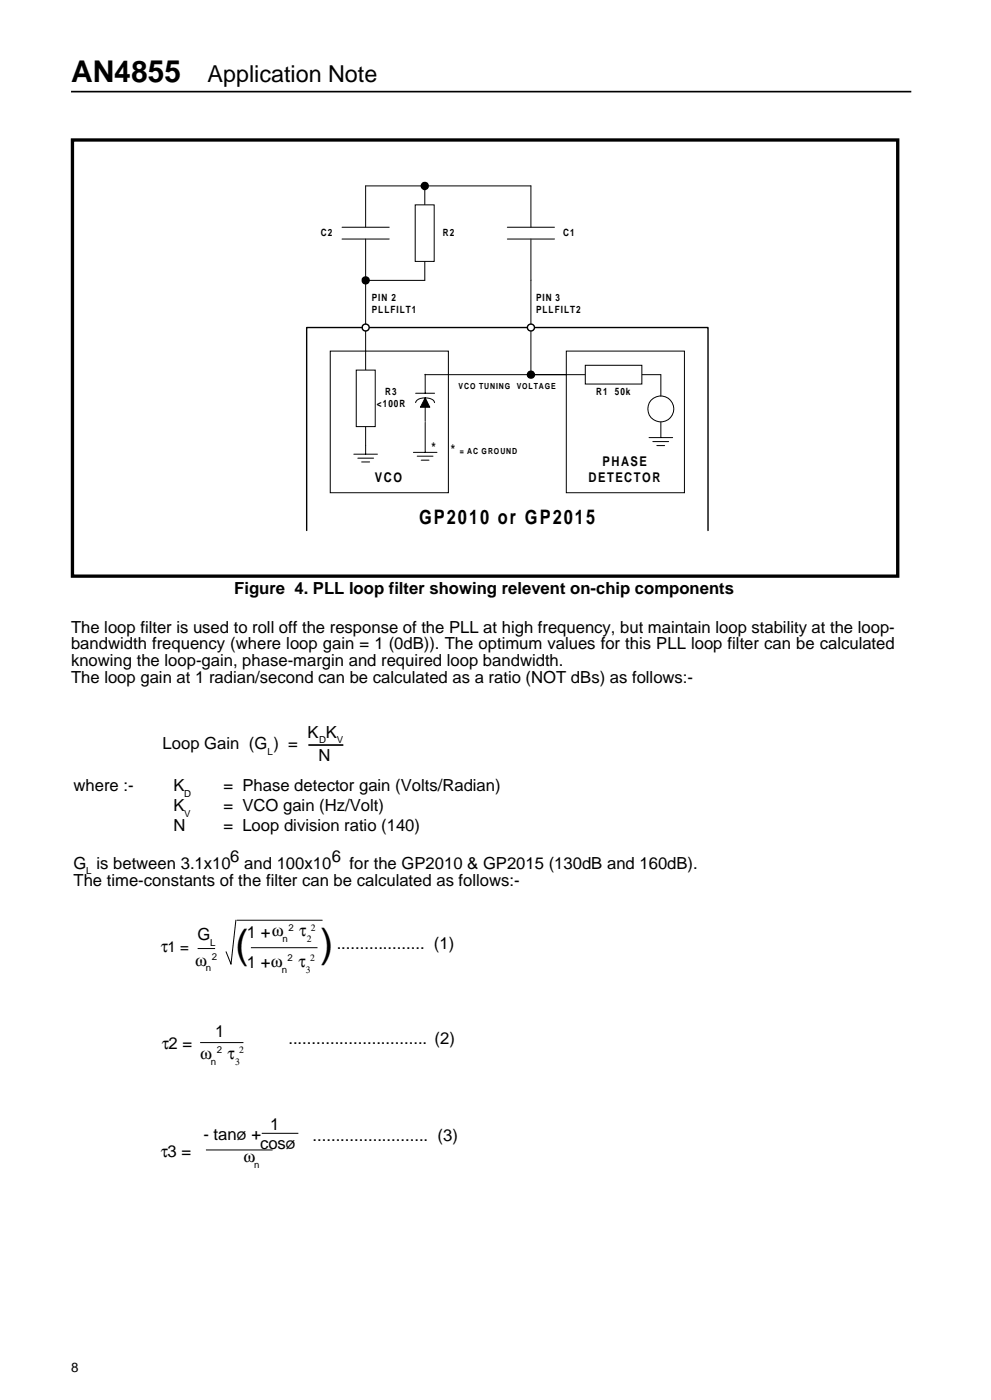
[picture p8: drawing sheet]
<svg xmlns="http://www.w3.org/2000/svg" width="210mm" height="297mm" viewBox="0 0 210 297" stroke-linecap="round" stroke-linejoin="round" font-family="sans-serif">
<defs><g id="words">
<g font-size="8.5">
<text x="49.8" y="203">(</text>
<text x="67.8" y="202.9">)</text>
</g>
<text font-size="6.3" x="15" y="17.3">AN4855</text>
<text font-size="4.9" x="44" y="17.3">Application Note</text>
<text font-size="4.2" x="88.7" y="111.1">GP2010 or GP2015</text>
<g font-size="3.5">
<text x="49.6" y="126">Figure 4. PLL loop filter showing relevent on-chip components</text>
<text x="15" y="134.1">The loop filter is used to roll off the response of the PLL at high frequency, but maintain loop stability at the loop-</text>
<text x="15" y="137.6">bandwidth frequency (where loop gain = 1 (0dB)). The optimum values for this PLL loop filter can be calculated</text>
<text x="15" y="141.1">knowing the loop-gain, phase-margin and required loop bandwidth.</text>
<text x="15" y="144.7">The loop gain at 1 radian/second can be calculated as a ratio (NOT dBs) as follows:-</text>
<text x="34.4" y="158.8">Loop Gain (G ) =</text>
<text x="65.1" y="156.3">K K</text>
<text x="67.4" y="161.2">N</text>
<text x="15.6" y="167.6">where :-</text>
<text x="36.7" y="167.6">K</text>
<text x="47.3" y="167.6">= Phase detector gain (Volts/Radian)</text>
<text x="36.7" y="171.8">K</text>
<text x="47.3" y="171.8">= VCO gain (Hz/Volt)</text>
<text x="36.7" y="176.1">N</text>
<text x="47.3" y="176.1">= Loop division ratio (140)</text>
<text x="15.6" y="184.2">G is between 3.1x10</text>
<text x="48.7" y="182.8">6</text>
<text x="51.7" y="184.2">and 100x10</text>
<text x="70.3" y="182.8">6</text>
<text x="74.1" y="184.2">for the GP2010 &amp; GP2015 (130dB and 160dB).</text>
<text x="15.6" y="187.7">The time-constants of the filter can be calculated as follows:-</text>
<text x="34.1" y="201.8">τ1 =</text>
<text x="41.9" y="199.2">G</text>
<text x="52.3" y="198.8">1 +ω</text>
<text x="63.4" y="198.5">τ</text>
<text x="71.3" y="201.1">................... (1)</text>
<text x="41.3" y="204.6">ω</text>
<text x="52.3" y="205.2">1 +ω</text>
<text x="63.2" y="205">τ</text>
<text x="45.6" y="219.8">1</text>
<text x="61.1" y="221.2">.............................. (2)</text>
<text x="34.3" y="222.3">τ2 =</text>
<text x="42.4" y="224.4">ω</text>
<text x="48.2" y="224.4">τ</text>
<text x="57.2" y="239.4">1</text>
<text x="34.1" y="245.2">τ3 =</text>
<text x="43.1" y="241.5">- tanø +</text>
<text x="55.1" y="243.4">cosø</text>
<text x="66.2" y="241.8">......................... (3)</text>
<text x="51.6" y="246.3">ω</text>
</g>
<g font-size="2.8">
<text x="91.4" y="95.8">*</text>
<text x="95.5" y="96.2">*</text>
<text x="127.6" y="98.8">PHASE</text>
<text x="79.4" y="102.1">VCO</text>
<text x="124.6" y="102.1">DETECTOR</text>
<text x="15" y="290.7">8</text>
</g>
<g font-size="2.1">
<text x="67.9" y="50">C2</text>
<text x="93.8" y="50">R2</text>
<text x="119.3" y="50">C1</text>
<text x="78.8" y="63.7">PIN 2</text>
<text x="113.6" y="63.7">PIN 3</text>
<text x="78.8" y="66.3">PLLFILT1</text>
<text x="113.6" y="66.3">PLLFILT2</text>
<text x="81.6" y="83.7">R3</text>
<text x="126.3" y="83.6">R1</text>
<text x="130.3" y="83.6">50k</text>
<text x="79.8" y="86.3">&lt;100R</text>
</g>
<g font-size="2">
<text x="56.7" y="160">L</text>
<text x="67.6" y="157.5">D</text>
<text x="71.3" y="157.5">V</text>
<text x="39" y="168.8">D</text>
<text x="39" y="173.1">V</text>
<text x="18.2" y="185.2">L</text>
<text x="61.1" y="197.2">2</text>
<text x="65.8" y="197.2">2</text>
<text x="44.5" y="200.4">L</text>
<text x="44.9" y="203.4">2</text>
<text x="59.8" y="199.7">n</text>
<text x="60.9" y="203.7">2</text>
<text x="65" y="199.7">2</text>
<text x="65.7" y="203.7">2</text>
<text x="43.6" y="205.9">n</text>
<text x="59.7" y="206.2">n</text>
<text x="64.8" y="206.2">3</text>
<text x="44.7" y="225.6">n</text>
<text x="45.9" y="223.1">2</text>
<text x="49.8" y="225.6">3</text>
<text x="50.7" y="223.1">2</text>
<text x="53.9" y="247.5">n</text>
</g>
<g font-size="1.8">
<text x="97.1" y="82.5">VCO TUNING</text>
<text x="109.4" y="82.5">VOLTAGE</text>
<text x="97.4" y="96.2">= AC GROUND</text>
</g>
</g></defs>
<path d="M15 19.4h178" fill="none" stroke="#000" stroke-width=".35"/>
<path d="M65 112.4v-43h85v43" fill="none" stroke="#000" stroke-width=".3"/>
<g fill="#fff" stroke="#000" stroke-width=".21">
<path d="M119.9 74.4h25.1v30h-25.1z" fill-rule="evenodd"/>
<path d="M70 74.4h25v30h-25z" fill-rule="evenodd"/>
</g>
<path d="M137.5 92.7h5M138.3 93.6h3.3M139.1 94.4h1.7M140 89.4v3.3" fill="none" stroke="#000" stroke-width=".21"/>
<circle cx="140" cy="86.7" r="2.75" fill="#fff" stroke="#000" stroke-width=".21"/>
<path d="M119.9 79.4h4.1M135.9 79.4h4.1" fill="none" stroke="#000" stroke-width=".21"/>
<path d="M124 77.4h11.9v4h-11.9z" fill-rule="evenodd" fill="#fff" stroke="#000" stroke-width=".21"/>
<path d="M112.5 59.4v20h7.4M90.1 79.3v4M140 79.4v4.5M87.6 95.9h5M88 85.3a2.38 2.38 0 0 1 3-.9 1.13 1.13 0 0 1 1.1 .9M88 83.3h4.1M88.4 96.7h3.3M89.2 97.5h1.7M90.1 84.3v5M90.1 89.5v6.4" fill="none" stroke="#000" stroke-width=".21"/>
<path d="M90.1 84.3l.9 2h-2z" fill-rule="evenodd" fill="#000" stroke="#000" stroke-width=".21"/>
<circle cx="112.4" cy="69.4" r=".75" fill="#fff" stroke="#000" stroke-width=".3"/>
<path d="M77.4 74.4v4M90 79.4h29.9M77.4 90.4v4" fill="none" stroke="#000" stroke-width=".21"/>
<circle cx="112.4" cy="79.4" r=".75" fill="#000" stroke="#000" stroke-width=".3"/>
<path d="M75.5 78.4h4v12h-4z" fill-rule="evenodd" fill="#fff" stroke="#000" stroke-width=".21"/>
<path d="M112.5 39.4v8.8M112.5 50.7v8.7" fill="none" stroke="#000" stroke-width=".21"/>
<path d="M107.5 50.7h10z" fill="#fff"/>
<path d="M77.4 39.4v8.8M77.4 50.7v8.7M107.5 50.7h10M107.5 48.2h10" fill="none" stroke="#000" stroke-width=".21"/>
<path d="M72.4 48.2h10z" fill="#fff"/>
<path d="M90 39.4v4M72.4 48.2h10M72.4 50.7h10M90 55.4v4" fill="none" stroke="#000" stroke-width=".21"/>
<path d="M87.9 43.4h4.1v12h-4.1z" fill-rule="evenodd" fill="#fff" stroke="#000" stroke-width=".21"/>
<path d="M77.4 39.4h35.1M90 59.4h-12.6v15" fill="none" stroke="#000" stroke-width=".21"/>
<circle cx="77.5" cy="69.4" r=".74" fill="#fff" stroke="#000" stroke-width=".3"/>
<g fill="#000" stroke="#000" stroke-width=".3">
<circle cx="90" cy="39.4" r=".75"/>
<circle cx="77.5" cy="59.4" r=".74"/>
</g>
<path d="M74.9 96.2h5M75.8 97.1h3.3M76.6 97.9h1.7M77.4 94.4v1.8M50 194.9l-1.1 9.6M50.1 195h18.2M41.9 201h3.7M47.9 201.6l1 2.7M53.1 200.8h14.2M42.4 220.9h9.2M43.6 243.7h14.1M55.4 240.2h7.8" fill="none" stroke="#000" stroke-width=".21"/>
<path d="M15.3 29.7h174.8v92.4h-174.8z" fill="none" stroke="#000" stroke-width=".71" stroke-linecap="butt"/>
<path d="M65.3 157.9h7.4" fill="none" stroke="#000" stroke-width=".35"/>
<use href="#words"/>
</svg>
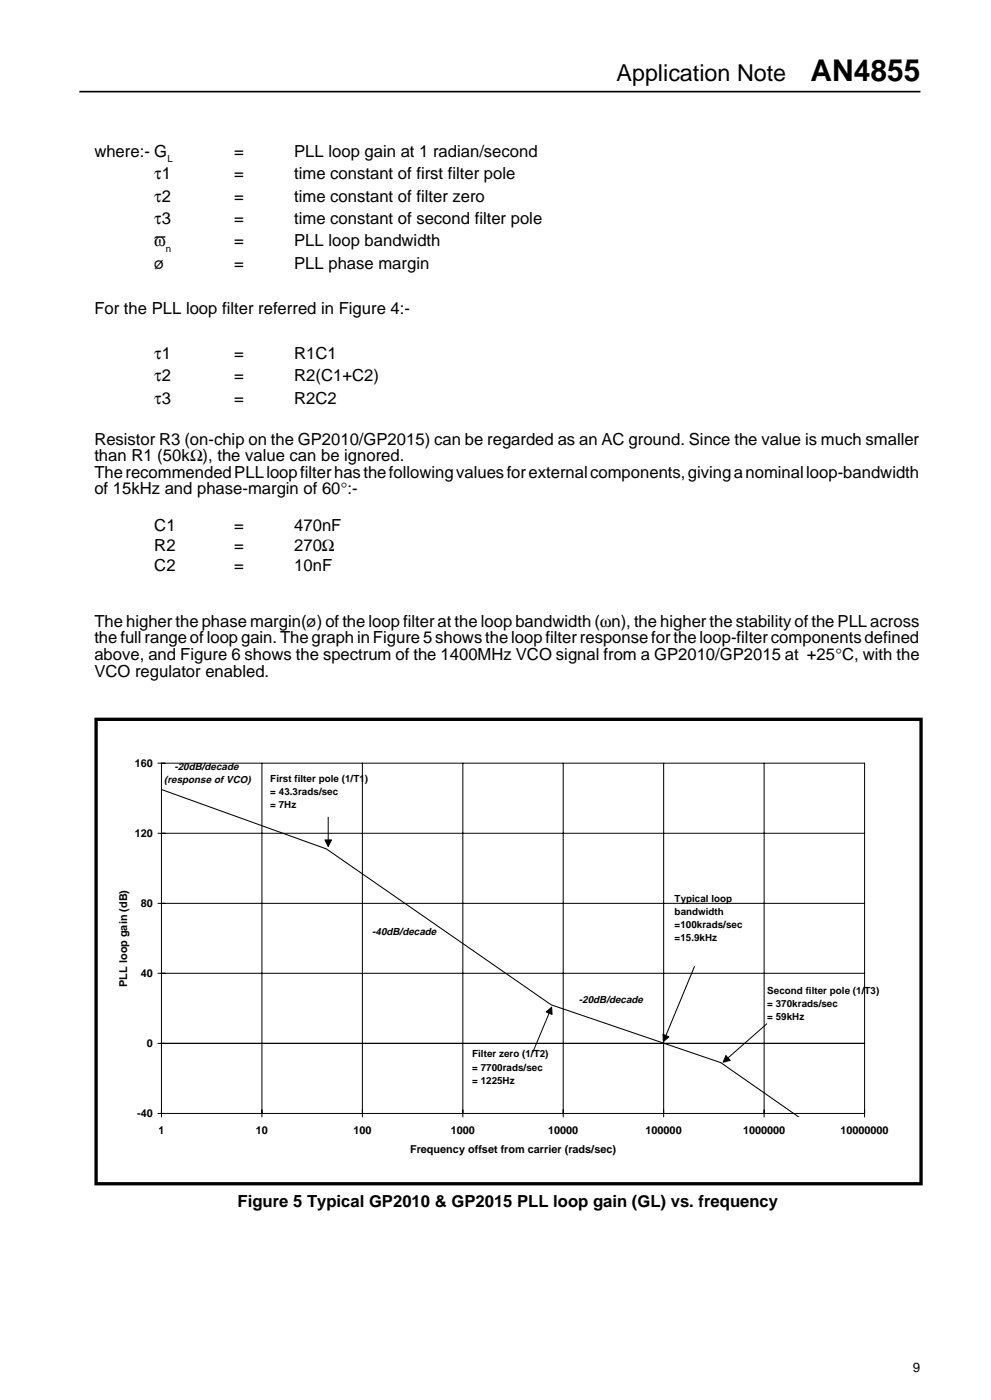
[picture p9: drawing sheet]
<svg xmlns="http://www.w3.org/2000/svg" width="210mm" height="297mm" viewBox="0 0 210 297" stroke-linecap="round" stroke-linejoin="round" font-family="sans-serif">
<defs><g id="words">
<text font-size="6.3" x="171.7" y="17.1">AN4855</text>
<text font-size="4.9" x="130.6" y="17.1">Application Note</text>
<g font-size="3.5">
<text x="20" y="33.2">where:- G</text>
<text x="49.6" y="33.2">=</text>
<text x="62.3" y="33.2">PLL loop gain at 1 radian/second</text>
<text x="32.7" y="37.9">τ1</text>
<text x="49.6" y="37.9">=</text>
<text x="62.3" y="37.9">time constant of first filter pole</text>
<text x="32.7" y="42.7">τ2</text>
<text x="32.7" y="47.5">τ3</text>
<text x="49.6" y="42.7">=</text>
<text x="49.6" y="47.5">=</text>
<text x="62.3" y="42.7">time constant of filter zero</text>
<text x="62.3" y="47.5">time constant of second filter pole</text>
<text x="32.7" y="52.2">ϖ</text>
<text x="49.6" y="52.2">=</text>
<text x="62.3" y="52.2">PLL loop bandwidth</text>
<text x="32.7" y="57">ø</text>
<text x="49.6" y="57">=</text>
<text x="62.3" y="57">PLL phase margin</text>
<text x="20" y="66.5">For the PLL loop filter referred in Figure 4:-</text>
<text x="32.7" y="76">τ1</text>
<text x="49.6" y="76">=</text>
<text x="62.3" y="76">R1C1</text>
<text x="32.7" y="80.8">τ2</text>
<text x="49.6" y="80.8">=</text>
<text x="62.3" y="80.8">R2(C1+C2)</text>
<text x="32.7" y="85.6">τ3</text>
<text x="49.6" y="85.6">=</text>
<text x="62.3" y="85.6">R2C2</text>
<text x="20" y="94.2">Resistor R3 (on-chip on the GP2010/GP2015) can be regarded as an AC ground. Since the value is much smaller</text>
<text x="20" y="97.7">than R1 (50kΩ), the value can be ignored.</text>
<text x="20" y="101.3">The recommended PLL loop filter has the following values for external components, giving a nominal loop-bandwidth</text>
<text x="20" y="104.8">of 15kHz and phase-margin of 60°:-</text>
<text x="32.7" y="112.6">C1</text>
<text x="49.6" y="112.6">=</text>
<text x="62.3" y="112.6">470nF</text>
<text x="32.7" y="116.8">R2</text>
<text x="49.6" y="116.8">=</text>
<text x="62.3" y="116.8">270Ω</text>
<text x="32.7" y="121">C2</text>
<text x="49.6" y="121">=</text>
<text x="62.3" y="121">10nF</text>
<text x="20" y="132.8">The higher the phase margin(ø) of the loop filter at the loop bandwidth (ωn), the higher the stability of the PLL across</text>
<text x="20" y="136.4">the full range of loop gain. The graph in Figure 5 shows the loop filter response for the loop-filter components defined</text>
<text x="20" y="139.9">above, and Figure 6 shows the spectrum of the 1400MHz VCO signal from a GP2010/GP2015 at +25°C, with the</text>
<text x="20" y="143.4">VCO regulator enabled.</text>
<text x="50.3" y="255.8">Figure 5 Typical GP2010 &amp; GP2015 PLL loop gain (GL) vs. frequency</text>
</g>
<text font-size="2.8" x="193.4" y="290.7">9</text>
<g font-size="2.3">
<text x="28.5" y="162.5">160</text>
<text x="28.5" y="177.3">120</text>
<text x="29.8" y="192.2">80</text>
<text x="26.9" y="209.1" transform="rotate(-90 26.9 209.1)">PLL loop gain (dB)</text>
<text x="29.8" y="207">40</text>
<text x="31.1" y="221.9">0</text>
<text x="29" y="236.7">-40</text>
<text x="33.6" y="240.2">1</text>
<text x="54.2" y="240.2">10</text>
<text x="74.8" y="240.2">100</text>
<text x="86.9" y="244.3">Frequency offset from carrier (rads/sec)</text>
<text x="95.5" y="240.2">1000</text>
<text x="116.1" y="240.2">10000</text>
<text x="136.7" y="240.2">100000</text>
<text x="157.4" y="240.2">1000000</text>
<text x="178" y="240.2">10000000</text>
</g>
<g font-size="2.1">
<text x="34.8" y="165.9">(response of VCO)</text>
<text x="36.9" y="163.1">-20dB/decade</text>
<text x="57.3" y="165.7">First filter pole (1/T1)</text>
<text x="57.3" y="168.4">= 43.3rads/sec</text>
<text x="57.3" y="171.2">= 7Hz</text>
<text x="142.9" y="191.1">Typical loop</text>
<text x="142.9" y="193.9">bandwidth</text>
<text x="142.9" y="196.7">=100krads/sec</text>
<text x="78.8" y="198.1">-40dB/decade</text>
<text x="142.9" y="199.5">=15.9kHz</text>
<text x="122.6" y="212.4">-20dB/decade</text>
<text x="162.5" y="210.7">Second filter pole (1/T3)</text>
<text x="162.5" y="213.4">= 370krads/sec</text>
<text x="162.5" y="216.2">= 59kHz</text>
<text x="100" y="224.1">Filter zero (1/T2)</text>
<text x="100" y="226.9">= 7700rads/sec</text>
<text x="100" y="229.6">= 1225Hz</text>
</g>
<g font-size="2">
<text x="35.5" y="34.4">L</text>
<text x="35.2" y="53.5">n</text>
</g>
</g></defs>
<path d="M16.8 19.4h178.2" fill="none" stroke="#000" stroke-width=".35"/>
<g fill="none" stroke="#000" stroke-width=".21">
<path d="M33.4 176.6h149.7M33.4 161.7h149.7v75M34.2 161.7v75M55.5 161.7v75M69.5 173.2v5.2M76.8 161.7v75M98 161.7v75M119.3 161.7v75M140.6 161.7v75M161.8 161.7v75M33.4 191.4h149.7M33.4 206.3h149.7"/>
<path d="M116.5 214.3l-3.7 8.8M162.4 217l-8.5 7.5M33.4 221.1h149.7M33.4 236h149.7"/>
</g>
<path d="M34.2 167.3l35 12.6 47.6 33 35.9 12.3 16.4 11.5M147.1 204.8l-6.2 15.1M33.9 221.1h149.3" fill="none" stroke="#000" stroke-width=".22"/>
<path d="M140.4 219.2l1.3 .5-1.2 1z" fill-rule="evenodd" fill="#000" stroke="#000" stroke-width=".22"/>
<g fill="#000" stroke="#000" stroke-width=".21">
<path d="M68.8 178h1.4l-.7 1.4z" fill-rule="evenodd"/>
<path d="M115.7 214.4l1.1-1 .1 1.6z" fill-rule="evenodd"/>
<path d="M153.7 223.7l1 1-1.5 .4z" fill-rule="evenodd"/>
</g>
<path d="M20.4 152.4h174.7v98.5h-174.7z" fill="none" stroke="#000" stroke-width=".71" stroke-linecap="butt"/>
<use href="#words"/>
</svg>
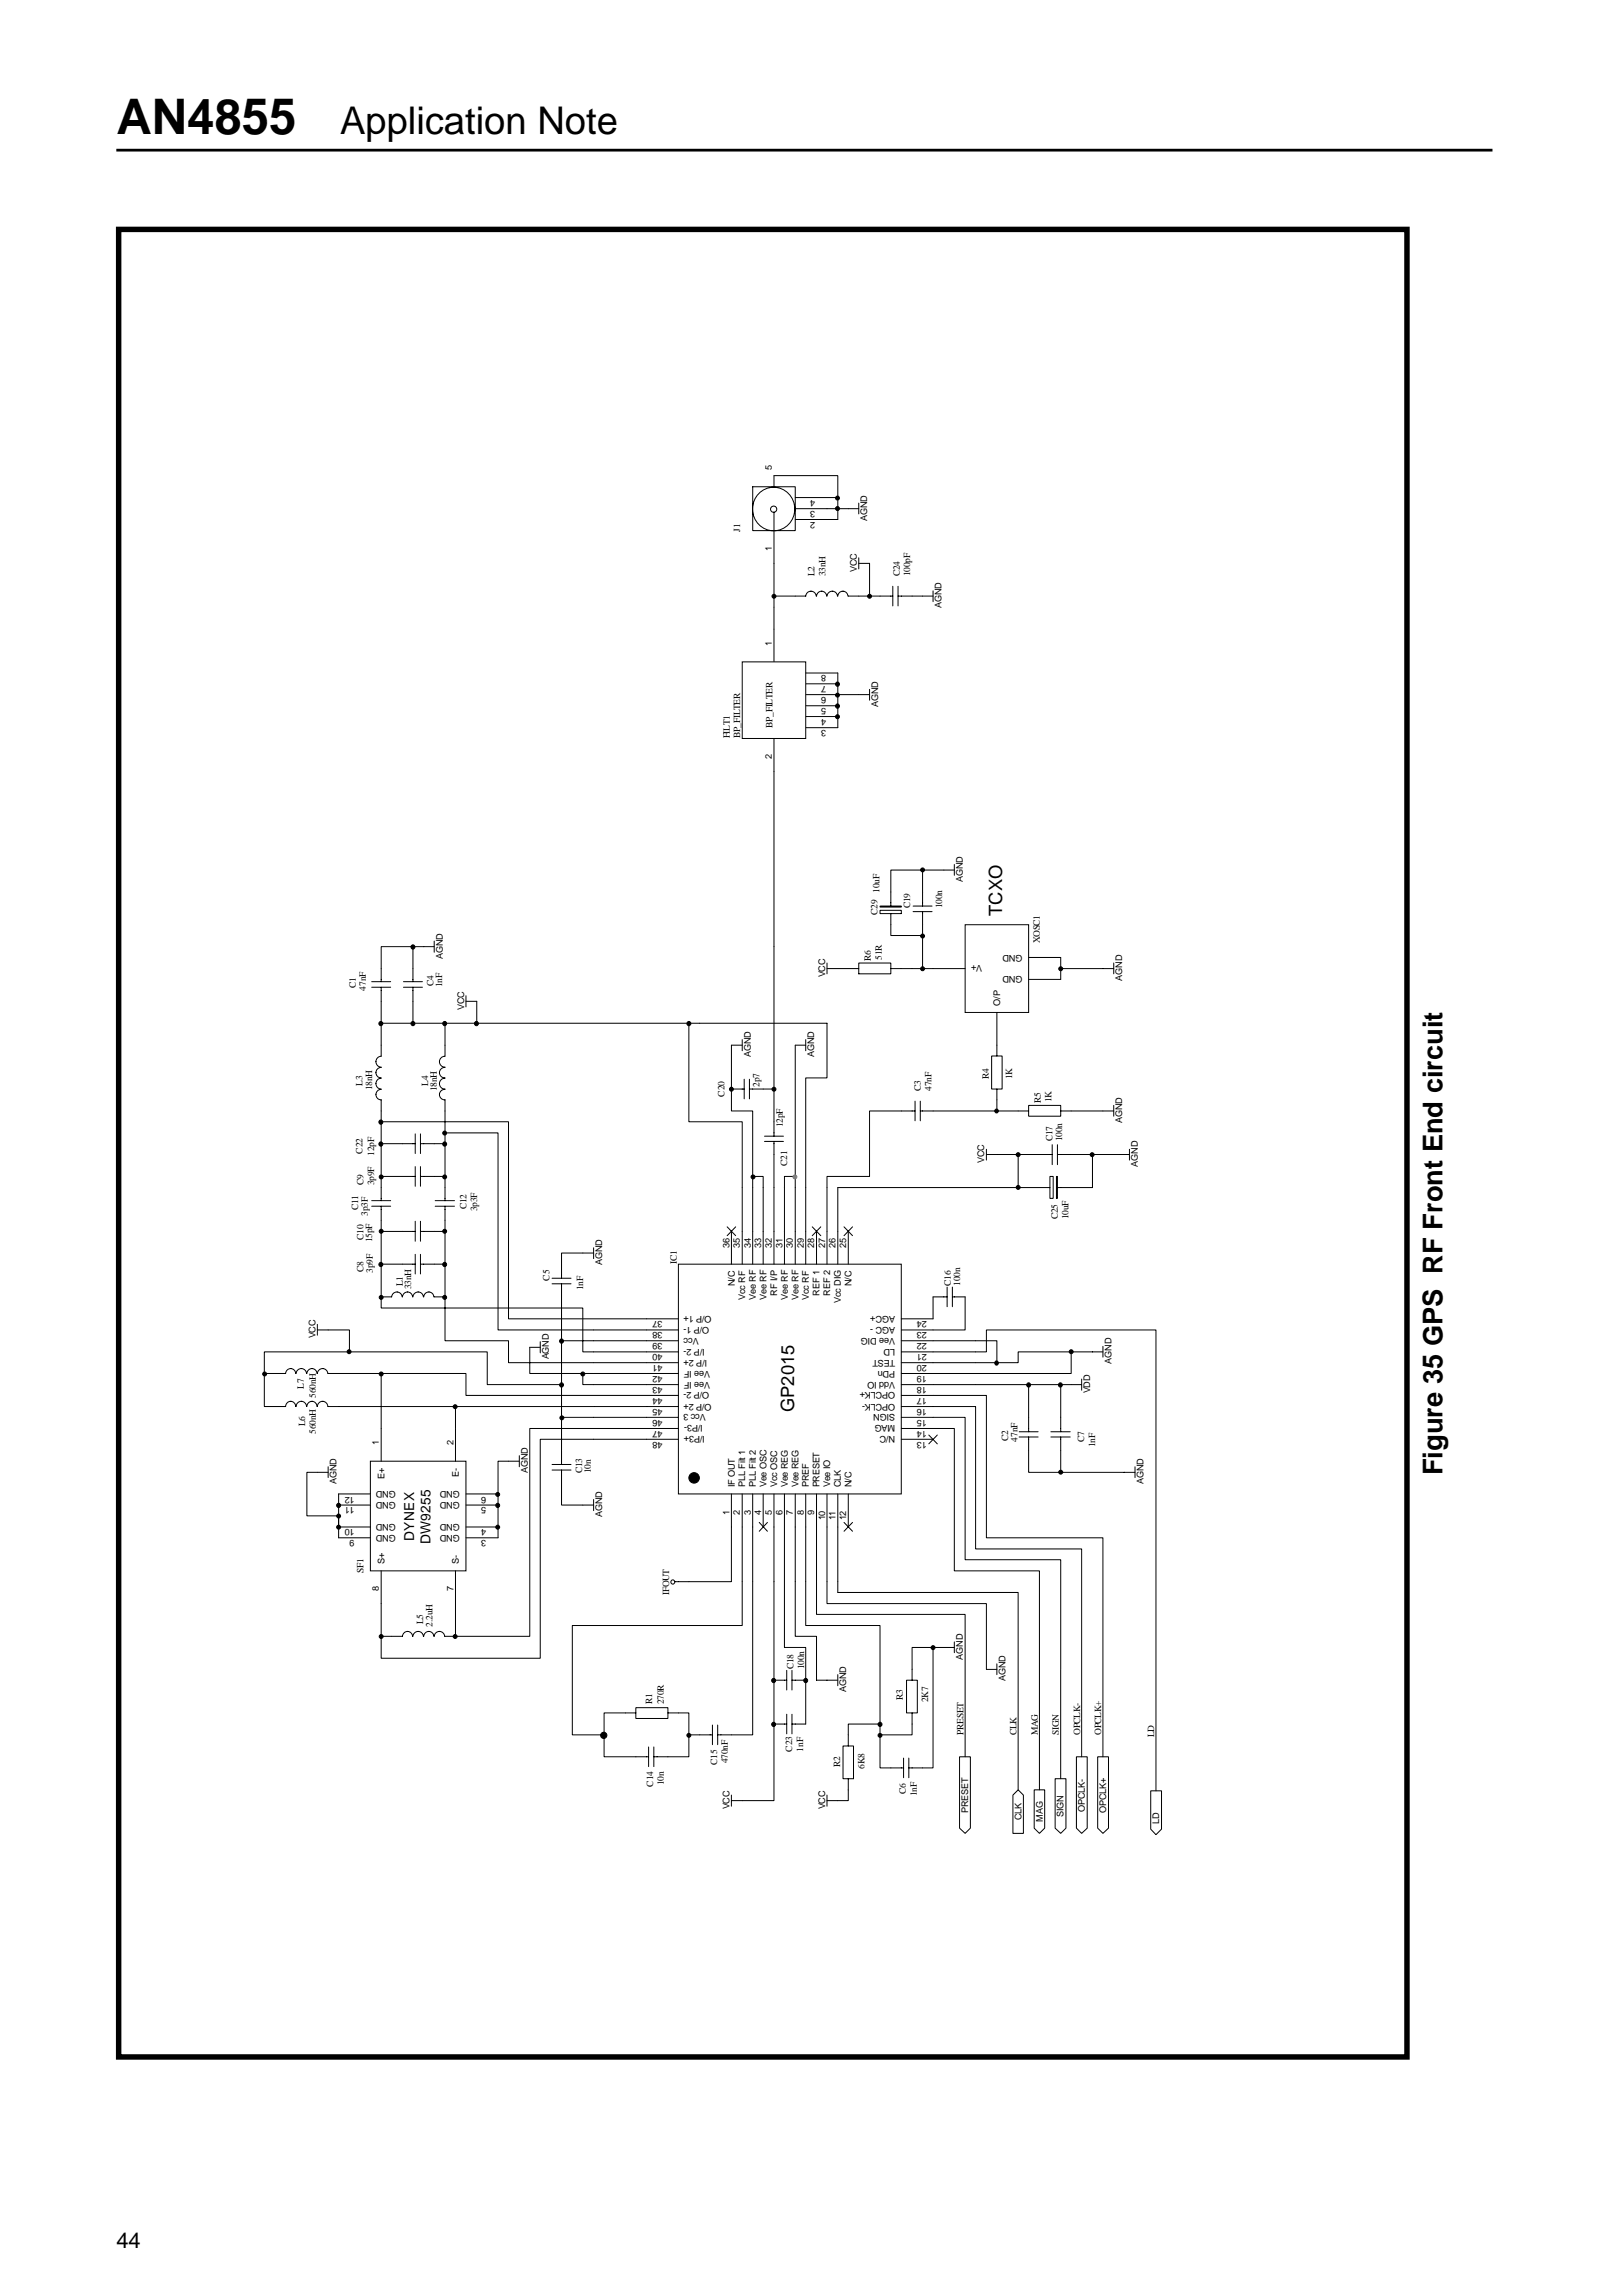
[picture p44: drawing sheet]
<svg xmlns="http://www.w3.org/2000/svg" width="210mm" height="297mm" viewBox="0 0 210 297" stroke-linecap="round" stroke-linejoin="round" font-family="sans-serif">
<defs><g id="words">
<text font-size="6.3" x="15" y="17.3">AN4855</text>
<text font-size="4.9" x="44" y="17.3">Application Note</text>
<text font-size="3.5" x="186.6" y="190.8" transform="rotate(-90 186.6 190.8)">Figure 35 GPS RF Front End circuit</text>
<text font-size="2.8" x="15" y="290.7">44</text>
<g font-size="2.4">
<text x="129.6" y="118.5" transform="rotate(-90 129.6 118.5)">TCXO</text>
<text x="102.7" y="182.6" transform="rotate(-90 102.7 182.6)">GP2015</text>
</g>
<g font-size="1.8">
<text x="53.6" y="199.3" transform="rotate(-90 53.6 199.3)">DYNEX</text>
<text x="55.7" y="199.7" transform="rotate(-90 55.7 199.7)">DW9255</text>
</g>
<g font-size="1.2">
<text x="99.8" y="60.8" transform="rotate(-90 99.8 60.8)">5</text>
<text x="105.4" y="64.7" transform="rotate(-180 105.4 64.7)">4</text>
<text x="95.7" y="68.8" transform="rotate(-90 95.7 68.8)">J1</text>
<text x="99.8" y="71.3" transform="rotate(-90 99.8 71.3)">1</text>
<text x="105.4" y="67.5" transform="rotate(-180 105.4 67.5)">2</text>
<text x="105.4" y="66.1" transform="rotate(-180 105.4 66.1)">3</text>
<text x="112.2" y="67.4" transform="rotate(-90 112.2 67.4)">AGND</text>
<text x="105.3" y="74.6" transform="rotate(-90 105.3 74.6)">L2</text>
<text x="106.7" y="74.6" transform="rotate(-90 106.7 74.6)">33nH</text>
<text x="110.8" y="74" transform="rotate(-90 110.8 74)">VCC</text>
<text x="116.4" y="74.6" transform="rotate(-90 116.4 74.6)">C24</text>
<text x="117.7" y="74.6" transform="rotate(-90 117.7 74.6)">100pF</text>
<text x="99.8" y="83.5" transform="rotate(-90 99.8 83.5)">1</text>
<text x="121.8" y="78.7" transform="rotate(-90 121.8 78.7)">AGND</text>
<text x="106.8" y="88.7" transform="rotate(-180 106.8 88.7)">7</text>
<text x="106.8" y="87.3" transform="rotate(-180 106.8 87.3)">8</text>
<text x="94.4" y="95.5" transform="rotate(-90 94.4 95.5)">FILT1</text>
<text x="95.7" y="95.5" transform="rotate(-90 95.7 95.5)">BP_FILTER</text>
<text x="99.9" y="94.1" transform="rotate(-90 99.9 94.1)">BP_FILTER</text>
<text x="106.8" y="94.4" transform="rotate(-180 106.8 94.4)">3</text>
<text x="106.8" y="93" transform="rotate(-180 106.8 93)">4</text>
<text x="106.8" y="91.6" transform="rotate(-180 106.8 91.6)">5</text>
<text x="106.8" y="90.2" transform="rotate(-180 106.8 90.2)">6</text>
<text x="113.6" y="91.4" transform="rotate(-90 113.6 91.4)">AGND</text>
<text x="99.8" y="98.2" transform="rotate(-90 99.8 98.2)">2</text>
<text x="113.5" y="118.3" transform="rotate(-90 113.5 118.3)">C29</text>
<text x="113.7" y="115.5" transform="rotate(-90 113.7 115.5)">10uF</text>
<text x="117.7" y="117.5" transform="rotate(-90 117.7 117.5)">C19</text>
<text x="121.9" y="117.5" transform="rotate(-90 121.9 117.5)">100n</text>
<text x="124.5" y="114.1" transform="rotate(-90 124.5 114.1)">AGND</text>
<text x="57.3" y="124" transform="rotate(-90 57.3 124)">AGND</text>
<text x="112.6" y="124.3" transform="rotate(-90 112.6 124.3)">R6</text>
<text x="114" y="124.1" transform="rotate(-90 114 124.1)">51R</text>
<text x="127" y="124.8" transform="rotate(-180 127 124.8)">V+</text>
<text x="132.2" y="123.4" transform="rotate(-180 132.2 123.4)">GND</text>
<text x="134.5" y="122" transform="rotate(-90 134.5 122)">XOSC1</text>
<text x="46" y="127.8" transform="rotate(-90 46 127.8)">C1</text>
<text x="47.3" y="128.1" transform="rotate(-90 47.3 128.1)">47nF</text>
<text x="56.1" y="127.5" transform="rotate(-90 56.1 127.5)">C4</text>
<text x="57.2" y="127.7" transform="rotate(-90 57.2 127.7)">1nF</text>
<text x="60" y="130.6" transform="rotate(-90 60 130.6)">VCC</text>
<text x="106.7" y="126.4" transform="rotate(-90 106.7 126.4)">VCC</text>
<text x="129.4" y="130.1" transform="rotate(-90 129.4 130.1)">O/P</text>
<text x="132.2" y="126.3" transform="rotate(-180 132.2 126.3)">GND</text>
<text x="145.1" y="126.8" transform="rotate(-90 145.1 126.8)">AGND</text>
<text x="97.1" y="136.7" transform="rotate(-90 97.1 136.7)">AGND</text>
<text x="105.3" y="136.7" transform="rotate(-90 105.3 136.7)">AGND</text>
<text x="46.9" y="140.4" transform="rotate(-90 46.9 140.4)">L3</text>
<text x="48.1" y="141" transform="rotate(-90 48.1 141)">18nH</text>
<text x="55.4" y="140.4" transform="rotate(-90 55.4 140.4)">L4</text>
<text x="56.5" y="141.1" transform="rotate(-90 56.5 141.1)">18nH</text>
<text x="93.7" y="141.8" transform="rotate(-90 93.7 141.8)">C20</text>
<text x="98.2" y="140.6" transform="rotate(-90 98.2 140.6)">2p7</text>
<text x="119.1" y="141.1" transform="rotate(-90 119.1 141.1)">C3</text>
<text x="120.5" y="141.1" transform="rotate(-90 120.5 141.1)">47nF</text>
<text x="127.9" y="139.6" transform="rotate(-90 127.9 139.6)">R4</text>
<text x="130.9" y="139.6" transform="rotate(-90 130.9 139.6)">1K</text>
<text x="134.6" y="142.7" transform="rotate(-90 134.6 142.7)">R5</text>
<text x="136" y="142.5" transform="rotate(-90 136 142.5)">1K</text>
<text x="46.9" y="149.2" transform="rotate(-90 46.9 149.2)">C22</text>
<text x="48.4" y="149.5" transform="rotate(-90 48.4 149.5)">12pF</text>
<text x="101.2" y="145.8" transform="rotate(-90 101.2 145.8)">12pF</text>
<text x="136.1" y="147.6" transform="rotate(-90 136.1 147.6)">C17</text>
<text x="137.4" y="147.6" transform="rotate(-90 137.4 147.6)">100n</text>
<text x="145.1" y="145.2" transform="rotate(-90 145.1 145.2)">AGND</text>
<text x="47" y="153.3" transform="rotate(-90 47 153.3)">C9</text>
<text x="48.4" y="153.3" transform="rotate(-90 48.4 153.3)">3p9F</text>
<text x="101.8" y="150.8" transform="rotate(-90 101.8 150.8)">C21</text>
<text x="127.3" y="150.5" transform="rotate(-90 127.3 150.5)">VCC</text>
<text x="147.2" y="150.9" transform="rotate(-90 147.2 150.9)">AGND</text>
<text x="46.3" y="156.6" transform="rotate(-90 46.3 156.6)">C11</text>
<text x="47" y="160.4" transform="rotate(-90 47 160.4)">C10</text>
<text x="47.6" y="157.3" transform="rotate(-90 47.6 157.3)">3p3F</text>
<text x="48.1" y="160.7" transform="rotate(-90 48.1 160.7)">15pF</text>
<text x="60.3" y="156.4" transform="rotate(-90 60.3 156.4)">C12</text>
<text x="61.7" y="156.7" transform="rotate(-90 61.7 156.7)">3p3F</text>
<text x="94.3" y="161.4" transform="rotate(-90 94.3 161.4)">36</text>
<text x="95.7" y="161.4" transform="rotate(-90 95.7 161.4)">35</text>
<text x="97.1" y="161.4" transform="rotate(-90 97.1 161.4)">34</text>
<text x="98.4" y="161.4" transform="rotate(-90 98.4 161.4)">33</text>
<text x="99.8" y="161.4" transform="rotate(-90 99.8 161.4)">32</text>
<text x="101.2" y="161.4" transform="rotate(-90 101.2 161.4)">31</text>
<text x="102.6" y="161.4" transform="rotate(-90 102.6 161.4)">30</text>
<text x="104" y="161.4" transform="rotate(-90 104 161.4)">29</text>
<text x="105.3" y="161.4" transform="rotate(-90 105.3 161.4)">28</text>
<text x="106.7" y="161.4" transform="rotate(-90 106.7 161.4)">27</text>
<text x="108.1" y="161.4" transform="rotate(-90 108.1 161.4)">26</text>
<text x="109.5" y="161.4" transform="rotate(-90 109.5 161.4)">25</text>
<text x="136.8" y="157.7" transform="rotate(-90 136.8 157.7)">C25</text>
<text x="138.2" y="157.7" transform="rotate(-90 138.2 157.7)">10uF</text>
<text x="47" y="164.5" transform="rotate(-90 47 164.5)">C8</text>
<text x="48.2" y="164.6" transform="rotate(-90 48.2 164.6)">3p9F</text>
<text x="52.1" y="166.3" transform="rotate(-90 52.1 166.3)">L1</text>
<text x="53.2" y="166.8" transform="rotate(-90 53.2 166.8)">33nH</text>
<text x="71.1" y="165.6" transform="rotate(-90 71.1 165.6)">C5</text>
<text x="75.4" y="166.9" transform="rotate(-90 75.4 166.9)">1nF</text>
<text x="77.9" y="163.6" transform="rotate(-90 77.9 163.6)">AGND</text>
<text x="87.5" y="163.5" transform="rotate(-90 87.5 163.5)">IC1</text>
<text x="95" y="166.3" transform="rotate(-90 95 166.3)">N/C</text>
<text x="100.5" y="167.6" transform="rotate(-90 100.5 167.6)">RF I/P</text>
<text x="106" y="167.6" transform="rotate(-90 106 167.6)">REF 1</text>
<text x="107.4" y="167.6" transform="rotate(-90 107.4 167.6)">REF 2</text>
<text x="110.1" y="166.3" transform="rotate(-90 110.1 166.3)">N/C</text>
<text x="123" y="166.3" transform="rotate(-90 123 166.3)">C16</text>
<text x="124.2" y="166.3" transform="rotate(-90 124.2 166.3)">100n</text>
<text x="40.8" y="173.1" transform="rotate(-90 40.8 173.1)">VCC</text>
<text x="85.7" y="172.3" transform="rotate(-180 85.7 172.3)">38</text>
<text x="85.7" y="173.7" transform="rotate(-180 85.7 173.7)">39</text>
<text x="85.7" y="170.9" transform="rotate(-180 85.7 170.9)">37</text>
<text x="90.4" y="173" transform="rotate(-180 90.4 173)">Vcc</text>
<text x="91.7" y="171.6" transform="rotate(-180 91.7 171.6)">O/P 1-</text>
<text x="92" y="170.2" transform="rotate(-180 92 170.2)">O/P 1+</text>
<text x="96.4" y="168.2" transform="rotate(-90 96.4 168.2)">Vcc RF</text>
<text x="97.8" y="168.2" transform="rotate(-90 97.8 168.2)">Vee RF</text>
<text x="99.1" y="168.2" transform="rotate(-90 99.1 168.2)">Vee RF</text>
<text x="101.9" y="168.2" transform="rotate(-90 101.9 168.2)">Vee RF</text>
<text x="103.3" y="168.2" transform="rotate(-90 103.3 168.2)">Vee RF</text>
<text x="104.6" y="168.2" transform="rotate(-90 104.6 168.2)">Vcc RF</text>
<text x="108.7" y="168.6" transform="rotate(-90 108.7 168.6)">Vcc DIG</text>
<text x="115.8" y="173" transform="rotate(-180 115.8 173)">Vee DIG</text>
<text x="115.8" y="171.6" transform="rotate(-180 115.8 171.6)">AGC -</text>
<text x="115.8" y="170.2" transform="rotate(-180 115.8 170.2)">AGC+</text>
<text x="119.9" y="173.7" transform="rotate(-180 119.9 173.7)">22</text>
<text x="119.9" y="172.3" transform="rotate(-180 119.9 172.3)">23</text>
<text x="119.9" y="170.9" transform="rotate(-180 119.9 170.9)">24</text>
<text x="39.3" y="179.6" transform="rotate(-90 39.3 179.6)">L7</text>
<text x="71" y="175.8" transform="rotate(-90 71 175.8)">AGND</text>
<text x="85.7" y="179.4" transform="rotate(-180 85.7 179.4)">43</text>
<text x="85.7" y="176.5" transform="rotate(-180 85.7 176.5)">41</text>
<text x="85.7" y="178" transform="rotate(-180 85.7 178)">42</text>
<text x="85.7" y="175.1" transform="rotate(-180 85.7 175.1)">40</text>
<text x="91.2" y="174.4" transform="rotate(-180 91.2 174.4)">I/P 2-</text>
<text x="91.5" y="175.9" transform="rotate(-180 91.5 175.9)">I/P 2+</text>
<text x="91.8" y="178.7" transform="rotate(-180 91.8 178.7)">Vee IF</text>
<text x="91.8" y="177.3" transform="rotate(-180 91.8 177.3)">Vee IF</text>
<text x="115.8" y="178.7" transform="rotate(-180 115.8 178.7)">Vdd IO</text>
<text x="115.8" y="177.3" transform="rotate(-180 115.8 177.3)">PDn</text>
<text x="115.8" y="175.9" transform="rotate(-180 115.8 175.9)">TEST</text>
<text x="115.8" y="174.4" transform="rotate(-180 115.8 174.4)">LD</text>
<text x="119.9" y="178" transform="rotate(-180 119.9 178)">19</text>
<text x="119.9" y="176.5" transform="rotate(-180 119.9 176.5)">20</text>
<text x="119.9" y="175.1" transform="rotate(-180 119.9 175.1)">21</text>
<text x="119.9" y="179.4" transform="rotate(-180 119.9 179.4)">18</text>
<text x="143.7" y="176.4" transform="rotate(-90 143.7 176.4)">AGND</text>
<text x="39.5" y="184.4" transform="rotate(-90 39.5 184.4)">L6</text>
<text x="40.8" y="180.8" transform="rotate(-90 40.8 180.8)">560nH</text>
<text x="40.8" y="185.4" transform="rotate(-90 40.8 185.4)">560nH</text>
<text x="85.7" y="185" transform="rotate(-180 85.7 185)">47</text>
<text x="85.7" y="183.6" transform="rotate(-180 85.7 183.6)">46</text>
<text x="85.7" y="180.8" transform="rotate(-180 85.7 180.8)">44</text>
<text x="85.7" y="182.2" transform="rotate(-180 85.7 182.2)">45</text>
<text x="90.9" y="184.3" transform="rotate(-180 90.9 184.3)">I/P3-</text>
<text x="91.2" y="185.8" transform="rotate(-180 91.2 185.8)">I/P3+</text>
<text x="91.3" y="182.9" transform="rotate(-180 91.3 182.9)">Vcc 3</text>
<text x="91.7" y="180.1" transform="rotate(-180 91.7 180.1)">O/P 2-</text>
<text x="92" y="181.5" transform="rotate(-180 92 181.5)">O/P 2+</text>
<text x="115.8" y="185.8" transform="rotate(-180 115.8 185.8)">N/C</text>
<text x="115.8" y="184.3" transform="rotate(-180 115.8 184.3)">MAG</text>
<text x="115.8" y="182.9" transform="rotate(-180 115.8 182.9)">SIGN</text>
<text x="115.8" y="181.5" transform="rotate(-180 115.8 181.5)">OPCLK-</text>
<text x="115.8" y="180.1" transform="rotate(-180 115.8 180.1)">OPCLK+</text>
<text x="119.9" y="185" transform="rotate(-180 119.9 185)">14</text>
<text x="119.9" y="183.6" transform="rotate(-180 119.9 183.6)">15</text>
<text x="119.9" y="182.2" transform="rotate(-180 119.9 182.2)">16</text>
<text x="119.9" y="180.8" transform="rotate(-180 119.9 180.8)">17</text>
<text x="141" y="180.2" transform="rotate(-90 141 180.2)">VDD</text>
<text x="43.5" y="191.9" transform="rotate(-90 43.5 191.9)">AGND</text>
<text x="49" y="186.9" transform="rotate(-90 49 186.9)">1</text>
<text x="49.7" y="191.3" transform="rotate(-90 49.7 191.3)">E+</text>
<text x="58.7" y="186.9" transform="rotate(-90 58.7 186.9)">2</text>
<text x="59.3" y="191" transform="rotate(-90 59.3 191)">E-</text>
<text x="68.3" y="190.5" transform="rotate(-90 68.3 190.5)">AGND</text>
<text x="75.3" y="190.5" transform="rotate(-90 75.3 190.5)">C13</text>
<text x="76.4" y="190.5" transform="rotate(-90 76.4 190.5)">10n</text>
<text x="85.7" y="186.5" transform="rotate(-180 85.7 186.5)">48</text>
<text x="119.9" y="186.5" transform="rotate(-180 119.9 186.5)">13</text>
<text x="130.4" y="186.3" transform="rotate(-90 130.4 186.3)">C2</text>
<text x="131.6" y="186.4" transform="rotate(-90 131.6 186.4)">47nF</text>
<text x="140.2" y="186.4" transform="rotate(-90 140.2 186.4)">C7</text>
<text x="141.6" y="187.2" transform="rotate(-90 141.6 187.2)">1nF</text>
<text x="147.9" y="191.9" transform="rotate(-90 147.9 191.9)">AGND</text>
<text x="45.9" y="197.8" transform="rotate(-180 45.9 197.8)">10</text>
<text x="45.9" y="194.9" transform="rotate(-180 45.9 194.9)">11</text>
<text x="45.9" y="193.6" transform="rotate(-180 45.9 193.6)">12</text>
<text x="51.2" y="197.1" transform="rotate(-180 51.2 197.1)">GND</text>
<text x="51.2" y="194.3" transform="rotate(-180 51.2 194.3)">GND</text>
<text x="51.2" y="192.8" transform="rotate(-180 51.2 192.8)">GND</text>
<text x="59.5" y="197.1" transform="rotate(-180 59.5 197.1)">GND</text>
<text x="59.5" y="194.3" transform="rotate(-180 59.5 194.3)">GND</text>
<text x="59.5" y="192.8" transform="rotate(-180 59.5 192.8)">GND</text>
<text x="62.9" y="197.8" transform="rotate(-180 62.9 197.8)">4</text>
<text x="62.9" y="194.9" transform="rotate(-180 62.9 194.9)">5</text>
<text x="62.9" y="193.6" transform="rotate(-180 62.9 193.6)">6</text>
<text x="77.9" y="196.2" transform="rotate(-90 77.9 196.2)">AGND</text>
<text x="94.3" y="195.9" transform="rotate(-90 94.3 195.9)">1</text>
<text x="95" y="192.4" transform="rotate(-90 95 192.4)">IF OUT</text>
<text x="95.7" y="195.9" transform="rotate(-90 95.7 195.9)">2</text>
<text x="96.4" y="192.4" transform="rotate(-90 96.4 192.4)">PLL Filt 1</text>
<text x="97.1" y="195.9" transform="rotate(-90 97.1 195.9)">3</text>
<text x="97.8" y="192.4" transform="rotate(-90 97.8 192.4)">PLL Filt 2</text>
<text x="98.4" y="195.9" transform="rotate(-90 98.4 195.9)">4</text>
<text x="99.1" y="192.4" transform="rotate(-90 99.1 192.4)">Vee OSC</text>
<text x="99.8" y="195.9" transform="rotate(-90 99.8 195.9)">5</text>
<text x="100.5" y="192.4" transform="rotate(-90 100.5 192.4)">Vcc OSC</text>
<text x="101.2" y="195.9" transform="rotate(-90 101.2 195.9)">6</text>
<text x="101.9" y="192.4" transform="rotate(-90 101.9 192.4)">Vee REG</text>
<text x="102.6" y="195.9" transform="rotate(-90 102.6 195.9)">7</text>
<text x="103.3" y="192.4" transform="rotate(-90 103.3 192.4)">Vee REG</text>
<text x="104" y="195.9" transform="rotate(-90 104 195.9)">8</text>
<text x="104.6" y="192.4" transform="rotate(-90 104.6 192.4)">PREF</text>
<text x="105.3" y="195.9" transform="rotate(-90 105.3 195.9)">9</text>
<text x="106" y="192.4" transform="rotate(-90 106 192.4)">PRESET</text>
<text x="106.7" y="196.6" transform="rotate(-90 106.7 196.6)">10</text>
<text x="107.4" y="192.4" transform="rotate(-90 107.4 192.4)">Vee IO</text>
<text x="108.1" y="196.6" transform="rotate(-90 108.1 196.6)">11</text>
<text x="108.7" y="192.4" transform="rotate(-90 108.7 192.4)">CLK</text>
<text x="109.5" y="196.6" transform="rotate(-90 109.5 196.6)">12</text>
<text x="110.1" y="192.4" transform="rotate(-90 110.1 192.4)">N/C</text>
<text x="45.9" y="199.2" transform="rotate(-180 45.9 199.2)">9</text>
<text x="47" y="203.4" transform="rotate(-90 47 203.4)">SF1</text>
<text x="49.7" y="202.3" transform="rotate(-90 49.7 202.3)">S+</text>
<text x="51.2" y="198.5" transform="rotate(-180 51.2 198.5)">GND</text>
<text x="59.3" y="202.3" transform="rotate(-90 59.3 202.3)">S-</text>
<text x="59.5" y="198.5" transform="rotate(-180 59.5 198.5)">GND</text>
<text x="62.9" y="199.2" transform="rotate(-180 62.9 199.2)">3</text>
<text x="49" y="205.8" transform="rotate(-90 49 205.8)">8</text>
<text x="58.7" y="205.8" transform="rotate(-90 58.7 205.8)">7</text>
<text x="86.6" y="206.3" transform="rotate(-90 86.6 206.3)">IFOUT</text>
<text x="54.7" y="210.1" transform="rotate(-90 54.7 210.1)">L5</text>
<text x="55.9" y="210.4" transform="rotate(-90 55.9 210.4)">2.2uH</text>
<text x="102.6" y="215.9" transform="rotate(-90 102.6 215.9)">C18</text>
<text x="104" y="215.9" transform="rotate(-90 104 215.9)">100n</text>
<text x="124.5" y="214.6" transform="rotate(-90 124.5 214.6)">AGND</text>
<text x="84.3" y="220.4" transform="rotate(-90 84.3 220.4)">R1</text>
<text x="85.9" y="220.4" transform="rotate(-90 85.9 220.4)">270R</text>
<text x="109.5" y="218.9" transform="rotate(-90 109.5 218.9)">AGND</text>
<text x="116.8" y="219.8" transform="rotate(-90 116.8 219.8)">R3</text>
<text x="120" y="220.1" transform="rotate(-90 120 220.1)">2K7</text>
<text x="130" y="217.4" transform="rotate(-90 130 217.4)">AGND</text>
<text x="102.5" y="226.5" transform="rotate(-90 102.5 226.5)">C23</text>
<text x="103.9" y="226.5" transform="rotate(-90 103.9 226.5)">1nF</text>
<text x="124.6" y="224.4" transform="rotate(-90 124.6 224.4)">PRESET</text>
<text x="131.5" y="224.4" transform="rotate(-90 131.5 224.4)">CLK</text>
<text x="134.2" y="224.4" transform="rotate(-90 134.2 224.4)">MAG</text>
<text x="136.9" y="224.4" transform="rotate(-90 136.9 224.4)">SIGN</text>
<text x="139.7" y="224.4" transform="rotate(-90 139.7 224.4)">OPCLK-</text>
<text x="142.4" y="224.4" transform="rotate(-90 142.4 224.4)">OPCLK+</text>
<text x="149.3" y="224.7" transform="rotate(-90 149.3 224.7)">LD</text>
<text x="84.5" y="231.1" transform="rotate(-90 84.5 231.1)">C14</text>
<text x="85.9" y="230.9" transform="rotate(-90 85.9 230.9)">10n</text>
<text x="92.7" y="228.2" transform="rotate(-90 92.7 228.2)">C15</text>
<text x="94.1" y="228.1" transform="rotate(-90 94.1 228.1)">470nF</text>
<text x="108.6" y="228.5" transform="rotate(-90 108.6 228.5)">R2</text>
<text x="111.8" y="228.8" transform="rotate(-90 111.8 228.8)">6K8</text>
<text x="117.2" y="232" transform="rotate(-90 117.2 232)">C6</text>
<text x="118.6" y="232.3" transform="rotate(-90 118.6 232.3)">1nF</text>
<text x="94.3" y="234" transform="rotate(-90 94.3 234)">VCC</text>
<text x="106.7" y="234" transform="rotate(-90 106.7 234)">VCC</text>
<text x="125.2" y="234.4" transform="rotate(-90 125.2 234.4)">PRESET</text>
<text x="132.1" y="235.4" transform="rotate(-90 132.1 235.4)">CLK</text>
<text x="134.9" y="235.6" transform="rotate(-90 134.9 235.6)">MAG</text>
<text x="137.6" y="235" transform="rotate(-90 137.6 235)">SIGN</text>
<text x="140.3" y="234.3" transform="rotate(-90 140.3 234.3)">OPCLK-</text>
<text x="143.1" y="234.4" transform="rotate(-90 143.1 234.4)">OPCLK+</text>
<text x="149.9" y="235.8" transform="rotate(-90 149.9 235.8)">LD</text>
</g>
</g></defs>
<path d="M15 19.4h178" fill="none" stroke="#000" stroke-width=".35"/>
<path d="M15.3 29.7h166.7v236.3h-166.7z" fill="none" stroke="#000" stroke-width=".71" stroke-linecap="butt"/>
<path d="M148 89.6h5.8v5.9h-5.8z" fill-rule="evenodd" fill="#fff" stroke="#fff" stroke-width=".13"/>
<g fill="#fff" stroke="#000" stroke-width=".13">
<path d="M139.2 227.2h1.4v9.2l-.7 .7-.7-.7z" fill-rule="evenodd"/>
<path d="M142 227.2h1.4v9.2l-.8 .7-.6-.7z" fill-rule="evenodd"/>
<path d="M131 232.2l.7-.7 .7 .7v4.9h-1.4z" fill-rule="evenodd"/>
<path d="M133.8 231.5h1.3v4.9l-.7 .7-.6-.7z" fill-rule="evenodd"/>
<path d="M136.5 230h1.4v6.4l-.7 .7-.7-.7z" fill-rule="evenodd"/>
<path d="M148.8 231.6h1.4v5l-.7 .7-.7-.7z" fill-rule="evenodd"/>
<path d="M124.1 227.2h1.4v9.2l-.7 .7-.7-.7z" fill-rule="evenodd"/>
</g>
<g fill="none" stroke="#000" stroke-width=".13">
<path d="M100.1 77.1h2.8M122.1 112.5h-2.8v2.9M48.1 127.7h2.4M48.1 127h2.4M49.3 139.4a.7 .7 0 0 0-.7 .7 .7 .7 0 0 0 .7 .7M49.3 138.1a.68 .68 0 0 0-.7 .6 .68 .68 0 0 0 .7 .7M49.3 136.6a.7 .7 0 0 0-.7 .7 .7 .7 0 0 0 .7 .7M49.3 127.7v1.8M49.3 135.2v1.4M49.3 125.3v1.7M52.2 127.7h2.4M52.2 127h2.4"/>
<path d="M53.4 127.7v1.8M54.8 122.4h-1.4v4.6M57.6 139.5a.7 .7 0 0 0-.8 .6 .7 .7 0 0 0 .8 .7M57.6 138.1a.68 .68 0 0 0-.8 .6 .68 .68 0 0 0 .8 .7M57.6 136.6a.7 .7 0 0 0-.8 .7 .7 .7 0 0 0 .8 .7M57.6 135.2v1.4M60.3 128.8v1.4M60.3 129.5h1.4M96.2 139.6v2.5M96.9 139.6v2.5M107 124.5v1.4M107 125.3h2.7"/>
<path d="M48.1 156h2.4M48.1 155.3h2.4M49.3 140.9a.68 .68 0 0 0-.7 .7 .68 .68 0 0 0 .7 .6v1.5M49.3 156v13.2h26.1v5.6h1.4M49.3 159.3h4.4M49.3 153.6v1.7M52 152.1h1.7M53.7 157.9v2.6M53.7 150.9v2.5M54.4 159.3h3.2M54.4 150.9v2.5M54.4 157.9v2.6"/>
<path d="M54.4 152.1h1.8M56.3 156h2.5M56.3 155.3h2.5M57.6 140.9a.68 .68 0 0 0-.8 .7 .68 .68 0 0 0 .8 .6v1.5M57.6 156v17.4h8.2v2.8h11M57.6 153.6v1.7M94.6 140.8h1.6M96.9 140.8h3.2M97.3 152.2h1.4v1.4M98.9 146.9h2.4M98.9 147.6h2.4M100.1 145.1v1.8"/>
<path d="M100.1 147.6v6M102.8 152.2h-1.3v1.4M116.6 143.7h-4.1v8.5h-5.5v1.4M127.6 148.6v1.4M127.6 149.3h1.3M134.4 149.3h1.7M136.1 148v2.6M136.8 149.3h1.7M136.8 148v2.6M34.2 177.6h2.7a.66 .66 0 0 1 .7-.6 .66 .66 0 0 1 .6 .6M38.3 177.6a.68 .68 0 0 1 .7-.6 .68 .68 0 0 1 .6 .6M39.7 177.6a.66 .66 0 0 1 .6-.6 .66 .66 0 0 1 .7 .6"/>
<path d="M41 172h4.2v2.8M41 171.3v1.4M41 177.6a.68 .68 0 0 1 .7-.6 .68 .68 0 0 1 .7 .6M42.4 177.6h1.4M49.3 167.7h1.4a.68 .68 0 0 1 .6-.6 .68 .68 0 0 1 .7 .6M49.3 163.5h4.4M52.1 167.7a.66 .66 0 0 1 .6-.6 .66 .66 0 0 1 .7 .6M53.4 167.7a.68 .68 0 0 1 .7-.6 .68 .68 0 0 1 .7 .6M53.7 162.2v2.6M54.4 163.5h3.2M54.4 162.2v2.6M54.8 167.7a.66 .66 0 0 1 .7-.6 .66 .66 0 0 1 .6 .6"/>
<path d="M56.2 167.7h1.4M68.5 174.2v3.4h8.3M71.4 165.3h2.5M71.4 166h2.5M72.6 179.1h-9.6v-4.3h-28.8v7.1h2.7a.66 .66 0 0 1 .7-.7 .66 .66 0 0 1 .6 .7M72.6 166v23.4M72.6 173.4h4.2M75.4 177.6v1.5h1.4M75.4 162.1h-2.8v3.2M120.7 167.7h1.8M122.5 166.5v2.5M123.2 167.7h1.6"/>
<path d="M123.2 166.5v2.5M126.2 173.4h2.7v2.8h-2.7M133 179.1v6.1M138.5 179.1h1.4M139.9 178.4v1.4M38.3 181.9a.68 .68 0 0 1 .7-.7 .68 .68 0 0 1 .6 .7M39.7 181.9a.66 .66 0 0 1 .6-.7 .66 .66 0 0 1 .7 .7M41 190.4h-1.3v5.6h4.1M41 181.9a.68 .68 0 0 1 .7-.7 .68 .68 0 0 1 .7 .7M42.4 181.9h1.4M65.8 189h-1.4v9.9M71.4 189.4h2.5"/>
<path d="M71.4 190.1h2.5M72.6 190.1v4.6h2.8M72.6 183.3h4.2M76.8 186.1h-6.9v28.4h-20.6v-7.1M76.8 184.7h-8.3v26.9h-9.6v-4.2M131.8 185.2h2.5M131.8 185.8h2.5M133 185.8v1.8M135.9 185.2h2.5M135.9 185.8h2.5M137.2 183.3v1.9M137.2 185.8v1.8"/>
<path d="M50.7 211.6h1.4a.66 .66 0 0 1 .6-.6 .66 .66 0 0 1 .7 .6M53.4 211.6a.68 .68 0 0 1 .7-.6 .68 .68 0 0 1 .7 .6M54.8 211.6a.66 .66 0 0 1 .7-.6 .66 .66 0 0 1 .6 .6M56.2 211.6a.68 .68 0 0 1 .6-.6 .68 .68 0 0 1 .7 .6M57.6 211.6h1.3M96 204.6v5.6h-22v14.2h4.1M97.3 204.6v19.8h-2.7M104.2 204.6v5.6h9.6v18.4h3.1M107 204.6v2.8h20.6v8.5M120.7 213.1v15.5h-3.2M122.1 213.1h-4.1v2.8M80.9 221.5h-2.8v5.7h5.8"/>
<path d="M83.9 225.9v2.6M84.6 225.9v2.6M87.7 221.5h1.4v5.7h-4.5M94.6 232.9h1.4M94.6 232.2v1.4M107 232.2v1.4M109.7 231.5v1.4h-2.7M113.8 223h-4.1v1.4M116.9 227.4v2.5M117.5 227.4v2.5M118 223v1.4h-4.2"/>
</g>
<circle cx="78.1" cy="224.4" r=".4" fill="#000" stroke="#000" stroke-width=".13"/>
<path d="M47.9 189h12.4v14.2h-12.4z" fill-rule="evenodd" fill="#fff" stroke="#000" stroke-width=".13"/>
<g fill="none" stroke="#000" stroke-width=".13">
<path d="M102.9 77.1h1.3a.68 .68 0 0 1 .7-.6 .68 .68 0 0 1 .7 .6M105.6 77.1a.66 .66 0 0 1 .7-.6 .66 .66 0 0 1 .6 .6M107 77.1a.68 .68 0 0 1 .6-.6 .68 .68 0 0 1 .7 .6M108.4 77.1a.66 .66 0 0 1 .6-.6 .66 .66 0 0 1 .7 .6M109.7 77.1h1.4M109.7 65.8h1.4M111.1 65.1v1.4M111.1 72.1v1.5M111.1 72.9h1.4M113.8 77.1h1.7M115.5 75.8v2.6M116.1 77.1h1.9"/>
<path d="M116.1 75.8v2.6M119.3 77.1h1.4M120.7 76.4v1.4M111.1 89.8h1.4M112.5 89.2v1.4M118.1 117.2h2.4M118.1 117.9h2.4M119.3 115.4v1.8M119.3 117.9v1.7M122.1 112.5h1.3M123.4 111.8v1.4M54.8 122.4h1.4"/>
<path d="M56.2 121.7v1.5M94.6 135.2h1.4M96 134.5v1.4M102.8 135.2h1.4M104.2 134.5v1.4M128.2 136.6h1.4v4.2h-1.4zM128.9 135.2v1.4M116.6 143.7h1.7M118.3 142.4v2.6M119 143.7h1.7M119 142.4v2.6M128.9 149.3h2.8v4.3h-23.3"/>
<path d="M128.9 140.8v1.4M131.7 143.7h1.3M131.7 149.3h2.7M133 143h4.2v1.4h-4.2zM137.2 143.7h1.3M144.7 149.3h1.4M146.1 148.6v1.4M43.8 177.6h16.5v2.9h16.5M49.3 177.6v11.4M68.5 174.2h1.4M69.9 173.5v1.5M75.4 162.1h1.4"/>
<path d="M76.8 161.4v1.4M126.2 179.1h11v4.2M137.2 179.1h1.3M142.6 174.8h-10.9v1.4h-2.8M142.6 174.1v1.4M41 190.4h1.4M42.4 189.7v1.4M43.8 198.9h4.1M43.8 197.5h4.1M43.8 194.7h4.1M43.8 193.2h4.1M43.8 181.9h33"/>
<path d="M58.9 181.9v7.1M60.3 198.9h4.1M60.3 197.5h4.1M60.3 194.7h4.1M60.3 193.2h4.1M65.8 189h1.4M67.2 188.3v1.4M75.4 194.7h1.4M76.8 193.9v1.5M133 187.6v2.8h13.8M137.2 187.6v2.8M146.8 189.7v1.4"/>
<path d="M49.3 203.2v4.2M58.9 203.2v4.2M87.3 204.6h1.8M100.1 204.6v28.3h-4.1M100.1 217.3h1.6M101.5 204.6v8.5h2.7v4.2M101.7 216v2.6M102.4 216v2.6M102.4 217.3h1.8M102.8 204.6v7h2.8v5.7h2.8M104.2 217.3v5.7h-1.8M105.6 204.6v4.2h19.2v18.4"/>
<path d="M108.4 204.6v1.4h23.3v25.5M108.4 216.6v1.4M117.2 217.3h1.4v4.2h-1.4zM118 215.9v1.4M122.1 213.1h1.3M123.4 212.3v1.4M127.6 215.9h1.3M128.9 215.2v1.4M80.9 221.5h1.3M82.2 220.9h4.2v1.4h-4.2zM86.4 221.5h1.3M100.1 223h1.6"/>
<path d="M101.7 221.7v2.5M102.4 221.7v2.5M109 225.8h1.4v4.2h-1.4zM109.7 230v1.5M109.7 224.4v1.4M118 221.5v1.5"/>
<circle cx="87" cy="204.6" r=".26"/>
</g>
<path d="M87.7 163.5h28.9v29.7h-28.9z" fill-rule="evenodd" fill="#fff" stroke="#000" stroke-width=".13"/>
<g fill="none" stroke="#000" stroke-width=".13">
<path d="M118 77.1h1.3M49.3 135.2v-2.9h57.7v7.1h-2.8v24.1M53.4 122.4h-4.1v2.9M57.6 132.3v2.9M61.7 129.5v2.8M89.1 132.3v12.8h6.9v18.4M94.6 135.2v8.5h2.7v19.8M102.8 135.2v28.3M49.3 152.1h2.7M49.3 145.1h16.5v25.5h21.9M49.3 147.9h4.4M49.3 143.7v9.9"/>
<path d="M53.7 146.6v2.6M54.4 147.9h3.2M54.4 146.6v2.6M56.2 152.1h1.4M57.6 146.5h6.8v25.5h23.3M57.6 143.7v9.9M94.6 159.3v4.2M98.7 153.6v9.9M100.1 153.6v9.9M101.5 153.6v9.9M105.1 158.7l1.1 1.1M105.6 159.3v4.2"/>
<path d="M106.2 158.7l-1.1 1.1M107 153.6v9.9M108.4 153.6v9.9M109.7 159.3v4.2M131.7 153.6h4.1M135.8 152.2h.4v2.8h-.4zM136.6 152.2h.2v2.8h-.2zM138.5 149.3h6.2M141.3 149.3v4.3h-4.5M76.8 179.1h10.9M76.8 177.6h10.9M76.8 176.2h10.9"/>
<path d="M76.8 174.8h10.9M76.8 173.4h10.9M116.6 179.1h9.6M116.6 176.2h9.6M116.6 174.8h9.6M116.6 173.4h9.6M120.7 167.7v2.9h-4.1M124.8 167.7v4.3h-8.2M138.5 174.8v2.8h-21.9M76.8 186.1h10.9M76.8 184.7h10.9M76.8 183.3h10.9"/>
<path d="M76.8 181.9h10.9M76.8 180.5h10.9M94.6 193.2v11.4h-5.5M96 193.2v11.4M97.3 193.2v11.4M98.7 193.2v4.3M100.1 193.2v11.4M101.5 193.2v11.4M102.8 193.2v11.4M104.2 193.2v11.4M105.6 193.2v11.4M107 193.2v11.4"/>
<path d="M108.4 193.2v11.4M109.2 196.9l1.1 1.1M109.7 193.2v4.3M110.3 196.9l-1.1 1.1M116.6 184.7h6.8v18.5h11v28.3M116.6 183.3h8.2v18.4h12.4v28.3M116.6 181.9h9.6v18.4h13.7v26.9M116.6 180.5h11v18.4h15v28.3M116.6 186.1h4.1M120.1 185.6l1.1 1.1M121.2 185.6l-1.1 1.1"/>
</g>
<circle cx="89.8" cy="191.1" r=".68" fill="#000" stroke="#000" stroke-width=".13"/>
<path d="M124.8 119.6h8.2v11.3h-8.2z" fill-rule="evenodd" fill="#fff" stroke="#000" stroke-width=".13"/>
<g fill="none" stroke="#000" stroke-width=".13">
<path d="M100.1 81.4v4.2M100.1 95.5v4.3M104.2 94.1h4.2M104.2 92.7h4.2M104.2 91.3h4.2M104.2 89.8h4.2M104.2 88.4h4.2M119.3 119.6v5.7M118 125.3h6.8M128.9 130.9v4.3M133 123.8h4.2v2.9h-4.2M137.2 125.3h6.8"/>
<path d="M144 124.5v1.4M120.7 143.7h11M128.9 142.2v1.5M138.5 143.7h5.5M144 143v1.4"/>
</g>
<path d="M96 85.6h8.2v9.9h-8.2z" fill-rule="evenodd" fill="#fff" stroke="#000" stroke-width=".13"/>
<g fill="none" stroke="#000" stroke-width=".13">
<path d="M97.3 63h5.6v5.6h-5.6zM98.3 63.6a2.76 2.76 0 0 1 3.8 .4 2.76 2.76 0 0 1 0 3.7 2.76 2.76 0 0 1-3.8 .3 2.87 2.87 0 0 1 0-4.4zM100.1 63v-1.5h8.3v2.9M100.1 66.2v15.2M102.9 65.8h6.8M102.9 64.4h5.5M108.4 64.4v2.8h-5.5M111.1 77.1h2.7M112.5 72.9v4.2M100.1 99.8v45.3M104.2 87h4.2v7.1M108.4 89.8h2.7"/>
<path d="M113.8 117.2h2.8v.1h-2.8zM113.8 117.7h2.8v.5h-2.8zM115.2 118.2v2.8h4.1M119.3 112.5h-4.1v4.7M49.3 129.5v2.8M53.4 129.5v2.8M109.7 125.3h1.4M111.1 124.5h4.1v1.4h-4.1zM115.2 125.3h2.8M94 158.7l1.1 1.1M95.1 158.7l-1.1 1.1M109.2 158.7l1.1 1.1"/>
<path d="M110.3 158.7l-1.1 1.1M126.2 174.8h1.4v-2.8h21.9v59.6M43.8 193.2v5.7M98.2 196.9l1.1 1.1M99.3 196.9l-1.1 1.1M49.3 211.6h1.4M89.1 224.4h3M92.1 223.1v2.5M92.8 224.4h1.8M92.8 223.1v2.5"/>
<circle cx="100.1" cy="65.9" r=".4"/>
</g>
<path d="M52.5 192.1h3v8.5h-3z" fill-rule="evenodd" fill="#fff" stroke="#fff" stroke-width=".13"/>
<g fill="#000" stroke="#000" stroke-width=".13">
<path d="M128.7 176.1l.2-.1 .1 .1 .1 .2-.1 .2-.1 .1-.2-.1v-.2z" fill-rule="evenodd"/>
<circle cx="100.1" cy="77.1" r=".25"/>
<circle cx="108.3" cy="65.8" r=".25"/>
<circle cx="108.3" cy="64.4" r=".25"/>
<circle cx="112.5" cy="77.1" r=".25"/>
<circle cx="108.3" cy="92.7" r=".25"/>
<circle cx="108.3" cy="89.9" r=".25"/>
<circle cx="108.3" cy="88.5" r=".27"/>
<circle cx="108.3" cy="91.3" r=".27"/>
<circle cx="119.3" cy="112.5" r=".25"/>
<circle cx="49.3" cy="132.4" r=".27"/>
<circle cx="53.4" cy="132.4" r=".27"/>
<circle cx="53.4" cy="122.5" r=".27"/>
<circle cx="57.5" cy="132.4" r=".27"/>
<circle cx="61.6" cy="132.4" r=".27"/>
<circle cx="89.1" cy="132.4" r=".27"/>
<circle cx="119.3" cy="121.1" r=".25"/>
<circle cx="119.3" cy="125.3" r=".25"/>
<circle cx="137.2" cy="125.3" r=".25"/>
<circle cx="49.3" cy="147.9" r=".27"/>
<circle cx="49.3" cy="145.1" r=".27"/>
<circle cx="49.3" cy="159.2" r=".25"/>
<circle cx="49.3" cy="152.2" r=".25"/>
<circle cx="57.5" cy="159.2" r=".25"/>
<circle cx="57.5" cy="152.2" r=".25"/>
<circle cx="57.5" cy="146.5" r=".25"/>
<circle cx="57.5" cy="147.9" r=".27"/>
<circle cx="94.6" cy="140.9" r=".25"/>
<circle cx="97.4" cy="152.2" r=".25"/>
<circle cx="100.1" cy="140.9" r=".25"/>
<circle cx="128.9" cy="143.7" r=".24"/>
<circle cx="131.7" cy="153.6" r=".25"/>
<circle cx="131.7" cy="149.3" r=".25"/>
<circle cx="141.2" cy="149.3" r=".25"/>
<circle cx="34.2" cy="177.7" r=".25"/>
<circle cx="45.1" cy="174.8" r=".25"/>
<circle cx="49.3" cy="163.5" r=".27"/>
<circle cx="49.3" cy="177.7" r=".25"/>
<circle cx="49.3" cy="167.8" r=".25"/>
<circle cx="57.5" cy="167.8" r=".25"/>
<circle cx="57.5" cy="163.5" r=".27"/>
<circle cx="72.6" cy="173.4" r=".27"/>
<circle cx="72.6" cy="179.1" r=".27"/>
<circle cx="75.4" cy="177.7" r=".25"/>
<circle cx="133" cy="179.1" r=".27"/>
<circle cx="137.1" cy="179.1" r=".27"/>
<circle cx="138.5" cy="174.8" r=".25"/>
<circle cx="43.8" cy="196.1" r=".25"/>
<circle cx="43.8" cy="197.5" r=".25"/>
<circle cx="43.8" cy="194.7" r=".27"/>
<circle cx="58.9" cy="181.9" r=".25"/>
<circle cx="64.4" cy="197.5" r=".25"/>
<circle cx="64.4" cy="193.3" r=".25"/>
<circle cx="64.4" cy="194.7" r=".27"/>
<circle cx="72.7" cy="183.4" r=".25"/>
<circle cx="137.2" cy="190.4" r=".25"/>
<circle cx="49.3" cy="211.6" r=".25"/>
<circle cx="58.9" cy="211.6" r=".25"/>
<circle cx="100.1" cy="217.3" r=".27"/>
<circle cx="104.2" cy="217.3" r=".27"/>
<circle cx="120.7" cy="213.1" r=".25"/>
<circle cx="89.1" cy="224.4" r=".25"/>
<circle cx="100.1" cy="223" r=".27"/>
<circle cx="113.8" cy="224.4" r=".25"/>
<circle cx="113.8" cy="223" r=".27"/>
</g>
<circle cx="102.8" cy="152.2" r=".25" fill="#a06e56" stroke="#a06e56" stroke-width=".13"/>
<use href="#words"/>
</svg>
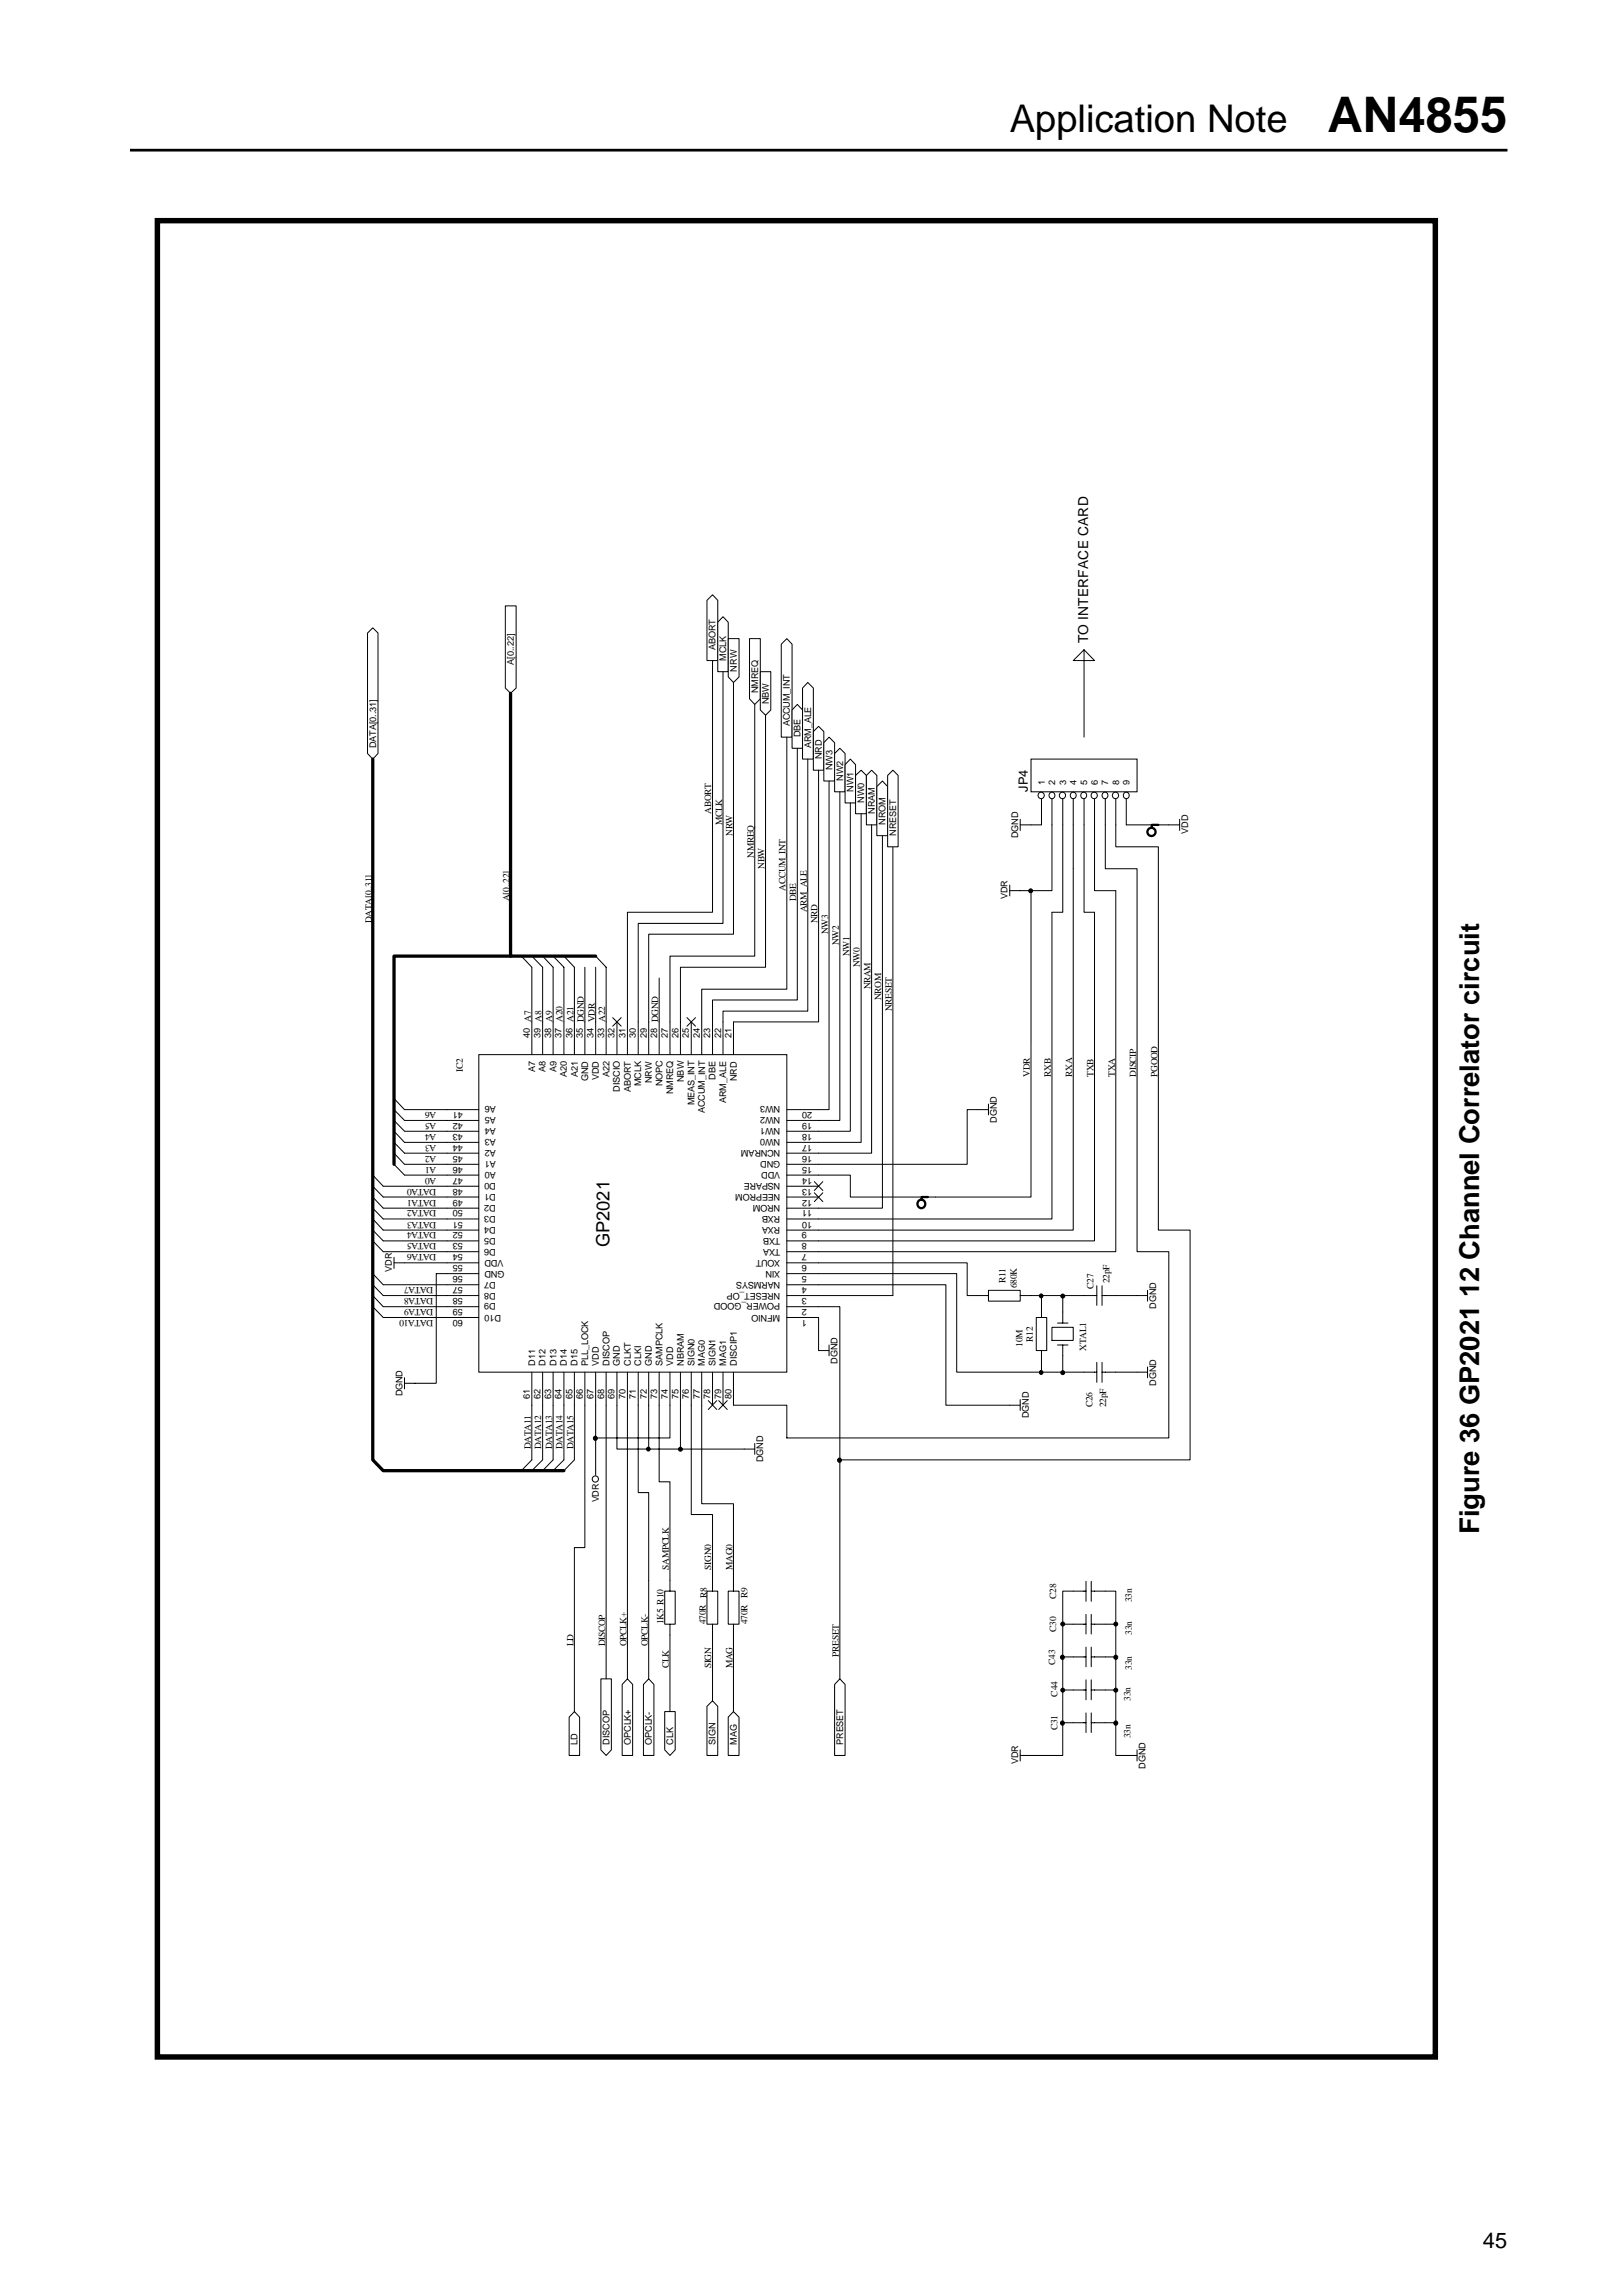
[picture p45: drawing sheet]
<svg xmlns="http://www.w3.org/2000/svg" width="210mm" height="297mm" viewBox="0 0 210 297" stroke-linecap="round" stroke-linejoin="round" font-family="sans-serif">
<defs><g id="words">
<text font-size="6.3" x="171.7" y="17.1">AN4855</text>
<text font-size="4.9" x="130.6" y="17.1">Application Note</text>
<text font-size="3.5" x="191.3" y="198.4" transform="rotate(-90 191.3 198.4)">Figure 36 GP2021 12 Channel Correlator circuit</text>
<text font-size="2.8" x="191.8" y="290.7">45</text>
<text font-size="2.4" x="78.8" y="161.3" transform="rotate(-90 78.8 161.3)">GP2021</text>
<text font-size="1.8" x="140.8" y="83.2" transform="rotate(-90 140.8 83.2)">TO INTERFACE CARD</text>
<text font-size="1.7" x="132.9" y="102.4" transform="rotate(-90 132.9 102.4)">JP4</text>
<g font-size="1.2">
<text x="66.5" y="86" transform="rotate(-90 66.5 86)">A[0..22]</text>
<text x="92.5" y="84" transform="rotate(-90 92.5 84)">ABORT</text>
<text x="93.9" y="85.4" transform="rotate(-90 93.9 85.4)">MCLK</text>
<text x="95.3" y="86.9" transform="rotate(-90 95.3 86.9)">NRW</text>
<text x="98" y="89.7" transform="rotate(-90 98 89.7)">NMREQ</text>
<text x="99.4" y="91.1" transform="rotate(-90 99.4 91.1)">NBW</text>
<text x="102.1" y="93.9" transform="rotate(-90 102.1 93.9)">ACCUM_INT</text>
<text x="103.5" y="95.3" transform="rotate(-90 103.5 95.3)">DBE</text>
<text x="48.6" y="96.8" transform="rotate(-90 48.6 96.8)">DATA[0..31]</text>
<text x="104.9" y="96.8" transform="rotate(-90 104.9 96.8)">ARM_ALE</text>
<text x="106.3" y="98.2" transform="rotate(-90 106.3 98.2)">NRD</text>
<text x="107.6" y="99.6" transform="rotate(-90 107.6 99.6)">NW3</text>
<text x="109" y="101" transform="rotate(-90 109 101)">NW2</text>
<text x="135.1" y="101.6" transform="rotate(-90 135.1 101.6)">1</text>
<text x="136.5" y="101.6" transform="rotate(-90 136.5 101.6)">2</text>
<text x="137.9" y="101.6" transform="rotate(-90 137.9 101.6)">3</text>
<text x="139.2" y="101.6" transform="rotate(-90 139.2 101.6)">4</text>
<text x="140.6" y="101.6" transform="rotate(-90 140.6 101.6)">5</text>
<text x="142" y="101.6" transform="rotate(-90 142 101.6)">6</text>
<text x="143.3" y="101.6" transform="rotate(-90 143.3 101.6)">7</text>
<text x="144.7" y="101.6" transform="rotate(-90 144.7 101.6)">8</text>
<text x="146.1" y="101.6" transform="rotate(-90 146.1 101.6)">9</text>
<text x="92" y="105.2" transform="rotate(-90 92 105.2)">ABORT</text>
<text x="93.4" y="106.7" transform="rotate(-90 93.4 106.7)">MCLK</text>
<text x="110.4" y="102.4" transform="rotate(-90 110.4 102.4)">NW1</text>
<text x="111.8" y="103.8" transform="rotate(-90 111.8 103.8)">NW0</text>
<text x="113.1" y="105.2" transform="rotate(-90 113.1 105.2)">NRAM</text>
<text x="114.5" y="106.7" transform="rotate(-90 114.5 106.7)">NROM</text>
<text x="153.7" y="107.8" transform="rotate(-90 153.7 107.8)">VDD</text>
<text x="94.7" y="108.1" transform="rotate(-90 94.7 108.1)">NRW</text>
<text x="97.5" y="110.9" transform="rotate(-90 97.5 110.9)">NMREQ</text>
<text x="98.9" y="112.4" transform="rotate(-90 98.9 112.4)">NBW</text>
<text x="115.9" y="108.1" transform="rotate(-90 115.9 108.1)">NRESET</text>
<text x="131.7" y="108.4" transform="rotate(-90 131.7 108.4)">DGND</text>
<text x="48.1" y="119.4" transform="rotate(-90 48.1 119.4)">DATA[0..31]</text>
<text x="65.9" y="116.6" transform="rotate(-90 65.9 116.6)">A[0..22]</text>
<text x="101.6" y="115.2" transform="rotate(-90 101.6 115.2)">ACCUM_INT</text>
<text x="103" y="116.6" transform="rotate(-90 103 116.6)">DBE</text>
<text x="104.3" y="118" transform="rotate(-90 104.3 118)">ARM_ALE</text>
<text x="105.7" y="119.4" transform="rotate(-90 105.7 119.4)">NRD</text>
<text x="130.3" y="116.3" transform="rotate(-90 130.3 116.3)">VDR</text>
<text x="107.1" y="120.8" transform="rotate(-90 107.1 120.8)">NW3</text>
<text x="108.5" y="122.3" transform="rotate(-90 108.5 122.3)">NW2</text>
<text x="109.8" y="123.7" transform="rotate(-90 109.8 123.7)">NW1</text>
<text x="111.2" y="125.1" transform="rotate(-90 111.2 125.1)">NW0</text>
<text x="112.6" y="127.9" transform="rotate(-90 112.6 127.9)">NRAM</text>
<text x="114" y="129.3" transform="rotate(-90 114 129.3)">NROM</text>
<text x="115.4" y="130.8" transform="rotate(-90 115.4 130.8)">NRESET</text>
<text x="68.5" y="134.3" transform="rotate(-90 68.5 134.3)">40 A7</text>
<text x="69.9" y="134.3" transform="rotate(-90 69.9 134.3)">39 A8</text>
<text x="71.3" y="134.3" transform="rotate(-90 71.3 134.3)">38 A9</text>
<text x="72.6" y="134.3" transform="rotate(-90 72.6 134.3)">37 A20</text>
<text x="74" y="134.3" transform="rotate(-90 74 134.3)">36 A21</text>
<text x="75.4" y="134.3" transform="rotate(-90 75.4 134.3)">35 DGND</text>
<text x="76.7" y="134.3" transform="rotate(-90 76.7 134.3)">34 VDR</text>
<text x="78.1" y="134.3" transform="rotate(-90 78.1 134.3)">33 A22</text>
<text x="79.5" y="134.3" transform="rotate(-90 79.5 134.3)">32</text>
<text x="80.9" y="134.3" transform="rotate(-90 80.9 134.3)">31</text>
<text x="82.2" y="134.3" transform="rotate(-90 82.2 134.3)">30</text>
<text x="83.6" y="134.3" transform="rotate(-90 83.6 134.3)">29</text>
<text x="85" y="134.3" transform="rotate(-90 85 134.3)">28 DGND</text>
<text x="86.4" y="134.3" transform="rotate(-90 86.4 134.3)">27</text>
<text x="87.7" y="134.3" transform="rotate(-90 87.7 134.3)">26</text>
<text x="89.1" y="134.3" transform="rotate(-90 89.1 134.3)">25</text>
<text x="90.5" y="134.3" transform="rotate(-90 90.5 134.3)">24</text>
<text x="91.9" y="134.3" transform="rotate(-90 91.9 134.3)">23</text>
<text x="93.3" y="134.3" transform="rotate(-90 93.3 134.3)">22</text>
<text x="94.6" y="134.3" transform="rotate(-90 94.6 134.3)">21</text>
<text x="56.4" y="143.8" transform="rotate(-180 56.4 143.8)">A6</text>
<text x="59.9" y="143.8" transform="rotate(-180 59.9 143.8)">41</text>
<text x="59.9" y="138.7" transform="rotate(-90 59.9 138.7)">IC2</text>
<text x="64.1" y="143.1" transform="rotate(-180 64.1 143.1)">A6</text>
<text x="69.2" y="138.7" transform="rotate(-90 69.2 138.7)">A7</text>
<text x="70.6" y="138.7" transform="rotate(-90 70.6 138.7)">A8</text>
<text x="72" y="138.7" transform="rotate(-90 72 138.7)">A9</text>
<text x="73.3" y="139.2" transform="rotate(-90 73.3 139.2)">A20</text>
<text x="74.7" y="139.2" transform="rotate(-90 74.7 139.2)">A21</text>
<text x="76.1" y="139.8" transform="rotate(-90 76.1 139.8)">GND</text>
<text x="77.5" y="139.7" transform="rotate(-90 77.5 139.7)">VDD</text>
<text x="78.8" y="139.2" transform="rotate(-90 78.8 139.2)">A22</text>
<text x="80.2" y="141.2" transform="rotate(-90 80.2 141.2)">DISCIO</text>
<text x="81.6" y="141.2" transform="rotate(-90 81.6 141.2)">ABORT</text>
<text x="82.9" y="140.5" transform="rotate(-90 82.9 140.5)">MCLK</text>
<text x="84.3" y="140.1" transform="rotate(-90 84.3 140.1)">NRW</text>
<text x="85.7" y="140.5" transform="rotate(-90 85.7 140.5)">NOPC</text>
<text x="87.1" y="141.5" transform="rotate(-90 87.1 141.5)">NMREQ</text>
<text x="88.4" y="140" transform="rotate(-90 88.4 140)">NBW</text>
<text x="89.8" y="142.9" transform="rotate(-90 89.8 142.9)">MEAS_INT</text>
<text x="91.2" y="143.9" transform="rotate(-90 91.2 143.9)">ACCUM_INT</text>
<text x="92.5" y="139.7" transform="rotate(-90 92.5 139.7)">DBE</text>
<text x="93.9" y="142.7" transform="rotate(-90 93.9 142.7)">ARM_ALE</text>
<text x="95.3" y="139.8" transform="rotate(-90 95.3 139.8)">NRD</text>
<text x="100.9" y="143.1" transform="rotate(-180 100.9 143.1)">NW3</text>
<text x="105" y="143.8" transform="rotate(-180 105 143.8)">20</text>
<text x="133.2" y="139.2" transform="rotate(-90 133.2 139.2)">VDR</text>
<text x="135.9" y="139.2" transform="rotate(-90 135.9 139.2)">RXB</text>
<text x="138.7" y="139.2" transform="rotate(-90 138.7 139.2)">RXA</text>
<text x="141.4" y="139.2" transform="rotate(-90 141.4 139.2)">TXB</text>
<text x="144.2" y="139.2" transform="rotate(-90 144.2 139.2)">TXA</text>
<text x="146.9" y="139.2" transform="rotate(-90 146.9 139.2)">DISCIP</text>
<text x="149.7" y="139.2" transform="rotate(-90 149.7 139.2)">PGOOD</text>
<text x="56.4" y="149.5" transform="rotate(-180 56.4 149.5)">A2</text>
<text x="56.4" y="148" transform="rotate(-180 56.4 148)">A3</text>
<text x="56.4" y="146.6" transform="rotate(-180 56.4 146.6)">A4</text>
<text x="56.4" y="145.2" transform="rotate(-180 56.4 145.2)">A5</text>
<text x="59.9" y="148" transform="rotate(-180 59.9 148)">44</text>
<text x="59.9" y="149.5" transform="rotate(-180 59.9 149.5)">45</text>
<text x="59.9" y="146.6" transform="rotate(-180 59.9 146.6)">43</text>
<text x="59.9" y="145.2" transform="rotate(-180 59.9 145.2)">42</text>
<text x="64.1" y="147.4" transform="rotate(-180 64.1 147.4)">A3</text>
<text x="64.1" y="148.8" transform="rotate(-180 64.1 148.8)">A2</text>
<text x="64.1" y="145.9" transform="rotate(-180 64.1 145.9)">A4</text>
<text x="64.1" y="144.5" transform="rotate(-180 64.1 144.5)">A5</text>
<text x="100.9" y="148.8" transform="rotate(-180 100.9 148.8)">NCNRAM</text>
<text x="100.9" y="147.4" transform="rotate(-180 100.9 147.4)">NW0</text>
<text x="100.9" y="145.9" transform="rotate(-180 100.9 145.9)">NW1</text>
<text x="100.9" y="144.5" transform="rotate(-180 100.9 144.5)">NW2</text>
<text x="105" y="149.5" transform="rotate(-180 105 149.5)">16</text>
<text x="105" y="148" transform="rotate(-180 105 148)">17</text>
<text x="105" y="146.6" transform="rotate(-180 105 146.6)">18</text>
<text x="105" y="145.2" transform="rotate(-180 105 145.2)">19</text>
<text x="128.9" y="145.2" transform="rotate(-90 128.9 145.2)">DGND</text>
<text x="56.4" y="155.2" transform="rotate(-180 56.4 155.2)">DATA1</text>
<text x="56.4" y="153.7" transform="rotate(-180 56.4 153.7)">DATA0</text>
<text x="56.4" y="152.3" transform="rotate(-180 56.4 152.3)">A0</text>
<text x="56.4" y="150.9" transform="rotate(-180 56.4 150.9)">A1</text>
<text x="59.9" y="155.2" transform="rotate(-180 59.9 155.2)">49</text>
<text x="59.9" y="153.7" transform="rotate(-180 59.9 153.7)">48</text>
<text x="59.9" y="150.9" transform="rotate(-180 59.9 150.9)">46</text>
<text x="59.9" y="152.3" transform="rotate(-180 59.9 152.3)">47</text>
<text x="64.1" y="155.8" transform="rotate(-180 64.1 155.8)">D2</text>
<text x="64.1" y="153" transform="rotate(-180 64.1 153)">D0</text>
<text x="64.1" y="154.4" transform="rotate(-180 64.1 154.4)">D1</text>
<text x="64.1" y="150.2" transform="rotate(-180 64.1 150.2)">A1</text>
<text x="64.1" y="151.6" transform="rotate(-180 64.1 151.6)">A0</text>
<text x="100.9" y="155.8" transform="rotate(-180 100.9 155.8)">NROM</text>
<text x="100.9" y="154.4" transform="rotate(-180 100.9 154.4)">NEEPROM</text>
<text x="100.9" y="153" transform="rotate(-180 100.9 153)">NSPARE</text>
<text x="100.9" y="151.6" transform="rotate(-180 100.9 151.6)">VDD</text>
<text x="100.9" y="150.2" transform="rotate(-180 100.9 150.2)">GND</text>
<text x="105" y="155.2" transform="rotate(-180 105 155.2)">12</text>
<text x="105" y="153.7" transform="rotate(-180 105 153.7)">13</text>
<text x="105" y="152.3" transform="rotate(-180 105 152.3)">14</text>
<text x="105" y="150.9" transform="rotate(-180 105 150.9)">15</text>
<text x="56.4" y="160.8" transform="rotate(-180 56.4 160.8)">DATA5</text>
<text x="56.4" y="158" transform="rotate(-180 56.4 158)">DATA3</text>
<text x="56.4" y="159.4" transform="rotate(-180 56.4 159.4)">DATA4</text>
<text x="56.4" y="156.5" transform="rotate(-180 56.4 156.5)">DATA2</text>
<text x="59.9" y="159.4" transform="rotate(-180 59.9 159.4)">52</text>
<text x="59.9" y="160.8" transform="rotate(-180 59.9 160.8)">53</text>
<text x="59.9" y="156.5" transform="rotate(-180 59.9 156.5)">50</text>
<text x="59.9" y="158" transform="rotate(-180 59.9 158)">51</text>
<text x="64.1" y="160.1" transform="rotate(-180 64.1 160.1)">D5</text>
<text x="64.1" y="161.5" transform="rotate(-180 64.1 161.5)">D6</text>
<text x="64.1" y="157.3" transform="rotate(-180 64.1 157.3)">D3</text>
<text x="64.1" y="158.7" transform="rotate(-180 64.1 158.7)">D4</text>
<text x="100.9" y="161.5" transform="rotate(-180 100.9 161.5)">TXA</text>
<text x="100.9" y="160.1" transform="rotate(-180 100.9 160.1)">TXB</text>
<text x="100.9" y="158.7" transform="rotate(-180 100.9 158.7)">RXA</text>
<text x="100.9" y="157.3" transform="rotate(-180 100.9 157.3)">RXB</text>
<text x="104.3" y="160.8" transform="rotate(-180 104.3 160.8)">8</text>
<text x="104.3" y="159.4" transform="rotate(-180 104.3 159.4)">9</text>
<text x="105" y="158" transform="rotate(-180 105 158)">10</text>
<text x="105" y="156.6" transform="rotate(-180 105 156.6)">11</text>
<text x="50.7" y="164.5" transform="rotate(-90 50.7 164.5)">VDR</text>
<text x="56" y="167.9" transform="rotate(-180 56 167.9)">DATA8</text>
<text x="56" y="166.5" transform="rotate(-180 56 166.5)">DATA7</text>
<text x="56.4" y="162.2" transform="rotate(-180 56.4 162.2)">DATA6</text>
<text x="59.9" y="166.5" transform="rotate(-180 59.9 166.5)">57</text>
<text x="59.9" y="167.9" transform="rotate(-180 59.9 167.9)">58</text>
<text x="59.9" y="163.6" transform="rotate(-180 59.9 163.6)">55</text>
<text x="59.9" y="165.1" transform="rotate(-180 59.9 165.1)">56</text>
<text x="59.9" y="162.2" transform="rotate(-180 59.9 162.2)">54</text>
<text x="64.1" y="167.2" transform="rotate(-180 64.1 167.2)">D8</text>
<text x="64.1" y="165.8" transform="rotate(-180 64.1 165.8)">D7</text>
<text x="65.1" y="162.9" transform="rotate(-180 65.1 162.9)">VDD</text>
<text x="65.2" y="164.3" transform="rotate(-180 65.2 164.3)">GND</text>
<text x="100.9" y="167.2" transform="rotate(-180 100.9 167.2)">NRESET_OP</text>
<text x="100.9" y="165.8" transform="rotate(-180 100.9 165.8)">NARMSYS</text>
<text x="100.9" y="164.3" transform="rotate(-180 100.9 164.3)">XIN</text>
<text x="100.9" y="162.9" transform="rotate(-180 100.9 162.9)">XOUT</text>
<text x="104.3" y="167.9" transform="rotate(-180 104.3 167.9)">3</text>
<text x="104.3" y="166.5" transform="rotate(-180 104.3 166.5)">4</text>
<text x="104.3" y="165.1" transform="rotate(-180 104.3 165.1)">5</text>
<text x="104.3" y="163.6" transform="rotate(-180 104.3 163.6)">6</text>
<text x="104.3" y="162.2" transform="rotate(-180 104.3 162.2)">7</text>
<text x="130" y="166" transform="rotate(-90 130 166)">R11</text>
<text x="131.5" y="166.6" transform="rotate(-90 131.5 166.6)">680K</text>
<text x="141.4" y="166.7" transform="rotate(-90 141.4 166.7)">C27</text>
<text x="143.5" y="166" transform="rotate(-90 143.5 166)">22pF</text>
<text x="56" y="170.7" transform="rotate(-180 56 170.7)">DATA10</text>
<text x="56" y="169.3" transform="rotate(-180 56 169.3)">DATA9</text>
<text x="59.8" y="170.7" transform="rotate(-180 59.8 170.7)">60</text>
<text x="59.9" y="169.3" transform="rotate(-180 59.9 169.3)">59</text>
<text x="64.1" y="168.6" transform="rotate(-180 64.1 168.6)">D9</text>
<text x="64.8" y="170" transform="rotate(-180 64.8 170)">D10</text>
<text x="100.9" y="170" transform="rotate(-180 100.9 170)">MFNIO</text>
<text x="100.9" y="168.6" transform="rotate(-180 100.9 168.6)">POWER_GOOD</text>
<text x="104.3" y="170.7" transform="rotate(-180 104.3 170.7)">1</text>
<text x="104.3" y="169.3" transform="rotate(-180 104.3 169.3)">2</text>
<text x="133.6" y="173.5" transform="rotate(-90 133.6 173.5)">R12</text>
<text x="149.5" y="169.3" transform="rotate(-90 149.5 169.3)">DGND</text>
<text x="69.2" y="176.6" transform="rotate(-90 69.2 176.6)">D11</text>
<text x="70.6" y="176.6" transform="rotate(-90 70.6 176.6)">D12</text>
<text x="72" y="176.6" transform="rotate(-90 72 176.6)">D13</text>
<text x="73.3" y="176.6" transform="rotate(-90 73.3 176.6)">D14</text>
<text x="74.7" y="176.6" transform="rotate(-90 74.7 176.6)">D15</text>
<text x="76.1" y="176.6" transform="rotate(-90 76.1 176.6)">PLL_LOCK</text>
<text x="77.5" y="176.6" transform="rotate(-90 77.5 176.6)">VDD</text>
<text x="78.8" y="176.6" transform="rotate(-90 78.8 176.6)">DISCOP</text>
<text x="80.2" y="176.6" transform="rotate(-90 80.2 176.6)">GND</text>
<text x="81.6" y="176.6" transform="rotate(-90 81.6 176.6)">CLKT</text>
<text x="82.9" y="176.6" transform="rotate(-90 82.9 176.6)">CLKI</text>
<text x="84.3" y="176.6" transform="rotate(-90 84.3 176.6)">GND</text>
<text x="85.7" y="176.6" transform="rotate(-90 85.7 176.6)">SAMPCLK</text>
<text x="87.1" y="176.6" transform="rotate(-90 87.1 176.6)">VDD</text>
<text x="88.4" y="176.6" transform="rotate(-90 88.4 176.6)">NBRAM</text>
<text x="89.8" y="176.6" transform="rotate(-90 89.8 176.6)">SIGN0</text>
<text x="91.2" y="176.6" transform="rotate(-90 91.2 176.6)">MAG0</text>
<text x="92.5" y="176.6" transform="rotate(-90 92.5 176.6)">SIGN1</text>
<text x="93.9" y="176.6" transform="rotate(-90 93.9 176.6)">MAG1</text>
<text x="95.3" y="176.6" transform="rotate(-90 95.3 176.6)">DISCIP1</text>
<text x="108.3" y="176.4" transform="rotate(-90 108.3 176.4)">DGND</text>
<text x="132.2" y="174.2" transform="rotate(-90 132.2 174.2)">10M</text>
<text x="140.5" y="174.7" transform="rotate(-90 140.5 174.7)">XTAL1</text>
<text x="149.5" y="179.2" transform="rotate(-90 149.5 179.2)">DGND</text>
<text x="52.1" y="180.6" transform="rotate(-90 52.1 180.6)">DGND</text>
<text x="68.5" y="180.9" transform="rotate(-90 68.5 180.9)">61</text>
<text x="69.9" y="180.9" transform="rotate(-90 69.9 180.9)">62</text>
<text x="71.3" y="180.9" transform="rotate(-90 71.3 180.9)">63</text>
<text x="72.6" y="180.9" transform="rotate(-90 72.6 180.9)">64</text>
<text x="74" y="180.9" transform="rotate(-90 74 180.9)">65</text>
<text x="75.4" y="180.9" transform="rotate(-90 75.4 180.9)">66</text>
<text x="76.7" y="180.9" transform="rotate(-90 76.7 180.9)">67</text>
<text x="78.1" y="180.9" transform="rotate(-90 78.1 180.9)">68</text>
<text x="79.5" y="180.9" transform="rotate(-90 79.5 180.9)">69</text>
<text x="80.9" y="180.9" transform="rotate(-90 80.9 180.9)">70</text>
<text x="82.2" y="180.9" transform="rotate(-90 82.2 180.9)">71</text>
<text x="83.6" y="180.9" transform="rotate(-90 83.6 180.9)">72</text>
<text x="85" y="180.9" transform="rotate(-90 85 180.9)">73</text>
<text x="86.4" y="180.9" transform="rotate(-90 86.4 180.9)">74</text>
<text x="87.7" y="180.9" transform="rotate(-90 87.7 180.9)">75</text>
<text x="89.1" y="180.9" transform="rotate(-90 89.1 180.9)">76</text>
<text x="90.5" y="180.9" transform="rotate(-90 90.5 180.9)">77</text>
<text x="91.9" y="180.9" transform="rotate(-90 91.9 180.9)">78</text>
<text x="93.3" y="180.9" transform="rotate(-90 93.3 180.9)">79</text>
<text x="94.6" y="180.9" transform="rotate(-90 94.6 180.9)">80</text>
<text x="133" y="183.4" transform="rotate(-90 133 183.4)">DGND</text>
<text x="141.3" y="182" transform="rotate(-90 141.3 182)">C26</text>
<text x="143.1" y="182" transform="rotate(-90 143.1 182)">22pF</text>
<text x="68.7" y="187.4" transform="rotate(-90 68.7 187.4)">DATA11</text>
<text x="70" y="187.4" transform="rotate(-90 70 187.4)">DATA12</text>
<text x="71.4" y="187.4" transform="rotate(-90 71.4 187.4)">DATA13</text>
<text x="72.8" y="187.4" transform="rotate(-90 72.8 187.4)">DATA14</text>
<text x="74.2" y="187.4" transform="rotate(-90 74.2 187.4)">DATA15</text>
<text x="98.7" y="189.1" transform="rotate(-90 98.7 189.1)">DGND</text>
<text x="77.5" y="194.3" transform="rotate(-90 77.5 194.3)">VDR</text>
<text x="86.5" y="203" transform="rotate(-90 86.5 203)">SAMPCLK</text>
<text x="92" y="203" transform="rotate(-90 92 203)">SIGN0</text>
<text x="94.7" y="203" transform="rotate(-90 94.7 203)">MAG0</text>
<text x="136.6" y="206.8" transform="rotate(-90 136.6 206.8)">C28</text>
<text x="146.4" y="207.2" transform="rotate(-90 146.4 207.2)">33n</text>
<text x="74.2" y="212.9" transform="rotate(-90 74.2 212.9)">LD</text>
<text x="78.3" y="212.9" transform="rotate(-90 78.3 212.9)">DISCOP</text>
<text x="81" y="212.9" transform="rotate(-90 81 212.9)">OPCLK+</text>
<text x="83.8" y="212.9" transform="rotate(-90 83.8 212.9)">OPCLK-</text>
<text x="85.8" y="210.1" transform="rotate(-90 85.8 210.1)">1K5 R10</text>
<text x="86.5" y="215.7" transform="rotate(-90 86.5 215.7)">CLK</text>
<text x="91.3" y="210.1" transform="rotate(-90 91.3 210.1)">470R R8</text>
<text x="92" y="215.7" transform="rotate(-90 92 215.7)">SIGN</text>
<text x="94.7" y="215.7" transform="rotate(-90 94.7 215.7)">MAG</text>
<text x="96.7" y="210.1" transform="rotate(-90 96.7 210.1)">470R R9</text>
<text x="108.5" y="214.3" transform="rotate(-90 108.5 214.3)">PRESET</text>
<text x="136.5" y="215.3" transform="rotate(-90 136.5 215.3)">C43</text>
<text x="136.6" y="211" transform="rotate(-90 136.6 211)">C30</text>
<text x="146.4" y="216" transform="rotate(-90 146.4 216)">33n</text>
<text x="146.4" y="211.5" transform="rotate(-90 146.4 211.5)">33n</text>
<text x="136.8" y="219.4" transform="rotate(-90 136.8 219.4)">C44</text>
<text x="146.2" y="220" transform="rotate(-90 146.2 220)">33n</text>
<text x="74.7" y="225.6" transform="rotate(-90 74.7 225.6)">LD</text>
<text x="78.8" y="225.6" transform="rotate(-90 78.8 225.6)">DISCOP</text>
<text x="81.6" y="225.6" transform="rotate(-90 81.6 225.6)">OPCLK+</text>
<text x="84.3" y="225.6" transform="rotate(-90 84.3 225.6)">OPCLK-</text>
<text x="87.1" y="225.6" transform="rotate(-90 87.1 225.6)">CLK</text>
<text x="92.5" y="225.6" transform="rotate(-90 92.5 225.6)">SIGN</text>
<text x="95.3" y="225.6" transform="rotate(-90 95.3 225.6)">MAG</text>
<text x="109" y="225.6" transform="rotate(-90 109 225.6)">PRESET</text>
<text x="136.8" y="223.8" transform="rotate(-90 136.8 223.8)">C31</text>
<text x="146.2" y="224.8" transform="rotate(-90 146.2 224.8)">33n</text>
<text x="131.7" y="228.2" transform="rotate(-90 131.7 228.2)">VDR</text>
<text x="148.2" y="228.7" transform="rotate(-90 148.2 228.7)">DGND</text>
</g>
</g></defs>
<path d="M16.8 19.4h178.2" fill="none" stroke="#000" stroke-width=".35"/>
<path d="M40.7 247.6h121.2v16.7h-121.2z" fill-rule="evenodd" fill="#fff"/>
<path d="M40.7 59.2h121.2v209.6h-121.2z" fill="#fff"/>
<path d="M153.8 73.8h5.7v6h-5.7z" fill-rule="evenodd" fill="#fff" stroke="#fff" stroke-width=".13"/>
<g fill="#fff" stroke="#000" stroke-width=".13">
<path d="M81.1 217.1l.7 .7v9.2h-1.3v-9.2z" fill-rule="evenodd"/>
<path d="M83.9 217.1l.7 .7v9.2h-1.4v-9.2z" fill-rule="evenodd"/>
<path d="M86 221.4h1.3v4.9l-.7 .7-.6-.7z" fill-rule="evenodd"/>
<path d="M91.4 220.7l.7-.7 .7 .7v6.3h-1.4z" fill-rule="evenodd"/>
<path d="M47.5 81.9l.7-.7 .7 .7v15.6l-.7 .7-.7-.7z" fill-rule="evenodd"/>
<path d="M108.6 217.1l.7 .7v9.2h-1.4v-9.2z" fill-rule="evenodd"/>
<path d="M74.3 221.4l.7 .7v4.9h-1.4v-4.9z" fill-rule="evenodd"/>
<path d="M94.9 221.4l.7 .7v4.9h-1.4v-4.9z" fill-rule="evenodd"/>
<path d="M65.4 78.4h1.4v10.6l-.8 .7-.6-.7z" fill-rule="evenodd"/>
<path d="M92.2 76.9l.6 .7v7.8h-1.4v-7.8z" fill-rule="evenodd"/>
<path d="M93.5 79.8l.7 .7v6.4h-1.4v-6.4z" fill-rule="evenodd"/>
<path d="M94.2 82.6h1.4v4.9l-.7 .8-.7-.8z" fill-rule="evenodd"/>
<path d="M96.9 82.6h1.4v7.8l-.7 .7-.7-.7z" fill-rule="evenodd"/>
<path d="M98.3 86.9h1.4v4.9l-.7 .7-.7-.7z" fill-rule="evenodd"/>
<path d="M101 83.3l.8-.7 .6 .7v12h-1.4z" fill-rule="evenodd"/>
<path d="M103.1 91.1l.7 .7v5h-1.4v-5z" fill-rule="evenodd"/>
<path d="M104.5 88.3l.7 .7v9.2h-1.4v-9.2z" fill-rule="evenodd"/>
<path d="M105.9 93.9l.6 .7v5h-1.3v-5z" fill-rule="evenodd"/>
<path d="M107.2 95.3l.7 .8v4.9h-1.4v-4.9z" fill-rule="evenodd"/>
<path d="M107.9 97.5l.7-.7 .7 .7v4.9h-1.4z" fill-rule="evenodd"/>
<path d="M110 98.2l.7 .7v4.9h-1.4v-4.9z" fill-rule="evenodd"/>
<path d="M110.7 100.3l.7-.7 .6 .7v4.9h-1.3z" fill-rule="evenodd"/>
<path d="M112 100.3l.7-.7 .7 .7v6.4h-1.4z" fill-rule="evenodd"/>
<path d="M114.1 101l.7 .7v6.4h-1.4v-6.4z" fill-rule="evenodd"/>
</g>
<g fill="none" stroke="#000" stroke-width=".13">
<path d="M92.2 85.4v32.6h-11.1v14.2M93.5 86.9v32.5h-11v12.8M94.9 88.3v32.5h-11v11.4M97.6 91.1v32.6h-11v8.5M99 92.5v32.6h-11v7.1M101.8 95.3v32.6h-11v4.3M103.1 96.8v32.5h-10.9v2.9M104.5 98.2v32.6h-11v1.4M105.9 99.6v32.6h-11M107.2 101v42.5h-1.3M108.6 102.4v42.5h-2.7M110 103.8v42.5h-4.1"/>
<path d="M111.4 105.2v42.5h-5.5M112.7 106.7v42.4h-6.8M114.1 108.1v48.2h-8.2M115.5 109.5v58.1M136.1 118v39.7h-30.2M138.8 112.4v46.7h-32.9M141.6 118v42.5h-35.7M144.3 115.2v46.7h-38.4M67.4 123.7l1.4 1.4v7.1M68.8 123.7l1.4 1.4v7.1M70.2 123.7l1.3 1.4v7.1M48.2 159.1l1.4 1.4h8.2"/>
<path d="M48.2 157.7l1.4 1.4h8.2M48.2 156.3l1.4 1.4h8.2M48.2 154.8l1.4 1.5h8.2M48.2 153.4l1.4 1.4h8.2M48.2 152l1.4 1.4h8.2M51 150.6l1.3 1.4h5.5M51 149.1l1.3 1.5h5.5M51 147.7l1.3 1.4h5.5M51 146.3l1.3 1.4h5.5M51 144.9l1.3 1.4h5.5M51 143.5l1.3 1.4h5.5M51 142.1l1.3 1.4h5.5"/>
<path d="M105.3 154.3l1.1 1.1M105.9 152h4.1v2.8h11M106.4 154.3l-1.1 1.1M126.4 143.5h-1.3v7.1h-19.2M48.2 169l1.4 1.4h8.2M48.2 167.6l1.4 1.4h8.2M48.2 166.2l1.4 1.4h8.2M48.2 164.7l1.4 1.5h8.2M48.2 160.5l1.4 1.4h8.2M51 162.6v1.4M51 163.3h1.3M105.9 169h2.7v48.1"/>
<path d="M105.9 166.2h16.4v15.5h8.3M105.9 164.7h17.8v12.8h11v-1.4M105.9 163.3h19.2v4.3h1.3M133.3 167.6h1.4v1.4M134.7 167.6h2.7v2.1M137.4 175.3v2.2h-2.7M137.4 177.5h2.8M137.4 167.6h2.8M144.3 177.5h2.8M144.3 167.6h2.8M68.8 181.7v7.1l-1.4 1.4M70.2 181.7v7.1l-1.4 1.4"/>
<path d="M71.5 181.7v7.1l-1.3 1.4M72.9 181.7v7.1l-1.4 1.4M74.3 181.7v7.1l-1.4 1.4M75.6 181.7v18.5h-1.3v21.2M77 181.7v4.3M79.8 181.7v5.7h4.1v-5.7M81.1 181.7v22.7M82.5 181.7v11.3h1.4v11.4M85.2 181.7v9.9h1.4v12.8M86.6 181.7v4.3h-9.6v4.8M88 181.7v5.7h-4.1M88 187.4h8.3"/>
<path d="M89.4 181.7v14.2h2.8l-.1 8.5M90.8 181.7v12.8h4.1v9.9M81.1 211.5v5.6M83.9 211.5v5.6M86.6 211.5v9.9M92.1 211.5v8.5M94.9 211.5v9.9M137.4 214.3v4.3M138.8 210.1h-1.4v4.2h1.4M138.8 218.6h-1.4v4.2M142.9 210.1h1.4v4.2h-1.4M144.3 214.3v4.3h-1.4"/>
<path d="M144.3 218.6v4.2M131.9 226.3v1.5M138.8 222.8h-1.4v4.2h-5.5M142.9 222.8h1.4v4.2h1.4"/>
<circle cx="77" cy="191.3" r=".4"/>
</g>
<path d="M48.2 98.2v90.6l1.4 1.4h23.3M66 89.7v32.6" fill="none" stroke="#000" stroke-width=".42"/>
<g fill="#fff" stroke="#000" stroke-width=".13">
<path d="M77.7 217.1h1.4v9.2l-.7 .7-.7-.7z" fill-rule="evenodd"/>
<path d="M114.8 100.3l.7-.7 .7 .7v9.2h-1.4z" fill-rule="evenodd"/>
</g>
<g fill="none" stroke="#000" stroke-width=".13">
<path d="M126.4 143.5h1.4M127.8 142.8v1.4M140.2 177.5h1.6M140.2 167.6h1.6M141.8 176.2v2.6M141.8 166.3v2.5M142.5 177.5h1.8M142.5 176.2v2.6M142.5 167.6h1.8M142.5 166.3v2.5M147.1 177.5h1.3M147.1 167.6h1.3"/>
<path d="M148.4 176.8v1.4M148.4 166.9v1.4M96.3 187.4h1.3M97.6 186.7v1.4M130.6 181.7h1.3M131.9 181v1.4M145.7 227h1.4M147.1 226.3v1.5"/>
</g>
<path d="M61.9 136.4h39.9v41.1h-39.9z" fill-rule="evenodd" fill="#fff" stroke="#000" stroke-width=".13"/>
<g fill="none" stroke="#000" stroke-width=".13">
<path d="M131.9 106.7h1.4M131.9 106v1.4M137.4 106.7v11.3h-1.3M138.8 106.7v5.7M140.2 106.7v11.3h1.4M141.6 106.7v8.5h2.7M143 106.7v5.7h4.1v49.5h4.1v24.1h-49.4v-4.3h-6.9v-4.2M144.3 106.7v2.8h5.5v49.6h4.1v29.7h-45.3M145.7 106.7h6.9M152.6 106v1.4M68.8 132.2v4.2M70.2 132.2v4.2"/>
<path d="M71.5 132.2v4.2M71.5 123.7l1.4 1.4v11.3M72.9 123.7l1.4 1.4v11.3M75.6 125.1v11.3M77 123.7l1.4 1.4v11.3M77 125.1v11.3M79.2 131.6l1.1 1.1M79.8 132.2v4.2M80.3 131.6l-1.1 1.1M81.1 132.2v4.2M82.5 132.2v4.2M83.9 132.2v4.2"/>
<path d="M85.3 126.5v9.9M86.6 132.2v4.2M88 132.2v4.2M88.8 131.6l1.1 1.1M89.4 132.2v4.2M89.9 131.6l-1.1 1.1M90.8 132.2v4.2M92.2 132.2v4.2M93.5 132.2v4.2M94.9 132.2v4.2M57.8 159.1h4.1M57.8 157.7h4.1"/>
<path d="M57.8 156.3h4.1M57.8 154.8h4.1M57.8 153.4h4.1M57.8 152h4.1M57.8 143.5h4.1M57.8 150.6h4.1M57.8 149.1h4.1M57.8 147.7h4.1M57.8 146.3h4.1M57.8 144.9h4.1M101.8 159.1h4.1M101.8 157.7h4.1"/>
<path d="M101.8 156.3h4.1M101.8 154.8h4.1M101.8 153.4h4.1M101.8 152h4.1M101.8 143.5h4.1M101.8 150.6h4.1M101.8 149.1h4.1M101.8 147.7h4.1M101.8 146.3h4.1M101.8 144.9h4.1M105.3 152.8l1.1 1.2M106.4 152.8l-1.1 1.2"/>
<path d="M52.3 178.2v1.4M52.3 163.3h9.6M57.8 170.4h4.1M57.8 169h4.1M57.8 167.6h4.1M57.8 166.2h4.1M57.8 161.9h4.1M57.8 160.5h4.1M61.9 164.7h-5.5v14.2h-4.1M68.8 177.5v4.2M70.2 177.5v4.2M71.5 177.5v4.2"/>
<path d="M72.9 177.5v4.2M74.3 177.5v4.2M75.6 177.5v4.2M77 177.5v4.2M78.4 177.5v39.6M79.8 177.5v4.2M81.1 177.5v4.2M82.5 177.5v4.2M83.9 177.5v4.2M85.2 177.5v4.2M86.6 177.5v4.2M88 177.5v4.2"/>
<path d="M89.4 177.5v4.2M90.8 177.5v4.2M92.2 177.5v4.2M93.5 177.5v4.2M101.8 170.4h4.1M101.8 169h4.1M101.8 167.6h13.7M101.8 166.2h4.1M101.8 164.7h4.1M101.8 163.3h4.1M101.8 161.9h4.1M101.8 160.5h4.1"/>
<path d="M105.9 174.7h1.3M107.2 173.9v1.4M126.4 167.6h1.4M127.8 166.9h4.1v1.4h-4.1zM131.9 167.6h1.4M134 170.4h1.4v4.3h-1.4zM134.7 174.7v1.4M134.7 169v1.4M136.1 171.7h2.7v1.7h-2.8zM136.8 174h1.3M136.8 171.1h1.3M137.4 174v1.3"/>
<path d="M137.4 169.7v1.4M91.6 181.1l1.1 1.2M92.7 181.1l-1.1 1.2M93 181.1l1.1 1.2M94.1 181.1l-1.1 1.2M81.1 204.4v7.1M83.9 204.4v7.1M86 205.8h1.3v4.3h-1.3zM86.6 204.4v1.4M86.6 210.1v1.4M91.4 205.8h1.4v4.3h-1.4zM92.1 204.4v1.4"/>
<path d="M92.1 210.1v1.4M94.2 205.8h1.4v4.3h-1.4zM94.9 204.4v1.4M94.9 210.1v1.4M138.8 210.1h1.7M138.8 214.3h1.7M138.8 218.6h1.7M140.5 205.8h-3.1v4.3M140.5 204.5v2.6M140.5 208.8v2.5M140.5 213v2.6M140.5 217.3v2.5"/>
<path d="M141.1 205.8h3.2v4.3M141.1 210.1h1.8M141.1 204.5v2.6M141.1 208.8v2.5M141.1 213v2.6M141.1 217.3v2.5M141.1 214.3h1.8M141.1 218.6h1.8M138.8 222.8h1.7M140.5 221.5v2.6M141.1 221.5v2.6M141.1 222.8h1.8"/>
</g>
<path d="M66 122.3v1.4h11M66 123.7h-15v26.9" fill="none" stroke="#000" stroke-width=".42"/>
<g fill="none" stroke="#000" stroke-width=".3">
<path d="M149.8 106.7h-.8v.3M120 154.8h-.8v.3"/>
<circle cx="148.9" cy="107.6" r=".53"/>
<circle cx="119.2" cy="155.7" r=".53"/>
</g>
<circle cx="137.4" cy="210" r=".25" fill="#000" stroke="#000" stroke-width=".13"/>
<path d="M133.3 98.2h13.8v4.2h-13.8z" fill-rule="evenodd" fill="#fff" stroke="#000" stroke-width=".13"/>
<g fill="none" stroke="#000" stroke-width=".13">
<path d="M140.2 84l1.4 1.4h-2.8l1.4-1.4v11.3M130.6 114.5v1.4M130.6 115.2h2.7M134.7 103.3v3.4h-1.4M136.1 103.3v11.9h-2.8v39.6h-12.3M137.4 103.3v3.4M138.8 103.3v3.4M140.2 103.3v3.4M141.6 103.3v3.4M143 103.3v3.4M144.3 103.3v3.4M145.7 103.3v3.4"/>
<path d="M105.9 170.4v4.3"/>
<circle cx="134.7" cy="102.9" r=".41"/>
<circle cx="136.1" cy="102.9" r=".4"/>
<circle cx="137.4" cy="102.9" r=".41"/>
<circle cx="138.8" cy="102.9" r=".4"/>
<circle cx="140.2" cy="102.9" r=".4"/>
<circle cx="141.5" cy="102.9" r=".41"/>
<circle cx="142.9" cy="102.9" r=".4"/>
<circle cx="144.3" cy="102.9" r=".41"/>
<circle cx="145.7" cy="102.9" r=".4"/>
</g>
<g fill="#000" stroke="#000" stroke-width=".13">
<circle cx="133.3" cy="115.2" r=".25"/>
<circle cx="134.7" cy="177.5" r=".24"/>
<circle cx="134.7" cy="167.6" r=".24"/>
<circle cx="137.4" cy="177.5" r=".25"/>
<circle cx="137.4" cy="167.6" r=".25"/>
<circle cx="77" cy="186" r=".27"/>
<circle cx="83.9" cy="187.4" r=".24"/>
<circle cx="88" cy="187.4" r=".25"/>
<circle cx="108.6" cy="188.8" r=".27"/>
<circle cx="137.4" cy="214.3" r=".27"/>
<circle cx="137.4" cy="218.6" r=".25"/>
<circle cx="144.3" cy="210" r=".25"/>
<circle cx="144.3" cy="218.6" r=".25"/>
<circle cx="144.3" cy="214.3" r=".27"/>
<circle cx="137.4" cy="222.8" r=".27"/>
<circle cx="144.3" cy="222.8" r=".27"/>
</g>
<path d="M20.4 28.5h165.2v237.5h-165.2z" fill="none" stroke="#000" stroke-width=".71" stroke-linecap="butt"/>
<use href="#words"/>
</svg>
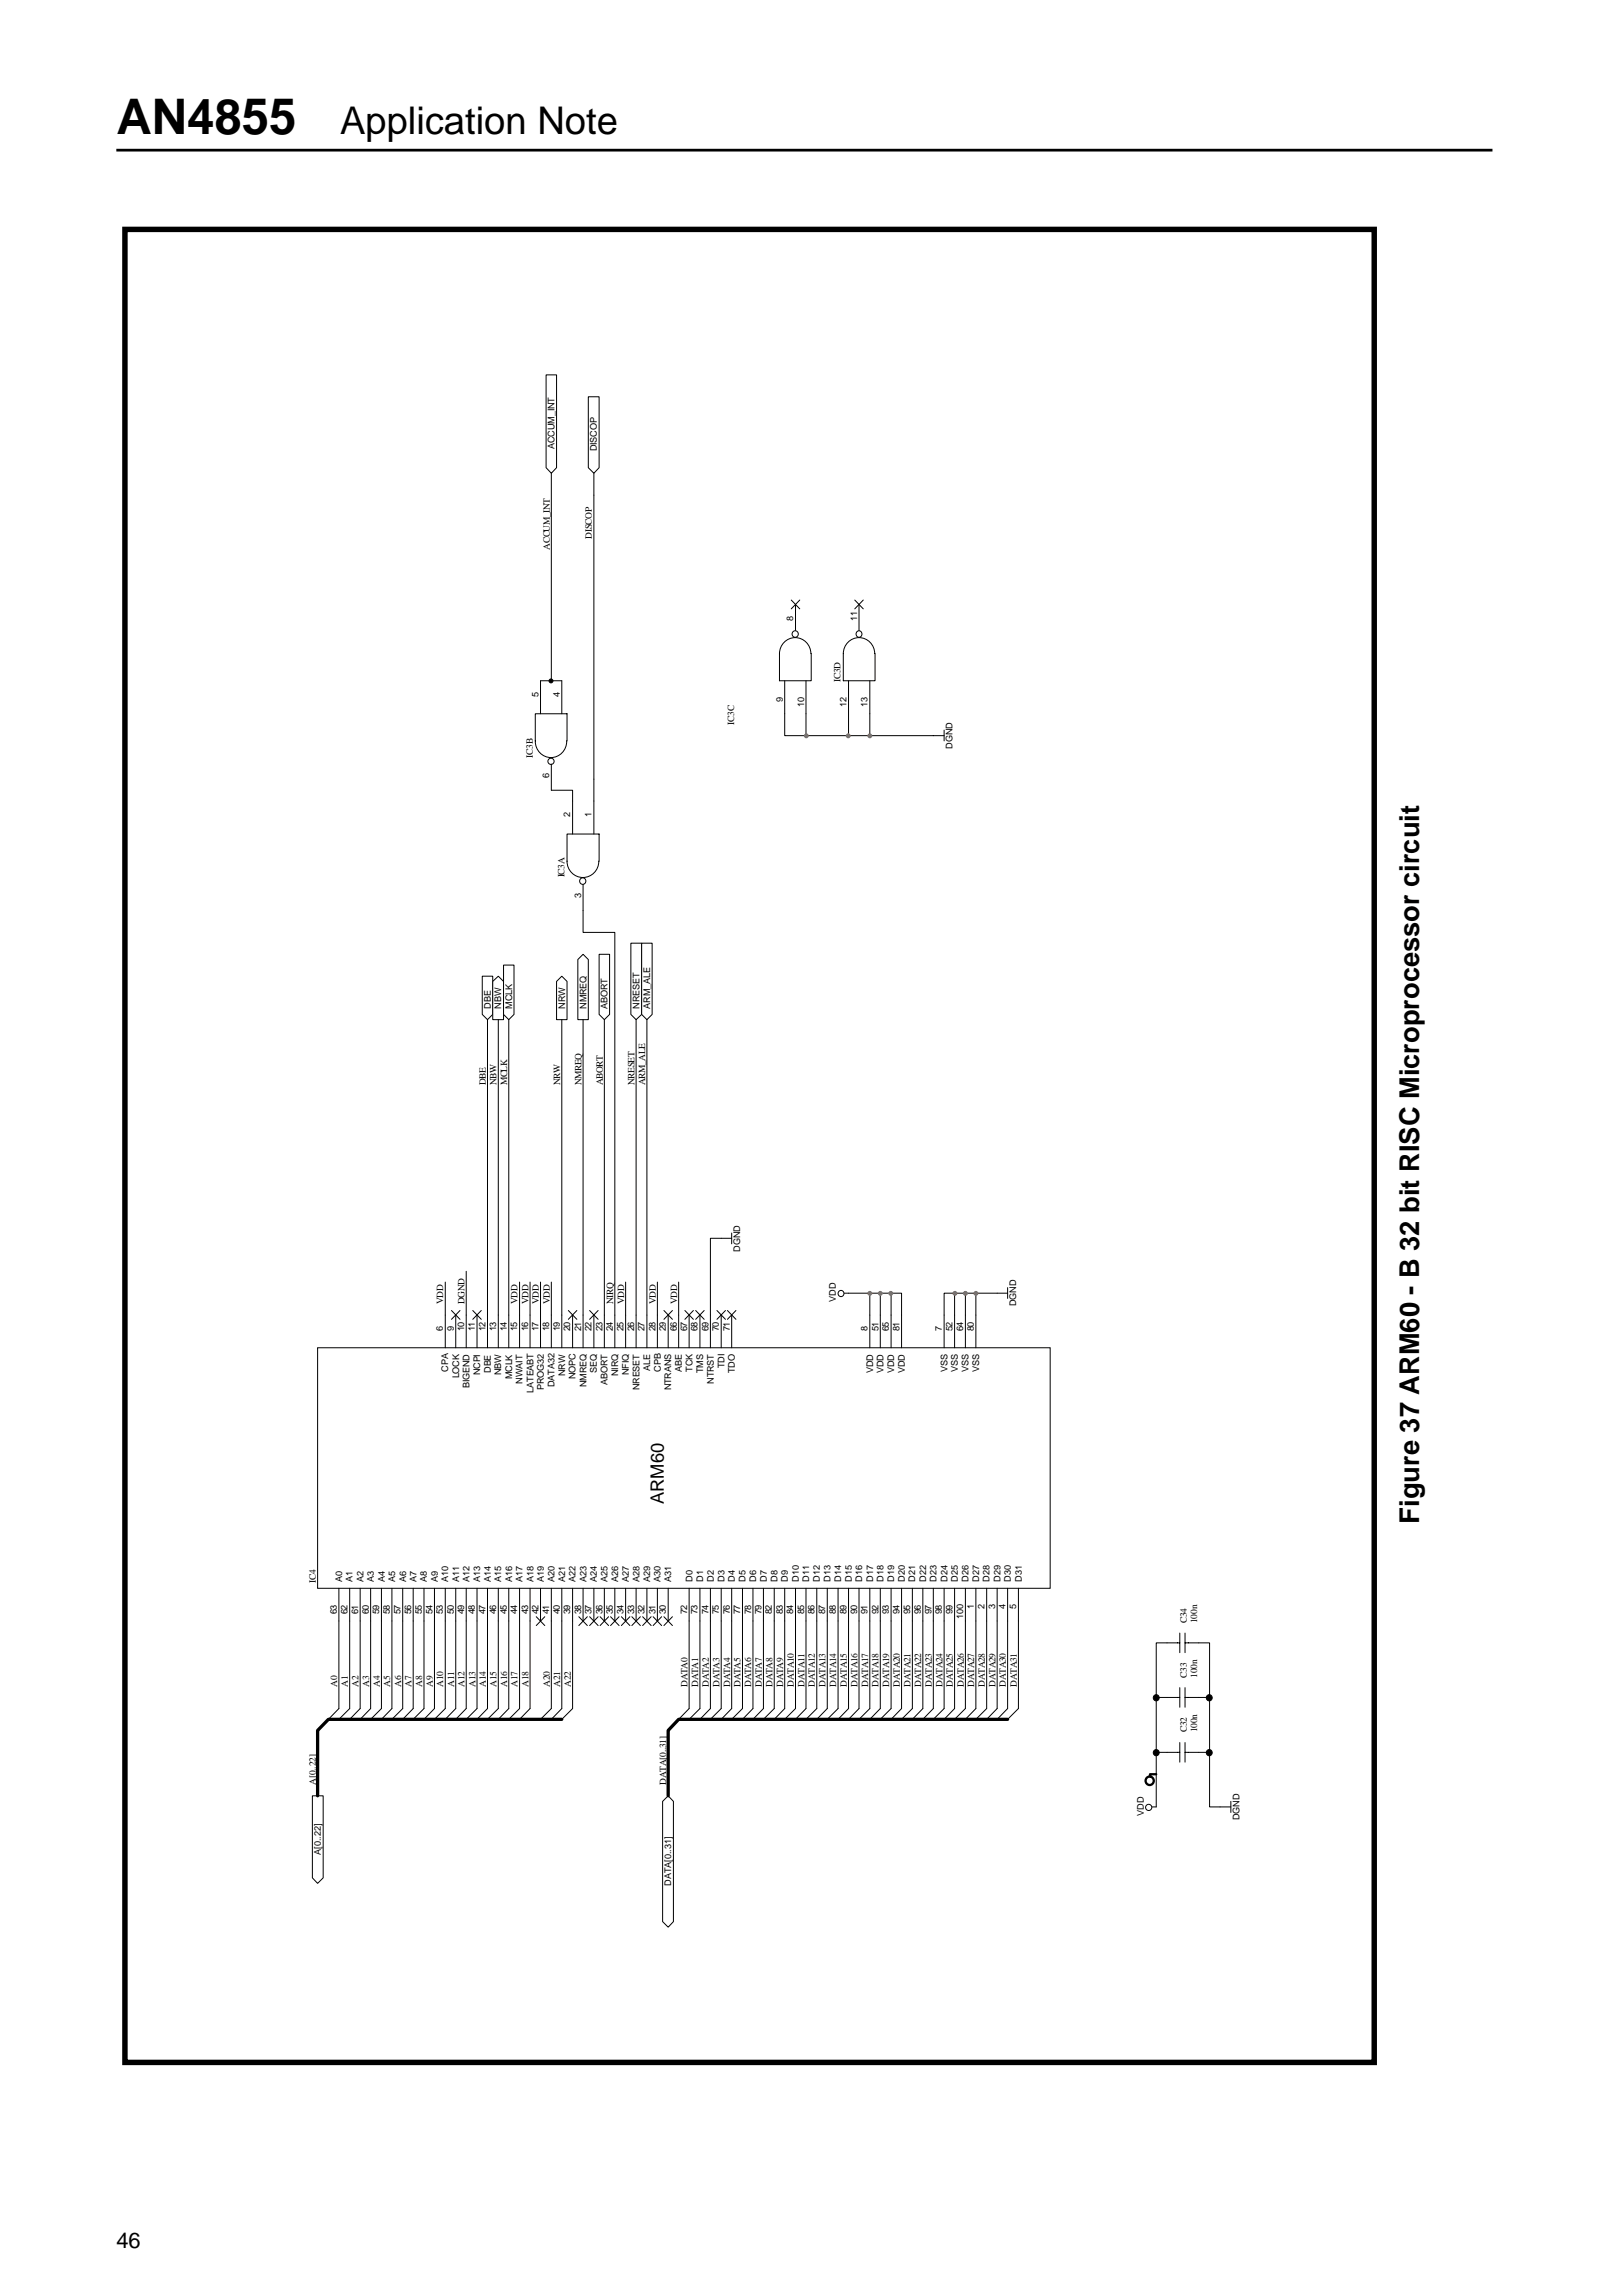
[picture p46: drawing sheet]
<svg xmlns="http://www.w3.org/2000/svg" width="210mm" height="297mm" viewBox="0 0 210 297" stroke-linecap="round" stroke-linejoin="round" font-family="sans-serif">
<defs><g id="words">
<text font-size="6.3" x="15" y="17.3">AN4855</text>
<text font-size="4.9" x="44" y="17.3">Application Note</text>
<text font-size="3.5" x="183.6" y="197" transform="rotate(-90 183.6 197)">Figure 37 ARM60 - B 32 bit RISC Microprocessor circuit</text>
<text font-size="2.8" x="15" y="290.7">46</text>
<text font-size="2.4" x="85.9" y="194.5" transform="rotate(-90 85.9 194.5)">ARM60</text>
<g font-size="1.2">
<text x="71.7" y="58.1" transform="rotate(-90 71.7 58.1)">ACCUM_INT</text>
<text x="77.2" y="58.4" transform="rotate(-90 77.2 58.4)">DISCOP</text>
<text x="71.1" y="71.1" transform="rotate(-90 71.1 71.1)">ACCUM_INT</text>
<text x="76.6" y="69.7" transform="rotate(-90 76.6 69.7)">DISCOP</text>
<text x="102.6" y="80.3" transform="rotate(-90 102.6 80.3)">8</text>
<text x="110.8" y="80.3" transform="rotate(-90 110.8 80.3)">11</text>
<text x="108.7" y="88.2" transform="rotate(-90 108.7 88.2)">IC3D</text>
<text x="69.7" y="90.2" transform="rotate(-90 69.7 90.2)">5</text>
<text x="72.4" y="90.2" transform="rotate(-90 72.4 90.2)">4</text>
<text x="95" y="93.7" transform="rotate(-90 95 93.7)">IC3C</text>
<text x="101.2" y="90.7" transform="rotate(-90 101.2 90.7)">9</text>
<text x="104" y="91.5" transform="rotate(-90 104 91.5)">10</text>
<text x="109.5" y="91.5" transform="rotate(-90 109.5 91.5)">12</text>
<text x="112.2" y="91.5" transform="rotate(-90 112.2 91.5)">13</text>
<text x="68.9" y="98" transform="rotate(-90 68.9 98)">IC3B</text>
<text x="71" y="100.6" transform="rotate(-90 71 100.6)">6</text>
<text x="123.2" y="96.8" transform="rotate(-90 123.2 96.8)">DGND</text>
<text x="73.8" y="105.7" transform="rotate(-90 73.8 105.7)">2</text>
<text x="76.5" y="105.7" transform="rotate(-90 76.5 105.7)">1</text>
<text x="73" y="113.5" transform="rotate(-90 73 113.5)">IC3A</text>
<text x="75.2" y="116.2" transform="rotate(-90 75.2 116.2)">3</text>
<text x="63.5" y="130.5" transform="rotate(-90 63.5 130.5)">DBE</text>
<text x="64.8" y="130.5" transform="rotate(-90 64.8 130.5)">NBW</text>
<text x="66.2" y="130.5" transform="rotate(-90 66.2 130.5)">MCLK</text>
<text x="73.1" y="130.5" transform="rotate(-90 73.1 130.5)">NRW</text>
<text x="75.8" y="130.5" transform="rotate(-90 75.8 130.5)">NMREQ</text>
<text x="78.6" y="130.5" transform="rotate(-90 78.6 130.5)">ABORT</text>
<text x="82.7" y="130.5" transform="rotate(-90 82.7 130.5)">NRESET</text>
<text x="84.1" y="130.5" transform="rotate(-90 84.1 130.5)">ARM_ALE</text>
<text x="62.8" y="140.4" transform="rotate(-90 62.8 140.4)">DBE</text>
<text x="64.2" y="140.4" transform="rotate(-90 64.2 140.4)">NBW</text>
<text x="65.6" y="140.4" transform="rotate(-90 65.6 140.4)">MCLK</text>
<text x="72.4" y="140.4" transform="rotate(-90 72.4 140.4)">NRW</text>
<text x="75.2" y="140.4" transform="rotate(-90 75.2 140.4)">NMREQ</text>
<text x="78" y="140.4" transform="rotate(-90 78 140.4)">ABORT</text>
<text x="82.1" y="140.4" transform="rotate(-90 82.1 140.4)">NRESET</text>
<text x="83.5" y="140.4" transform="rotate(-90 83.5 140.4)">ARM_ALE</text>
<text x="95.7" y="161.9" transform="rotate(-90 95.7 161.9)">DGND</text>
<text x="57.3" y="172.2" transform="rotate(-90 57.3 172.2)">6</text>
<text x="57.3" y="168.6" transform="rotate(-90 57.3 168.6)">VDD</text>
<text x="58.7" y="172.2" transform="rotate(-90 58.7 172.2)">9</text>
<text x="60" y="172.2" transform="rotate(-90 60 172.2)">10</text>
<text x="60.1" y="168.6" transform="rotate(-90 60.1 168.6)">DGND</text>
<text x="61.4" y="172.2" transform="rotate(-90 61.4 172.2)">11</text>
<text x="62.8" y="172.2" transform="rotate(-90 62.8 172.2)">12</text>
<text x="64.2" y="172.2" transform="rotate(-90 64.2 172.2)">13</text>
<text x="65.5" y="172.2" transform="rotate(-90 65.5 172.2)">14</text>
<text x="66.9" y="172.2" transform="rotate(-90 66.9 172.2)">15</text>
<text x="66.9" y="168.6" transform="rotate(-90 66.9 168.6)">VDD</text>
<text x="68.3" y="172.2" transform="rotate(-90 68.3 172.2)">16</text>
<text x="68.3" y="168.6" transform="rotate(-90 68.3 168.6)">VDD</text>
<text x="69.7" y="172.2" transform="rotate(-90 69.7 172.2)">17</text>
<text x="69.7" y="168.6" transform="rotate(-90 69.7 168.6)">VDD</text>
<text x="71" y="172.2" transform="rotate(-90 71 172.2)">18</text>
<text x="71.1" y="168.6" transform="rotate(-90 71.1 168.6)">VDD</text>
<text x="72.4" y="172.2" transform="rotate(-90 72.4 172.2)">19</text>
<text x="73.8" y="172.2" transform="rotate(-90 73.8 172.2)">20</text>
<text x="75.2" y="172.2" transform="rotate(-90 75.2 172.2)">21</text>
<text x="76.5" y="172.2" transform="rotate(-90 76.5 172.2)">22</text>
<text x="77.9" y="172.2" transform="rotate(-90 77.9 172.2)">23</text>
<text x="79.3" y="172.2" transform="rotate(-90 79.3 172.2)">24</text>
<text x="79.3" y="168.6" transform="rotate(-90 79.3 168.6)">NIRQ</text>
<text x="80.6" y="172.2" transform="rotate(-90 80.6 172.2)">25</text>
<text x="80.7" y="168.6" transform="rotate(-90 80.7 168.6)">VDD</text>
<text x="82" y="172.2" transform="rotate(-90 82 172.2)">26</text>
<text x="83.4" y="172.2" transform="rotate(-90 83.4 172.2)">27</text>
<text x="84.8" y="172.2" transform="rotate(-90 84.8 172.2)">28</text>
<text x="84.8" y="168.6" transform="rotate(-90 84.8 168.6)">VDD</text>
<text x="86.1" y="172.2" transform="rotate(-90 86.1 172.2)">29</text>
<text x="87.5" y="172.2" transform="rotate(-90 87.5 172.2)">66</text>
<text x="87.6" y="168.6" transform="rotate(-90 87.6 168.6)">VDD</text>
<text x="88.9" y="172.2" transform="rotate(-90 88.9 172.2)">67</text>
<text x="90.2" y="172.2" transform="rotate(-90 90.2 172.2)">68</text>
<text x="91.6" y="172.2" transform="rotate(-90 91.6 172.2)">69</text>
<text x="93" y="172.2" transform="rotate(-90 93 172.2)">70</text>
<text x="94.4" y="172.2" transform="rotate(-90 94.4 172.2)">71</text>
<text x="108.1" y="168.3" transform="rotate(-90 108.1 168.3)">VDD</text>
<text x="112.2" y="172.2" transform="rotate(-90 112.2 172.2)">8</text>
<text x="113.6" y="172.2" transform="rotate(-90 113.6 172.2)">51</text>
<text x="115" y="172.2" transform="rotate(-90 115 172.2)">65</text>
<text x="116.3" y="172.2" transform="rotate(-90 116.3 172.2)">81</text>
<text x="121.8" y="172.2" transform="rotate(-90 121.8 172.2)">7</text>
<text x="123.2" y="172.2" transform="rotate(-90 123.2 172.2)">52</text>
<text x="124.6" y="172.2" transform="rotate(-90 124.6 172.2)">64</text>
<text x="126" y="172.2" transform="rotate(-90 126 172.2)">80</text>
<text x="131.4" y="168.9" transform="rotate(-90 131.4 168.9)">DGND</text>
<text x="58" y="177.4" transform="rotate(-90 58 177.4)">CPA</text>
<text x="59.4" y="178.3" transform="rotate(-90 59.4 178.3)">LOCK</text>
<text x="60.7" y="179.5" transform="rotate(-90 60.7 179.5)">BIGEND</text>
<text x="62.1" y="177.9" transform="rotate(-90 62.1 177.9)">NCPI</text>
<text x="63.5" y="177.6" transform="rotate(-90 63.5 177.6)">DBE</text>
<text x="64.8" y="177.9" transform="rotate(-90 64.8 177.9)">NBW</text>
<text x="66.2" y="178.4" transform="rotate(-90 66.2 178.4)">MCLK</text>
<text x="67.6" y="179" transform="rotate(-90 67.6 179)">NWAIT</text>
<text x="70.3" y="179.8" transform="rotate(-90 70.3 179.8)">PROG32</text>
<text x="71.7" y="179.4" transform="rotate(-90 71.7 179.4)">DATA32</text>
<text x="73.1" y="178" transform="rotate(-90 73.1 178)">NRW</text>
<text x="74.4" y="178.4" transform="rotate(-90 74.4 178.4)">NOPC</text>
<text x="75.8" y="179.4" transform="rotate(-90 75.8 179.4)">NMREQ</text>
<text x="77.2" y="177.6" transform="rotate(-90 77.2 177.6)">SEQ</text>
<text x="78.6" y="179.1" transform="rotate(-90 78.6 179.1)">ABORT</text>
<text x="79.9" y="178" transform="rotate(-90 79.9 178)">NIRQ</text>
<text x="81.3" y="177.9" transform="rotate(-90 81.3 177.9)">NFIQ</text>
<text x="82.7" y="179.8" transform="rotate(-90 82.7 179.8)">NRESET</text>
<text x="84.1" y="177.3" transform="rotate(-90 84.1 177.3)">ALE</text>
<text x="85.4" y="177.4" transform="rotate(-90 85.4 177.4)">CPB</text>
<text x="86.8" y="179.8" transform="rotate(-90 86.8 179.8)">NTRANS</text>
<text x="88.2" y="177.4" transform="rotate(-90 88.2 177.4)">ABE</text>
<text x="89.6" y="177.4" transform="rotate(-90 89.6 177.4)">TCK</text>
<text x="90.9" y="177.6" transform="rotate(-90 90.9 177.6)">TMS</text>
<text x="92.3" y="179" transform="rotate(-90 92.3 179)">NTRST</text>
<text x="93.7" y="177" transform="rotate(-90 93.7 177)">TDI</text>
<text x="95.1" y="177.6" transform="rotate(-90 95.1 177.6)">TDO</text>
<text x="112.9" y="177.6" transform="rotate(-90 112.9 177.6)">VDD</text>
<text x="114.3" y="177.6" transform="rotate(-90 114.3 177.6)">VDD</text>
<text x="115.6" y="177.6" transform="rotate(-90 115.6 177.6)">VDD</text>
<text x="117" y="177.6" transform="rotate(-90 117 177.6)">VDD</text>
<text x="122.5" y="177.4" transform="rotate(-90 122.5 177.4)">VSS</text>
<text x="123.9" y="177.4" transform="rotate(-90 123.9 177.4)">VSS</text>
<text x="125.2" y="177.4" transform="rotate(-90 125.2 177.4)">VSS</text>
<text x="126.6" y="177.4" transform="rotate(-90 126.6 177.4)">VSS</text>
<text x="69" y="180.1" transform="rotate(-90 69 180.1)">LATEABT</text>
<text x="40.9" y="204.7" transform="rotate(-90 40.9 204.7)">IC4</text>
<text x="43.6" y="208.8" transform="rotate(-90 43.6 208.8)">63</text>
<text x="44.3" y="204.6" transform="rotate(-90 44.3 204.6)">A0</text>
<text x="44.9" y="208.8" transform="rotate(-90 44.9 208.8)">62</text>
<text x="45.6" y="204.6" transform="rotate(-90 45.6 204.6)">A1</text>
<text x="46.3" y="208.8" transform="rotate(-90 46.3 208.8)">61</text>
<text x="47" y="204.6" transform="rotate(-90 47 204.6)">A2</text>
<text x="47.7" y="208.8" transform="rotate(-90 47.7 208.8)">60</text>
<text x="48.4" y="204.6" transform="rotate(-90 48.4 204.6)">A3</text>
<text x="49" y="208.8" transform="rotate(-90 49 208.8)">59</text>
<text x="49.8" y="204.6" transform="rotate(-90 49.8 204.6)">A4</text>
<text x="50.4" y="208.8" transform="rotate(-90 50.4 208.8)">58</text>
<text x="51.1" y="204.6" transform="rotate(-90 51.1 204.6)">A5</text>
<text x="51.8" y="208.8" transform="rotate(-90 51.8 208.8)">57</text>
<text x="52.5" y="204.6" transform="rotate(-90 52.5 204.6)">A6</text>
<text x="53.2" y="208.8" transform="rotate(-90 53.2 208.8)">56</text>
<text x="53.9" y="204.6" transform="rotate(-90 53.9 204.6)">A7</text>
<text x="54.5" y="208.8" transform="rotate(-90 54.5 208.8)">55</text>
<text x="55.2" y="204.6" transform="rotate(-90 55.2 204.6)">A8</text>
<text x="55.9" y="208.8" transform="rotate(-90 55.9 208.8)">54</text>
<text x="56.6" y="204.6" transform="rotate(-90 56.6 204.6)">A9</text>
<text x="57.3" y="208.8" transform="rotate(-90 57.3 208.8)">53</text>
<text x="58" y="204.6" transform="rotate(-90 58 204.6)">A10</text>
<text x="58.7" y="208.8" transform="rotate(-90 58.7 208.8)">50</text>
<text x="59.4" y="204.6" transform="rotate(-90 59.4 204.6)">A11</text>
<text x="60" y="208.8" transform="rotate(-90 60 208.8)">49</text>
<text x="60.7" y="204.6" transform="rotate(-90 60.7 204.6)">A12</text>
<text x="61.4" y="208.8" transform="rotate(-90 61.4 208.8)">48</text>
<text x="62.1" y="204.6" transform="rotate(-90 62.1 204.6)">A13</text>
<text x="62.8" y="208.8" transform="rotate(-90 62.8 208.8)">47</text>
<text x="63.5" y="204.6" transform="rotate(-90 63.5 204.6)">A14</text>
<text x="64.1" y="208.8" transform="rotate(-90 64.1 208.8)">46</text>
<text x="64.8" y="204.6" transform="rotate(-90 64.8 204.6)">A15</text>
<text x="65.5" y="208.8" transform="rotate(-90 65.5 208.8)">45</text>
<text x="66.2" y="204.6" transform="rotate(-90 66.2 204.6)">A16</text>
<text x="66.9" y="208.8" transform="rotate(-90 66.9 208.8)">44</text>
<text x="67.6" y="204.6" transform="rotate(-90 67.6 204.6)">A17</text>
<text x="68.3" y="208.8" transform="rotate(-90 68.3 208.8)">43</text>
<text x="69" y="204.6" transform="rotate(-90 69 204.6)">A18</text>
<text x="69.7" y="208.8" transform="rotate(-90 69.7 208.8)">42</text>
<text x="70.3" y="204.6" transform="rotate(-90 70.3 204.6)">A19</text>
<text x="71" y="208.8" transform="rotate(-90 71 208.8)">41</text>
<text x="71.7" y="204.6" transform="rotate(-90 71.7 204.6)">A20</text>
<text x="72.4" y="208.8" transform="rotate(-90 72.4 208.8)">40</text>
<text x="73.1" y="204.6" transform="rotate(-90 73.1 204.6)">A21</text>
<text x="73.8" y="208.8" transform="rotate(-90 73.8 208.8)">39</text>
<text x="74.4" y="204.6" transform="rotate(-90 74.4 204.6)">A22</text>
<text x="75.2" y="208.8" transform="rotate(-90 75.2 208.8)">38</text>
<text x="75.8" y="204.6" transform="rotate(-90 75.8 204.6)">A23</text>
<text x="76.5" y="208.8" transform="rotate(-90 76.5 208.8)">37</text>
<text x="77.2" y="204.6" transform="rotate(-90 77.2 204.6)">A24</text>
<text x="77.9" y="208.8" transform="rotate(-90 77.9 208.8)">36</text>
<text x="78.6" y="204.6" transform="rotate(-90 78.6 204.6)">A25</text>
<text x="79.3" y="208.8" transform="rotate(-90 79.3 208.8)">35</text>
<text x="79.9" y="204.6" transform="rotate(-90 79.9 204.6)">A26</text>
<text x="80.6" y="208.8" transform="rotate(-90 80.6 208.8)">34</text>
<text x="81.3" y="204.6" transform="rotate(-90 81.3 204.6)">A27</text>
<text x="82" y="208.8" transform="rotate(-90 82 208.8)">33</text>
<text x="82.7" y="204.6" transform="rotate(-90 82.7 204.6)">A28</text>
<text x="83.4" y="208.8" transform="rotate(-90 83.4 208.8)">32</text>
<text x="84.1" y="204.6" transform="rotate(-90 84.1 204.6)">A29</text>
<text x="84.8" y="208.8" transform="rotate(-90 84.8 208.8)">31</text>
<text x="85.4" y="204.6" transform="rotate(-90 85.4 204.6)">A30</text>
<text x="86.1" y="208.8" transform="rotate(-90 86.1 208.8)">30</text>
<text x="86.8" y="204.6" transform="rotate(-90 86.8 204.6)">A31</text>
<text x="88.9" y="208.8" transform="rotate(-90 88.9 208.8)">72</text>
<text x="89.6" y="204.6" transform="rotate(-90 89.6 204.6)">D0</text>
<text x="90.2" y="208.8" transform="rotate(-90 90.2 208.8)">73</text>
<text x="90.9" y="204.6" transform="rotate(-90 90.9 204.6)">D1</text>
<text x="91.6" y="208.8" transform="rotate(-90 91.6 208.8)">74</text>
<text x="92.3" y="204.6" transform="rotate(-90 92.3 204.6)">D2</text>
<text x="93" y="208.8" transform="rotate(-90 93 208.8)">75</text>
<text x="93.7" y="204.6" transform="rotate(-90 93.7 204.6)">D3</text>
<text x="94.4" y="208.8" transform="rotate(-90 94.4 208.8)">76</text>
<text x="95.1" y="204.6" transform="rotate(-90 95.1 204.6)">D4</text>
<text x="95.7" y="208.8" transform="rotate(-90 95.7 208.8)">77</text>
<text x="96.4" y="204.6" transform="rotate(-90 96.4 204.6)">D5</text>
<text x="97.1" y="208.8" transform="rotate(-90 97.1 208.8)">78</text>
<text x="97.8" y="204.6" transform="rotate(-90 97.8 204.6)">D6</text>
<text x="98.5" y="208.8" transform="rotate(-90 98.5 208.8)">79</text>
<text x="99.2" y="204.6" transform="rotate(-90 99.2 204.6)">D7</text>
<text x="99.8" y="208.8" transform="rotate(-90 99.8 208.8)">82</text>
<text x="100.6" y="204.6" transform="rotate(-90 100.6 204.6)">D8</text>
<text x="101.2" y="208.8" transform="rotate(-90 101.2 208.8)">83</text>
<text x="101.9" y="204.6" transform="rotate(-90 101.9 204.6)">D9</text>
<text x="102.6" y="208.8" transform="rotate(-90 102.6 208.8)">84</text>
<text x="103.3" y="204.6" transform="rotate(-90 103.3 204.6)">D10</text>
<text x="104" y="208.8" transform="rotate(-90 104 208.8)">85</text>
<text x="104.7" y="204.6" transform="rotate(-90 104.7 204.6)">D11</text>
<text x="105.3" y="208.8" transform="rotate(-90 105.3 208.8)">86</text>
<text x="106" y="204.6" transform="rotate(-90 106 204.6)">D12</text>
<text x="106.7" y="208.8" transform="rotate(-90 106.7 208.8)">87</text>
<text x="107.4" y="204.6" transform="rotate(-90 107.4 204.6)">D13</text>
<text x="108.1" y="208.8" transform="rotate(-90 108.1 208.8)">88</text>
<text x="108.8" y="204.6" transform="rotate(-90 108.8 204.6)">D14</text>
<text x="109.5" y="208.8" transform="rotate(-90 109.5 208.8)">89</text>
<text x="110.2" y="204.6" transform="rotate(-90 110.2 204.6)">D15</text>
<text x="110.8" y="208.8" transform="rotate(-90 110.8 208.8)">90</text>
<text x="111.5" y="204.6" transform="rotate(-90 111.5 204.6)">D16</text>
<text x="112.2" y="208.8" transform="rotate(-90 112.2 208.8)">91</text>
<text x="112.9" y="204.6" transform="rotate(-90 112.9 204.6)">D17</text>
<text x="113.6" y="208.8" transform="rotate(-90 113.6 208.8)">92</text>
<text x="114.3" y="204.6" transform="rotate(-90 114.3 204.6)">D18</text>
<text x="114.9" y="208.8" transform="rotate(-90 114.9 208.8)">93</text>
<text x="115.6" y="204.6" transform="rotate(-90 115.6 204.6)">D19</text>
<text x="116.3" y="208.8" transform="rotate(-90 116.3 208.8)">94</text>
<text x="117" y="204.6" transform="rotate(-90 117 204.6)">D20</text>
<text x="117.7" y="208.8" transform="rotate(-90 117.7 208.8)">95</text>
<text x="118.4" y="204.6" transform="rotate(-90 118.4 204.6)">D21</text>
<text x="119.1" y="208.8" transform="rotate(-90 119.1 208.8)">96</text>
<text x="119.8" y="204.6" transform="rotate(-90 119.8 204.6)">D22</text>
<text x="120.5" y="208.8" transform="rotate(-90 120.5 208.8)">97</text>
<text x="121.1" y="204.6" transform="rotate(-90 121.1 204.6)">D23</text>
<text x="121.8" y="208.8" transform="rotate(-90 121.8 208.8)">98</text>
<text x="122.5" y="204.6" transform="rotate(-90 122.5 204.6)">D24</text>
<text x="123.2" y="208.8" transform="rotate(-90 123.2 208.8)">99</text>
<text x="123.9" y="204.6" transform="rotate(-90 123.9 204.6)">D25</text>
<text x="124.6" y="209.4" transform="rotate(-90 124.6 209.4)">100</text>
<text x="125.2" y="204.6" transform="rotate(-90 125.2 204.6)">D26</text>
<text x="126" y="208.1" transform="rotate(-90 126 208.1)">1</text>
<text x="126.6" y="204.6" transform="rotate(-90 126.6 204.6)">D27</text>
<text x="127.3" y="208.1" transform="rotate(-90 127.3 208.1)">2</text>
<text x="128" y="204.6" transform="rotate(-90 128 204.6)">D28</text>
<text x="128.7" y="208.1" transform="rotate(-90 128.7 208.1)">3</text>
<text x="129.4" y="204.6" transform="rotate(-90 129.4 204.6)">D29</text>
<text x="130.1" y="208.1" transform="rotate(-90 130.1 208.1)">4</text>
<text x="130.7" y="204.6" transform="rotate(-90 130.7 204.6)">D30</text>
<text x="131.4" y="208.1" transform="rotate(-90 131.4 208.1)">5</text>
<text x="132.1" y="204.6" transform="rotate(-90 132.1 204.6)">D31</text>
<text x="153.5" y="209.9" transform="rotate(-90 153.5 209.9)">C34</text>
<text x="154.8" y="209.9" transform="rotate(-90 154.8 209.9)">100n</text>
<text x="43.6" y="218.1" transform="rotate(-90 43.6 218.1)">A0</text>
<text x="45" y="218.1" transform="rotate(-90 45 218.1)">A1</text>
<text x="46.4" y="218.1" transform="rotate(-90 46.4 218.1)">A2</text>
<text x="47.7" y="218.1" transform="rotate(-90 47.7 218.1)">A3</text>
<text x="49.1" y="218.1" transform="rotate(-90 49.1 218.1)">A4</text>
<text x="50.5" y="218.1" transform="rotate(-90 50.5 218.1)">A5</text>
<text x="51.9" y="218.1" transform="rotate(-90 51.9 218.1)">A6</text>
<text x="53.2" y="218.1" transform="rotate(-90 53.2 218.1)">A7</text>
<text x="54.6" y="218.1" transform="rotate(-90 54.6 218.1)">A8</text>
<text x="56" y="218.1" transform="rotate(-90 56 218.1)">A9</text>
<text x="57.3" y="218.1" transform="rotate(-90 57.3 218.1)">A10</text>
<text x="58.7" y="218.1" transform="rotate(-90 58.7 218.1)">A11</text>
<text x="60.1" y="218.1" transform="rotate(-90 60.1 218.1)">A12</text>
<text x="61.5" y="218.1" transform="rotate(-90 61.5 218.1)">A13</text>
<text x="62.8" y="218.1" transform="rotate(-90 62.8 218.1)">A14</text>
<text x="64.2" y="218.1" transform="rotate(-90 64.2 218.1)">A15</text>
<text x="65.6" y="218.1" transform="rotate(-90 65.6 218.1)">A16</text>
<text x="66.9" y="218.1" transform="rotate(-90 66.9 218.1)">A17</text>
<text x="68.3" y="218.1" transform="rotate(-90 68.3 218.1)">A18</text>
<text x="71.1" y="218.1" transform="rotate(-90 71.1 218.1)">A20</text>
<text x="72.4" y="218.1" transform="rotate(-90 72.4 218.1)">A21</text>
<text x="73.8" y="218.1" transform="rotate(-90 73.8 218.1)">A22</text>
<text x="88.9" y="218.1" transform="rotate(-90 88.9 218.1)">DATA0</text>
<text x="90.3" y="218.1" transform="rotate(-90 90.3 218.1)">DATA1</text>
<text x="91.7" y="218.1" transform="rotate(-90 91.7 218.1)">DATA2</text>
<text x="93.1" y="218.1" transform="rotate(-90 93.1 218.1)">DATA3</text>
<text x="94.4" y="218.1" transform="rotate(-90 94.4 218.1)">DATA4</text>
<text x="95.8" y="218.1" transform="rotate(-90 95.8 218.1)">DATA5</text>
<text x="97.2" y="218.1" transform="rotate(-90 97.2 218.1)">DATA6</text>
<text x="98.5" y="218.1" transform="rotate(-90 98.5 218.1)">DATA7</text>
<text x="99.9" y="218.1" transform="rotate(-90 99.9 218.1)">DATA8</text>
<text x="101.3" y="218.1" transform="rotate(-90 101.3 218.1)">DATA9</text>
<text x="102.7" y="218.1" transform="rotate(-90 102.7 218.1)">DATA10</text>
<text x="104" y="218.1" transform="rotate(-90 104 218.1)">DATA11</text>
<text x="105.4" y="218.1" transform="rotate(-90 105.4 218.1)">DATA12</text>
<text x="106.8" y="218.1" transform="rotate(-90 106.8 218.1)">DATA13</text>
<text x="108.1" y="218.1" transform="rotate(-90 108.1 218.1)">DATA14</text>
<text x="109.5" y="218.1" transform="rotate(-90 109.5 218.1)">DATA15</text>
<text x="110.9" y="218.1" transform="rotate(-90 110.9 218.1)">DATA16</text>
<text x="112.3" y="218.1" transform="rotate(-90 112.3 218.1)">DATA17</text>
<text x="113.6" y="218.1" transform="rotate(-90 113.6 218.1)">DATA18</text>
<text x="115" y="218.1" transform="rotate(-90 115 218.1)">DATA19</text>
<text x="116.4" y="218.1" transform="rotate(-90 116.4 218.1)">DATA20</text>
<text x="117.7" y="218.1" transform="rotate(-90 117.7 218.1)">DATA21</text>
<text x="119.1" y="218.1" transform="rotate(-90 119.1 218.1)">DATA22</text>
<text x="120.5" y="218.1" transform="rotate(-90 120.5 218.1)">DATA23</text>
<text x="121.9" y="218.1" transform="rotate(-90 121.9 218.1)">DATA24</text>
<text x="123.2" y="218.1" transform="rotate(-90 123.2 218.1)">DATA25</text>
<text x="124.6" y="218.1" transform="rotate(-90 124.6 218.1)">DATA26</text>
<text x="126" y="218.1" transform="rotate(-90 126 218.1)">DATA27</text>
<text x="127.4" y="218.1" transform="rotate(-90 127.4 218.1)">DATA28</text>
<text x="128.8" y="218.1" transform="rotate(-90 128.8 218.1)">DATA29</text>
<text x="130.1" y="218.1" transform="rotate(-90 130.1 218.1)">DATA30</text>
<text x="131.5" y="218.1" transform="rotate(-90 131.5 218.1)">DATA31</text>
<text x="153.5" y="217" transform="rotate(-90 153.5 217)">C33</text>
<text x="154.8" y="217" transform="rotate(-90 154.8 217)">100n</text>
<text x="153.5" y="224.1" transform="rotate(-90 153.5 224.1)">C32</text>
<text x="154.8" y="224.1" transform="rotate(-90 154.8 224.1)">100n</text>
<text x="40.9" y="230.9" transform="rotate(-90 40.9 230.9)">A[0..22]</text>
<text x="86.2" y="230.9" transform="rotate(-90 86.2 230.9)">DATA[0..31]</text>
<text x="41.5" y="239.9" transform="rotate(-90 41.5 239.9)">A[0..22]</text>
<text x="147.9" y="234.8" transform="rotate(-90 147.9 234.8)">VDD</text>
<text x="160.3" y="235.4" transform="rotate(-90 160.3 235.4)">DGND</text>
<text x="86.8" y="243.9" transform="rotate(-90 86.8 243.9)">DATA[0..31]</text>
</g>
</g></defs>
<path d="M15 19.4h178" fill="none" stroke="#000" stroke-width=".35"/>
<path d="M30.8 70.4h133.8v190.7h-133.8z" fill="#fff"/>
<path d="M148.1 85h5.7v5.9h-5.7z" fill-rule="evenodd" fill="#fff" stroke="#fff" stroke-width=".13"/>
<g fill="#fff" stroke="#000" stroke-width=".13">
<path d="M40.4 232.3h1.4v10.6l-.7 .7-.7-.7z" fill-rule="evenodd"/>
<path d="M85.7 233l.7-.7 .7 .7v15.5l-.7 .7-.7-.7z" fill-rule="evenodd"/>
<path d="M62.4 126.3h1.3v4.9l-.7 .7-.6-.7z" fill-rule="evenodd"/>
<path d="M63.7 126.9l.7-.6 .7 .6v5h-1.4z" fill-rule="evenodd"/>
<path d="M65.1 124.8h1.4v6.4l-.7 .7-.7-.7z" fill-rule="evenodd"/>
<path d="M72 126.9l.7-.6 .6 .6v5h-1.3z" fill-rule="evenodd"/>
<path d="M74.7 124.1l.7-.7 .7 .7v7.8h-1.4z" fill-rule="evenodd"/>
<path d="M77.5 123.4h1.3v7.8l-.6 .7-.7-.7z" fill-rule="evenodd"/>
<path d="M81.6 122h1.4v9.2l-.7 .7-.7-.7z" fill-rule="evenodd"/>
<path d="M83 122h1.3v9.2l-.6 .7-.7-.7z" fill-rule="evenodd"/>
</g>
<g fill="none" stroke="#000" stroke-width=".13">
<path d="M63 131.9v38.2M64.4 131.9v38.2M65.8 131.9v38.2M72.7 131.9v38.2M75.4 131.9v38.2M78.2 131.9v38.2M82.3 131.9v38.2M83.7 131.9v38.2M57.6 165.8v4.3M58.4 169.5l1.1 1.1M59.5 169.5l-1.1 1.1M60.3 164.4v5.7"/>
<path d="M61.1 169.5l1.1 1.1M62.2 169.5l-1.1 1.1M67.2 165.8v4.3M68.6 165.8v4.3M69.9 165.8v4.3M71.3 165.8v4.3M76.3 169.5l1.1 1.1M77.4 169.5l-1.1 1.1M85 165.8v4.3M87.8 165.8v4.3M93.3 160.1h-1.4v10M109.2 167.3h7.4v2.8"/>
<path d="M112.5 167.3v2.8M113.8 167.3v2.8M115.2 167.3v2.8M123.5 167.3v2.8M124.9 167.3v2.8M126.2 167.3v2.8M129 167.3h-6.9v2.8M43.8 209.6v11.4l-1.3 1.4M45.2 209.6v11.4l-1.4 1.4M46.6 209.6v11.4l-1.4 1.4M47.9 209.6v11.4l-1.3 1.4M49.3 209.6v11.4l-1.4 1.4"/>
<path d="M50.7 209.6v11.4l-1.4 1.4M52.1 209.6v11.4l-1.4 1.4M53.4 209.6v11.4l-1.3 1.4M54.8 209.6v11.4l-1.4 1.4M56.2 209.6v11.4l-1.4 1.4M57.6 209.6v11.4l-1.4 1.4M58.9 209.6v11.4l-1.3 1.4M60.3 209.6v11.4l-1.4 1.4M61.7 209.6v11.4l-1.4 1.4M63 209.6v11.4l-1.3 1.4M64.4 209.6v11.4l-1.4 1.4M65.8 209.6v11.4l-1.4 1.4"/>
<path d="M67.2 209.6v11.4l-1.4 1.4M68.6 209.6v11.4l-1.4 1.4M71.3 209.6v11.4l-1.4 1.4M72.7 209.6v11.4l-1.4 1.4M74.1 209.6v11.4l-1.4 1.4M89.1 209.6v11.4l-1.3 1.4M90.5 209.6v11.4l-1.4 1.4M91.9 209.6v11.4l-1.4 1.4M93.3 209.6v11.4l-1.4 1.4M94.6 209.6v11.4l-1.3 1.4M96 209.6v11.4l-1.4 1.4M97.4 209.6v11.4l-1.4 1.4"/>
<path d="M98.7 209.6v11.4l-1.3 1.4M100.1 209.6v11.4l-1.4 1.4M101.5 209.6v11.4l-1.4 1.4M102.9 209.6v11.4l-1.4 1.4M104.2 209.6v11.4l-1.3 1.4M105.6 209.6v11.4l-1.4 1.4M107 209.6v11.4l-1.4 1.4M108.4 209.6v11.4l-1.4 1.4M109.7 209.6v11.4l-1.3 1.4M111.1 209.6v11.4l-1.4 1.4M112.5 209.6v11.4l-1.4 1.4M113.8 209.6v11.4l-1.3 1.4"/>
<path d="M115.2 209.6v11.4l-1.4 1.4M116.6 209.6v11.4l-1.4 1.4M118 209.6v11.4l-1.4 1.4M119.4 209.6v11.4l-1.4 1.4M120.7 209.6v11.4l-1.3 1.4M122.1 209.6v11.4l-1.4 1.4M123.5 209.6v11.4l-1.4 1.4M124.9 209.6v11.4l-1.4 1.4M126.2 209.6v11.4l-1.3 1.4M127.6 209.6v11.4l-1.4 1.4M129 209.6v11.4l-1.4 1.4M130.3 209.6v11.4l-1.3 1.4"/>
<path d="M131.7 209.6v11.4l-1.4 1.4M149.5 219.5h1.4M150.9 212.5h-1.4v21.2h-.5M155 212.5h1.4v21.2h1.4M155 219.5h1.4M149.5 226.6h1.4M155 226.6h1.4"/>
<circle cx="108.8" cy="167.3" r=".39"/>
<circle cx="148.6" cy="233.8" r=".4"/>
</g>
<path d="M130.3 222.4h-42.5l-1.4 1.4v8.5" fill="none" stroke="#000" stroke-width=".42"/>
<g fill="#000" stroke="#000" stroke-width=".13">
<circle cx="149.5" cy="219.6" r=".39"/>
<circle cx="156.4" cy="219.6" r=".39"/>
<circle cx="149.5" cy="226.7" r=".39"/>
<circle cx="156.4" cy="226.7" r=".39"/>
</g>
<g fill="#fff" stroke="#000" stroke-width=".13">
<path d="M70.6 48.5h1.4v12l-.7 .7-.7-.7z" fill-rule="evenodd"/>
<path d="M76.1 51.3h1.4v9.2l-.7 .7-.7-.7z" fill-rule="evenodd"/>
</g>
<path d="M76.8 64v36.8M94.6 159.5v1.4M93.3 160.1h1.3M129 167.3h1.3M130.3 166.5v1.4M157.8 233.7h1.4M159.2 233v1.4" fill="none" stroke="#000" stroke-width=".13"/>
<path d="M41.1 174.3h94.7v31.1h-94.7z" fill-rule="evenodd" fill="#fff" stroke="#000" stroke-width=".13"/>
<g fill="none" stroke="#000" stroke-width=".13">
<path d="M71.3 61.2v26.8M76.8 61.2v2.8M102.3 77.6l1.1 1.1M102.9 78.2v3.3M103.4 77.6l-1.1 1.1M110.5 77.6l1.1 1.1M111.1 78.2v3.3M111.6 77.6l-1.1 1.1M69.9 92.3v-4.3h2.8v4.3M71.3 98.8v3.4h2.8v5.7M73.3 95.8v-3.5h-4.1v3.5a2.04 2.04 0 0 0 2.1 2.2 2.04 2.04 0 0 0 2-2.2M101.5 88v7.1h20.6"/>
<path d="M104.2 88v7.1M104.9 84.5v3.5h-4.1v-3.5a2.03 2.03 0 0 1 2-2 2.03 2.03 0 0 1 2.1 2M109.7 88v7.1M112.5 88v7.1M113.2 84.5v3.5h-4.1v-3.5a2.03 2.03 0 0 1 2-2 2.03 2.03 0 0 1 2 2M122.1 94.4v1.4M75.4 114.4v6.2h4.1v53.7M76.8 100.8v7.1M77.5 111.4v-3.5h-4.2v3.5a2.05 2.05 0 0 0 2.1 2.1 2.05 2.05 0 0 0 2-2.1M57.6 170.1v4.2M58.9 170.1v4.2M60.3 170.1v4.2"/>
<path d="M61.7 170.1v4.2M63 170.1v4.2M64.4 170.1v4.2M65.8 170.1v4.2M67.2 170.1v4.2M68.6 170.1v4.2M69.9 170.1v4.2M71.3 170.1v4.2M72.7 170.1v4.2M73.5 169.5l1.1 1.1M74.1 170.1v4.2M74.6 169.5l-1.1 1.1"/>
<path d="M75.4 170.1v4.2M76.8 170.1v4.2M78.2 170.1v4.2M80.9 165.8v8.5M82.3 170.1v4.2M83.7 170.1v4.2M85 170.1v4.2M85.9 169.5l1.1 1.1M86.4 170.1v4.2M87 169.5l-1.1 1.1M87.8 170.1v4.2M88.6 169.5l1.1 1.1"/>
<path d="M89.1 170.1v4.2M89.7 169.5l-1.1 1.1M90 169.5l1.1 1.1M90.5 170.1v4.2M91.1 169.5l-1.1 1.1M91.9 170.1v4.2M92.7 169.5l1.1 1.1M93.3 170.1v4.2M93.8 169.5l-1.1 1.1M94.1 169.5l1.1 1.1M94.6 170.1v4.2M95.2 169.5l-1.1 1.1"/>
<path d="M112.5 170.1v4.2M113.8 170.1v4.2M115.2 170.1v4.2M116.6 170.1v4.2M122.1 170.1v4.2M123.5 170.1v4.2M124.9 170.1v4.2M126.2 170.1v4.2M43.8 205.4v4.2M45.2 205.4v4.2M46.6 205.4v4.2M47.9 205.4v4.2"/>
<path d="M49.3 205.4v4.2M50.7 205.4v4.2M52.1 205.4v4.2M53.4 205.4v4.2M54.8 205.4v4.2M56.2 205.4v4.2M57.6 205.4v4.2M58.9 205.4v4.2M60.3 205.4v4.2M61.7 205.4v4.2M63 205.4v4.2M64.4 205.4v4.2"/>
<path d="M65.8 205.4v4.2M67.2 205.4v4.2M68.6 205.4v4.2M69.4 209.1l1.1 1.1M69.9 205.4v4.2M70.5 209.1l-1.1 1.1M71.3 205.4v4.2M72.7 205.4v4.2M74.1 205.4v4.2M74.9 209.1l1.1 1.1M75.4 205.4v4.2M76 209.1l-1.1 1.1"/>
<path d="M76.3 209.1l1.1 1.1M76.8 205.4v4.2M77.4 209.1l-1.1 1.1M77.6 209.1l1.1 1.1M78.2 205.4v4.2M78.7 209.1l-1.1 1.1M79 209.1l1.1 1.1M79.5 205.4v4.2M80.1 209.1l-1.1 1.1M80.4 209.1l1.1 1.1M80.9 205.4v4.2M81.5 209.1l-1.1 1.1"/>
<path d="M81.7 209.1l1.1 1.1M82.3 205.4v4.2M82.8 209.1l-1.1 1.1M83.1 209.1l1.1 1.1M83.7 205.4v4.2M84.2 209.1l-1.1 1.1M84.5 209.1l1.1 1.1M85 205.4v4.2M85.6 209.1l-1.1 1.1M85.9 209.1l1.1 1.1M86.4 205.4v4.2M87 209.1l-1.1 1.1"/>
<path d="M89.1 205.4v4.2M90.5 205.4v4.2M91.9 205.4v4.2M93.3 205.4v4.2M94.6 205.4v4.2M96 205.4v4.2M97.4 205.4v4.2M98.7 205.4v4.2M100.1 205.4v4.2M101.5 205.4v4.2M102.9 205.4v4.2M104.2 205.4v4.2"/>
<path d="M105.6 205.4v4.2M107 205.4v4.2M108.4 205.4v4.2M109.7 205.4v4.2M111.1 205.4v4.2M112.5 205.4v4.2M113.8 205.4v4.2M115.2 205.4v4.2M116.6 205.4v4.2M118 205.4v4.2M119.4 205.4v4.2M120.7 205.4v4.2"/>
<path d="M122.1 205.4v4.2M123.5 205.4v4.2M124.9 205.4v4.2M126.2 205.4v4.2M127.6 205.4v4.2M129 205.4v4.2M130.3 205.4v4.2M131.7 205.4v4.2M150.9 219.5h1.7M150.9 212.5h1.7M152.6 211.2v2.5M152.6 218.3v2.5"/>
<path d="M153.3 211.2v2.5M153.3 218.3v2.5M153.3 219.5h1.7M153.3 212.5h1.7M150.9 226.6h1.7M152.6 225.4v2.5M153.3 226.6h1.7M153.3 225.4v2.5"/>
<circle cx="71.3" cy="98.5" r=".4"/>
<circle cx="102.8" cy="82" r=".41"/>
<circle cx="111.1" cy="82" r=".4"/>
<circle cx="75.4" cy="113.9" r=".41"/>
</g>
<path d="M72.7 222.4h-30.2l-1.4 1.4v8.5" fill="none" stroke="#000" stroke-width=".42"/>
<g fill="none" stroke="#000" stroke-width=".3">
<path d="M149.5 229.5h-.8v.2"/>
<circle cx="148.7" cy="230.3" r=".54"/>
</g>
<g fill="#a06e56" stroke="#a06e56" stroke-width=".13">
<circle cx="104.3" cy="95.2" r=".25"/>
<circle cx="109.7" cy="95.2" r=".25"/>
<circle cx="112.5" cy="95.2" r=".25"/>
<circle cx="112.5" cy="167.3" r=".25"/>
<circle cx="113.8" cy="167.3" r=".25"/>
<circle cx="115.2" cy="167.3" r=".25"/>
<circle cx="123.5" cy="167.3" r=".25"/>
<circle cx="124.9" cy="167.3" r=".25"/>
<circle cx="126.2" cy="167.3" r=".25"/>
</g>
<circle cx="71.3" cy="88.1" r=".25" fill="#000" stroke="#000" stroke-width=".13"/>
<path d="M16.2 29.7h161.5v237h-161.5z" fill="none" stroke="#000" stroke-width=".71" stroke-linecap="butt"/>
<use href="#words"/>
</svg>
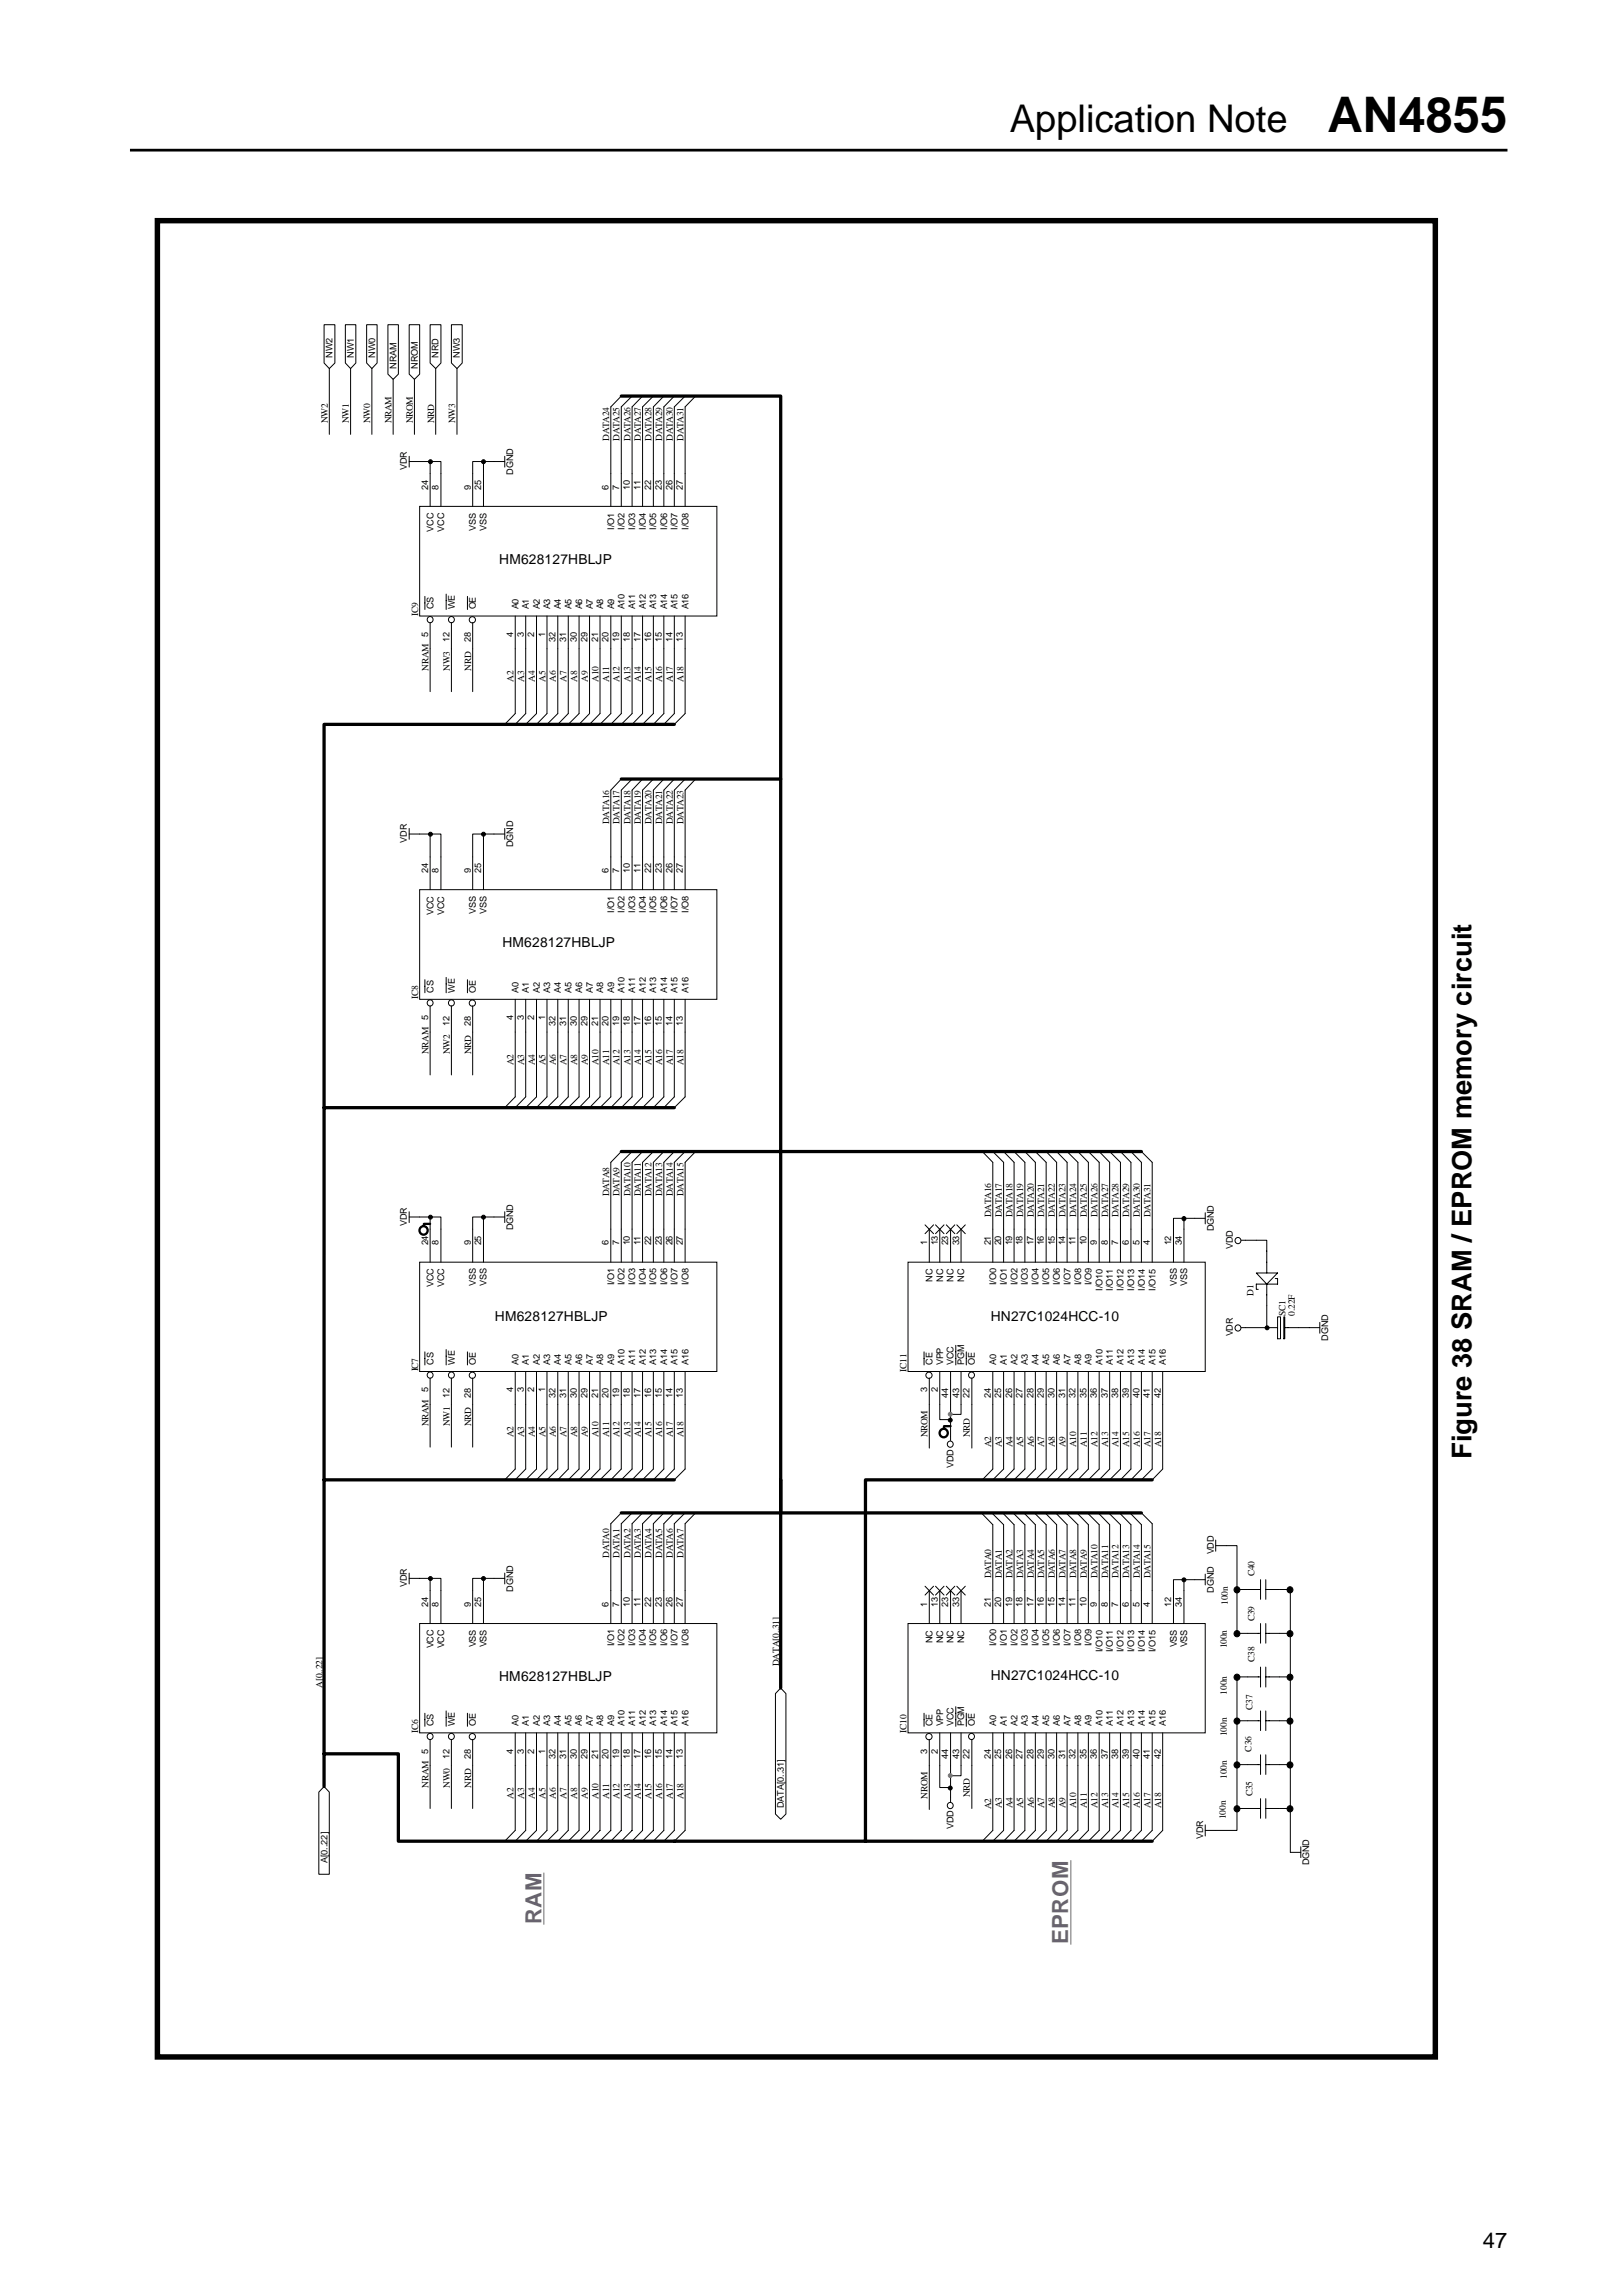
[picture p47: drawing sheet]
<svg xmlns="http://www.w3.org/2000/svg" width="210mm" height="297mm" viewBox="0 0 210 297" stroke-linecap="round" stroke-linejoin="round" font-family="sans-serif">
<defs><g id="words">
<text font-size="6.3" x="171.7" y="17.1">AN4855</text>
<text font-size="4.9" x="130.6" y="17.1">Application Note</text>
<text font-size="3.5" x="190.3" y="188.7" transform="rotate(-90 190.3 188.7)">Figure 38 SRAM / EPROM memory circuit</text>
<g font-size="2.9" fill="#695d7c">
<text x="70" y="248.9" transform="rotate(-90 70 248.9)">RAM</text>
<text x="138.2" y="251.5" transform="rotate(-90 138.2 251.5)">EPROM</text>
</g>
<text font-size="2.8" x="191.8" y="290.7">47</text>
<g font-size="1.8">
<text x="64.6" y="73">HM628127HBLJP</text>
<text x="65" y="122.5">HM628127HBLJP</text>
<text x="64" y="170.8">HM628127HBLJP</text>
<text x="128.1" y="170.8">HN27C1024HCC-10</text>
<text x="64.6" y="217.4">HM628127HBLJP</text>
<text x="128.1" y="217.3">HN27C1024HCC-10</text>
</g>
<g font-size="1.2">
<text x="43" y="46.3" transform="rotate(-90 43 46.3)">NW2</text>
<text x="45.8" y="46.3" transform="rotate(-90 45.8 46.3)">NW1</text>
<text x="48.5" y="46.3" transform="rotate(-90 48.5 46.3)">NW0</text>
<text x="51.3" y="47.7" transform="rotate(-90 51.3 47.7)">NRAM</text>
<text x="54" y="47.7" transform="rotate(-90 54 47.7)">NROM</text>
<text x="56.7" y="46.3" transform="rotate(-90 56.7 46.3)">NRD</text>
<text x="59.5" y="46.3" transform="rotate(-90 59.5 46.3)">NW3</text>
<text x="42.4" y="54.7" transform="rotate(-90 42.4 54.7)">NW2</text>
<text x="45.1" y="54.7" transform="rotate(-90 45.1 54.7)">NW1</text>
<text x="47.9" y="54.7" transform="rotate(-90 47.9 54.7)">NW0</text>
<text x="50.6" y="54.7" transform="rotate(-90 50.6 54.7)">NRAM</text>
<text x="53.4" y="54.7" transform="rotate(-90 53.4 54.7)">NROM</text>
<text x="56.1" y="54.7" transform="rotate(-90 56.1 54.7)">NRD</text>
<text x="58.8" y="54.7" transform="rotate(-90 58.8 54.7)">NW3</text>
<text x="78.8" y="57" transform="rotate(-90 78.8 57)">DATA24</text>
<text x="80.1" y="57" transform="rotate(-90 80.1 57)">DATA25</text>
<text x="81.5" y="57" transform="rotate(-90 81.5 57)">DATA26</text>
<text x="82.9" y="57" transform="rotate(-90 82.9 57)">DATA27</text>
<text x="84.2" y="57" transform="rotate(-90 84.2 57)">DATA28</text>
<text x="85.6" y="57" transform="rotate(-90 85.6 57)">DATA29</text>
<text x="87" y="57" transform="rotate(-90 87 57)">DATA30</text>
<text x="88.4" y="57" transform="rotate(-90 88.4 57)">DATA31</text>
<text x="52.6" y="60.8" transform="rotate(-90 52.6 60.8)">VDR</text>
<text x="55.4" y="63.4" transform="rotate(-90 55.4 63.4)">24</text>
<text x="56.7" y="63.4" transform="rotate(-90 56.7 63.4)">8</text>
<text x="60.9" y="63.4" transform="rotate(-90 60.9 63.4)">9</text>
<text x="62.2" y="63.4" transform="rotate(-90 62.2 63.4)">25</text>
<text x="66.4" y="61.4" transform="rotate(-90 66.4 61.4)">DGND</text>
<text x="78.7" y="63.4" transform="rotate(-90 78.7 63.4)">6</text>
<text x="80.1" y="63.4" transform="rotate(-90 80.1 63.4)">7</text>
<text x="81.5" y="63.4" transform="rotate(-90 81.5 63.4)">10</text>
<text x="82.9" y="63.4" transform="rotate(-90 82.9 63.4)">11</text>
<text x="84.2" y="63.4" transform="rotate(-90 84.2 63.4)">22</text>
<text x="85.6" y="63.4" transform="rotate(-90 85.6 63.4)">23</text>
<text x="87" y="63.4" transform="rotate(-90 87 63.4)">26</text>
<text x="88.3" y="63.4" transform="rotate(-90 88.3 63.4)">27</text>
<text x="56.1" y="68.8" transform="rotate(-90 56.1 68.8)">VCC</text>
<text x="57.5" y="68.8" transform="rotate(-90 57.5 68.8)">VCC</text>
<text x="61.6" y="68.6" transform="rotate(-90 61.6 68.6)">VSS</text>
<text x="62.9" y="68.6" transform="rotate(-90 62.9 68.6)">VSS</text>
<text x="79.4" y="68.5" transform="rotate(-90 79.4 68.5)">I/O1</text>
<text x="80.8" y="68.5" transform="rotate(-90 80.8 68.5)">I/O2</text>
<text x="82.1" y="68.5" transform="rotate(-90 82.1 68.5)">I/O3</text>
<text x="83.5" y="68.5" transform="rotate(-90 83.5 68.5)">I/O4</text>
<text x="84.9" y="68.5" transform="rotate(-90 84.9 68.5)">I/O5</text>
<text x="86.3" y="68.5" transform="rotate(-90 86.3 68.5)">I/O6</text>
<text x="87.6" y="68.5" transform="rotate(-90 87.6 68.5)">I/O7</text>
<text x="89" y="68.5" transform="rotate(-90 89 68.5)">I/O8</text>
<text x="54.1" y="79.7" transform="rotate(-90 54.1 79.7)">IC9</text>
<text x="55.4" y="82.4" transform="rotate(-90 55.4 82.4)">5</text>
<text x="56.1" y="78.8" transform="rotate(-90 56.1 78.8)">CS</text>
<text x="58.1" y="83.1" transform="rotate(-90 58.1 83.1)">12</text>
<text x="58.8" y="78.8" transform="rotate(-90 58.8 78.8)">WE</text>
<text x="60.9" y="83.1" transform="rotate(-90 60.9 83.1)">28</text>
<text x="61.6" y="78.8" transform="rotate(-90 61.6 78.8)">OE</text>
<text x="66.4" y="82.4" transform="rotate(-90 66.4 82.4)">4</text>
<text x="67.1" y="78.8" transform="rotate(-90 67.1 78.8)">A0</text>
<text x="67.7" y="82.4" transform="rotate(-90 67.7 82.4)">3</text>
<text x="68.4" y="78.8" transform="rotate(-90 68.4 78.8)">A1</text>
<text x="69.1" y="82.4" transform="rotate(-90 69.1 82.4)">2</text>
<text x="69.8" y="78.8" transform="rotate(-90 69.8 78.8)">A2</text>
<text x="70.5" y="82.4" transform="rotate(-90 70.5 82.4)">1</text>
<text x="71.2" y="78.8" transform="rotate(-90 71.2 78.8)">A3</text>
<text x="71.8" y="83.1" transform="rotate(-90 71.8 83.1)">32</text>
<text x="72.5" y="78.8" transform="rotate(-90 72.5 78.8)">A4</text>
<text x="73.2" y="83.1" transform="rotate(-90 73.2 83.1)">31</text>
<text x="73.9" y="78.8" transform="rotate(-90 73.9 78.8)">A5</text>
<text x="74.6" y="83.1" transform="rotate(-90 74.6 83.1)">30</text>
<text x="75.3" y="78.8" transform="rotate(-90 75.3 78.8)">A6</text>
<text x="76" y="83.1" transform="rotate(-90 76 83.1)">29</text>
<text x="76.7" y="78.8" transform="rotate(-90 76.7 78.8)">A7</text>
<text x="77.3" y="83.1" transform="rotate(-90 77.3 83.1)">21</text>
<text x="78" y="78.8" transform="rotate(-90 78 78.8)">A8</text>
<text x="78.7" y="83.1" transform="rotate(-90 78.7 83.1)">20</text>
<text x="79.4" y="78.8" transform="rotate(-90 79.4 78.8)">A9</text>
<text x="80.1" y="83.1" transform="rotate(-90 80.1 83.1)">19</text>
<text x="80.8" y="78.8" transform="rotate(-90 80.8 78.8)">A10</text>
<text x="81.5" y="83.1" transform="rotate(-90 81.5 83.1)">18</text>
<text x="82.1" y="78.8" transform="rotate(-90 82.1 78.8)">A11</text>
<text x="82.8" y="83.1" transform="rotate(-90 82.8 83.1)">17</text>
<text x="83.5" y="78.8" transform="rotate(-90 83.5 78.8)">A12</text>
<text x="84.2" y="83.1" transform="rotate(-90 84.2 83.1)">16</text>
<text x="84.9" y="78.8" transform="rotate(-90 84.9 78.8)">A13</text>
<text x="85.6" y="83.1" transform="rotate(-90 85.6 83.1)">15</text>
<text x="86.3" y="78.8" transform="rotate(-90 86.3 78.8)">A14</text>
<text x="87" y="83.1" transform="rotate(-90 87 83.1)">14</text>
<text x="87.6" y="78.8" transform="rotate(-90 87.6 78.8)">A15</text>
<text x="88.3" y="83.1" transform="rotate(-90 88.3 83.1)">13</text>
<text x="89" y="78.8" transform="rotate(-90 89 78.8)">A16</text>
<text x="55.4" y="86.7" transform="rotate(-90 55.4 86.7)">NRAM</text>
<text x="58.2" y="86.7" transform="rotate(-90 58.2 86.7)">NW3</text>
<text x="60.9" y="86.7" transform="rotate(-90 60.9 86.7)">NRD</text>
<text x="66.4" y="88.2" transform="rotate(-90 66.4 88.2)">A2</text>
<text x="67.8" y="88.2" transform="rotate(-90 67.8 88.2)">A3</text>
<text x="69.2" y="88.2" transform="rotate(-90 69.2 88.2)">A4</text>
<text x="70.5" y="88.2" transform="rotate(-90 70.5 88.2)">A5</text>
<text x="71.9" y="88.2" transform="rotate(-90 71.9 88.2)">A6</text>
<text x="73.3" y="88.2" transform="rotate(-90 73.3 88.2)">A7</text>
<text x="74.6" y="88.2" transform="rotate(-90 74.6 88.2)">A8</text>
<text x="76" y="88.2" transform="rotate(-90 76 88.2)">A9</text>
<text x="77.4" y="88.2" transform="rotate(-90 77.4 88.2)">A10</text>
<text x="78.8" y="88.2" transform="rotate(-90 78.8 88.2)">A11</text>
<text x="80.1" y="88.2" transform="rotate(-90 80.1 88.2)">A12</text>
<text x="81.5" y="88.2" transform="rotate(-90 81.5 88.2)">A13</text>
<text x="82.9" y="88.2" transform="rotate(-90 82.9 88.2)">A14</text>
<text x="84.2" y="88.2" transform="rotate(-90 84.2 88.2)">A15</text>
<text x="85.6" y="88.2" transform="rotate(-90 85.6 88.2)">A16</text>
<text x="87" y="88.2" transform="rotate(-90 87 88.2)">A17</text>
<text x="88.4" y="88.2" transform="rotate(-90 88.4 88.2)">A18</text>
<text x="78.8" y="106.6" transform="rotate(-90 78.8 106.6)">DATA16</text>
<text x="80.1" y="106.6" transform="rotate(-90 80.1 106.6)">DATA17</text>
<text x="81.5" y="106.6" transform="rotate(-90 81.5 106.6)">DATA18</text>
<text x="82.9" y="106.6" transform="rotate(-90 82.9 106.6)">DATA19</text>
<text x="84.2" y="106.6" transform="rotate(-90 84.2 106.6)">DATA20</text>
<text x="85.6" y="106.6" transform="rotate(-90 85.6 106.6)">DATA21</text>
<text x="87" y="106.6" transform="rotate(-90 87 106.6)">DATA22</text>
<text x="88.4" y="106.6" transform="rotate(-90 88.4 106.6)">DATA23</text>
<text x="52.6" y="109" transform="rotate(-90 52.6 109)">VDR</text>
<text x="55.4" y="112.9" transform="rotate(-90 55.4 112.9)">24</text>
<text x="56.7" y="112.9" transform="rotate(-90 56.7 112.9)">8</text>
<text x="60.9" y="112.9" transform="rotate(-90 60.9 112.9)">9</text>
<text x="62.2" y="112.9" transform="rotate(-90 62.2 112.9)">25</text>
<text x="66.4" y="109.6" transform="rotate(-90 66.4 109.6)">DGND</text>
<text x="78.7" y="112.9" transform="rotate(-90 78.7 112.9)">6</text>
<text x="80.1" y="112.9" transform="rotate(-90 80.1 112.9)">7</text>
<text x="81.5" y="112.9" transform="rotate(-90 81.5 112.9)">10</text>
<text x="82.8" y="112.9" transform="rotate(-90 82.8 112.9)">11</text>
<text x="84.2" y="112.9" transform="rotate(-90 84.2 112.9)">22</text>
<text x="85.6" y="112.9" transform="rotate(-90 85.6 112.9)">23</text>
<text x="87" y="112.9" transform="rotate(-90 87 112.9)">26</text>
<text x="88.3" y="112.9" transform="rotate(-90 88.3 112.9)">27</text>
<text x="56.1" y="118.3" transform="rotate(-90 56.1 118.3)">VCC</text>
<text x="57.4" y="118.3" transform="rotate(-90 57.4 118.3)">VCC</text>
<text x="61.6" y="118.2" transform="rotate(-90 61.6 118.2)">VSS</text>
<text x="62.9" y="118.2" transform="rotate(-90 62.9 118.2)">VSS</text>
<text x="79.4" y="118.1" transform="rotate(-90 79.4 118.1)">I/O1</text>
<text x="80.8" y="118.1" transform="rotate(-90 80.8 118.1)">I/O2</text>
<text x="82.1" y="118.1" transform="rotate(-90 82.1 118.1)">I/O3</text>
<text x="83.5" y="118.1" transform="rotate(-90 83.5 118.1)">I/O4</text>
<text x="84.9" y="118.1" transform="rotate(-90 84.9 118.1)">I/O5</text>
<text x="86.3" y="118.1" transform="rotate(-90 86.3 118.1)">I/O6</text>
<text x="87.6" y="118.1" transform="rotate(-90 87.6 118.1)">I/O7</text>
<text x="89" y="118.1" transform="rotate(-90 89 118.1)">I/O8</text>
<text x="54.1" y="129.2" transform="rotate(-90 54.1 129.2)">IC8</text>
<text x="55.4" y="131.9" transform="rotate(-90 55.4 131.9)">5</text>
<text x="56.1" y="128.4" transform="rotate(-90 56.1 128.4)">CS</text>
<text x="58.8" y="128.4" transform="rotate(-90 58.8 128.4)">WE</text>
<text x="61.6" y="128.4" transform="rotate(-90 61.6 128.4)">OE</text>
<text x="66.4" y="131.9" transform="rotate(-90 66.4 131.9)">4</text>
<text x="67.1" y="128.4" transform="rotate(-90 67.1 128.4)">A0</text>
<text x="67.7" y="131.9" transform="rotate(-90 67.7 131.9)">3</text>
<text x="68.4" y="128.4" transform="rotate(-90 68.4 128.4)">A1</text>
<text x="69.1" y="131.9" transform="rotate(-90 69.1 131.9)">2</text>
<text x="69.8" y="128.4" transform="rotate(-90 69.8 128.4)">A2</text>
<text x="70.5" y="131.9" transform="rotate(-90 70.5 131.9)">1</text>
<text x="71.2" y="128.4" transform="rotate(-90 71.2 128.4)">A3</text>
<text x="72.5" y="128.4" transform="rotate(-90 72.5 128.4)">A4</text>
<text x="73.9" y="128.4" transform="rotate(-90 73.9 128.4)">A5</text>
<text x="75.3" y="128.4" transform="rotate(-90 75.3 128.4)">A6</text>
<text x="76.7" y="128.4" transform="rotate(-90 76.7 128.4)">A7</text>
<text x="78" y="128.4" transform="rotate(-90 78 128.4)">A8</text>
<text x="79.4" y="128.4" transform="rotate(-90 79.4 128.4)">A9</text>
<text x="80.8" y="128.4" transform="rotate(-90 80.8 128.4)">A10</text>
<text x="82.1" y="128.4" transform="rotate(-90 82.1 128.4)">A11</text>
<text x="83.5" y="128.4" transform="rotate(-90 83.5 128.4)">A12</text>
<text x="84.9" y="128.4" transform="rotate(-90 84.9 128.4)">A13</text>
<text x="86.3" y="128.4" transform="rotate(-90 86.3 128.4)">A14</text>
<text x="87.6" y="128.4" transform="rotate(-90 87.6 128.4)">A15</text>
<text x="89" y="128.4" transform="rotate(-90 89 128.4)">A16</text>
<text x="55.4" y="136.3" transform="rotate(-90 55.4 136.3)">NRAM</text>
<text x="58.1" y="132.6" transform="rotate(-90 58.1 132.6)">12</text>
<text x="58.2" y="136.3" transform="rotate(-90 58.2 136.3)">NW2</text>
<text x="60.9" y="132.6" transform="rotate(-90 60.9 132.6)">28</text>
<text x="60.9" y="136.3" transform="rotate(-90 60.9 136.3)">NRD</text>
<text x="66.4" y="137.8" transform="rotate(-90 66.4 137.8)">A2</text>
<text x="67.8" y="137.8" transform="rotate(-90 67.8 137.8)">A3</text>
<text x="69.2" y="137.8" transform="rotate(-90 69.2 137.8)">A4</text>
<text x="70.5" y="137.8" transform="rotate(-90 70.5 137.8)">A5</text>
<text x="71.8" y="132.6" transform="rotate(-90 71.8 132.6)">32</text>
<text x="71.9" y="137.8" transform="rotate(-90 71.9 137.8)">A6</text>
<text x="73.2" y="132.6" transform="rotate(-90 73.2 132.6)">31</text>
<text x="73.3" y="137.8" transform="rotate(-90 73.3 137.8)">A7</text>
<text x="74.6" y="132.6" transform="rotate(-90 74.6 132.6)">30</text>
<text x="74.6" y="137.8" transform="rotate(-90 74.6 137.8)">A8</text>
<text x="76" y="132.6" transform="rotate(-90 76 132.6)">29</text>
<text x="76" y="137.8" transform="rotate(-90 76 137.8)">A9</text>
<text x="77.3" y="132.6" transform="rotate(-90 77.3 132.6)">21</text>
<text x="77.4" y="137.8" transform="rotate(-90 77.4 137.8)">A10</text>
<text x="78.7" y="132.6" transform="rotate(-90 78.7 132.6)">20</text>
<text x="78.8" y="137.8" transform="rotate(-90 78.8 137.8)">A11</text>
<text x="80.1" y="132.6" transform="rotate(-90 80.1 132.6)">19</text>
<text x="80.1" y="137.8" transform="rotate(-90 80.1 137.8)">A12</text>
<text x="81.5" y="132.6" transform="rotate(-90 81.5 132.6)">18</text>
<text x="81.5" y="137.8" transform="rotate(-90 81.5 137.8)">A13</text>
<text x="82.8" y="132.6" transform="rotate(-90 82.8 132.6)">17</text>
<text x="82.9" y="137.8" transform="rotate(-90 82.9 137.8)">A14</text>
<text x="84.2" y="132.6" transform="rotate(-90 84.2 132.6)">16</text>
<text x="84.2" y="137.8" transform="rotate(-90 84.2 137.8)">A15</text>
<text x="85.6" y="132.6" transform="rotate(-90 85.6 132.6)">15</text>
<text x="85.6" y="137.8" transform="rotate(-90 85.6 137.8)">A16</text>
<text x="87" y="132.6" transform="rotate(-90 87 132.6)">14</text>
<text x="87" y="137.8" transform="rotate(-90 87 137.8)">A17</text>
<text x="88.3" y="132.6" transform="rotate(-90 88.3 132.6)">13</text>
<text x="88.4" y="137.8" transform="rotate(-90 88.4 137.8)">A18</text>
<text x="78.8" y="154.7" transform="rotate(-90 78.8 154.7)">DATA8</text>
<text x="80.1" y="154.7" transform="rotate(-90 80.1 154.7)">DATA9</text>
<text x="81.5" y="154.7" transform="rotate(-90 81.5 154.7)">DATA10</text>
<text x="82.9" y="154.7" transform="rotate(-90 82.9 154.7)">DATA11</text>
<text x="84.2" y="154.7" transform="rotate(-90 84.2 154.7)">DATA12</text>
<text x="85.6" y="154.7" transform="rotate(-90 85.6 154.7)">DATA13</text>
<text x="87" y="154.7" transform="rotate(-90 87 154.7)">DATA14</text>
<text x="88.4" y="154.7" transform="rotate(-90 88.4 154.7)">DATA15</text>
<text x="52.6" y="158.5" transform="rotate(-90 52.6 158.5)">VDR</text>
<text x="55.4" y="161.1" transform="rotate(-90 55.4 161.1)">24</text>
<text x="56.7" y="161.1" transform="rotate(-90 56.7 161.1)">8</text>
<text x="60.9" y="161.1" transform="rotate(-90 60.9 161.1)">9</text>
<text x="62.2" y="161.1" transform="rotate(-90 62.2 161.1)">25</text>
<text x="66.4" y="159.1" transform="rotate(-90 66.4 159.1)">DGND</text>
<text x="78.7" y="161.1" transform="rotate(-90 78.7 161.1)">6</text>
<text x="80.1" y="161.1" transform="rotate(-90 80.1 161.1)">7</text>
<text x="81.5" y="161.1" transform="rotate(-90 81.5 161.1)">10</text>
<text x="82.8" y="161.1" transform="rotate(-90 82.8 161.1)">11</text>
<text x="84.2" y="161.1" transform="rotate(-90 84.2 161.1)">22</text>
<text x="85.6" y="161.1" transform="rotate(-90 85.6 161.1)">23</text>
<text x="87" y="161.1" transform="rotate(-90 87 161.1)">26</text>
<text x="88.3" y="161.1" transform="rotate(-90 88.3 161.1)">27</text>
<text x="119.9" y="161.1" transform="rotate(-90 119.9 161.1)">1</text>
<text x="121.3" y="161.1" transform="rotate(-90 121.3 161.1)">13</text>
<text x="122.6" y="161.1" transform="rotate(-90 122.6 161.1)">23</text>
<text x="124" y="161.1" transform="rotate(-90 124 161.1)">33</text>
<text x="128.1" y="161.1" transform="rotate(-90 128.1 161.1)">21</text>
<text x="128.2" y="157.4" transform="rotate(-90 128.2 157.4)">DATA16</text>
<text x="129.5" y="161.1" transform="rotate(-90 129.5 161.1)">20</text>
<text x="129.6" y="157.4" transform="rotate(-90 129.6 157.4)">DATA17</text>
<text x="130.9" y="161.1" transform="rotate(-90 130.9 161.1)">19</text>
<text x="130.9" y="157.4" transform="rotate(-90 130.9 157.4)">DATA18</text>
<text x="132.3" y="161.1" transform="rotate(-90 132.3 161.1)">18</text>
<text x="132.3" y="157.4" transform="rotate(-90 132.3 157.4)">DATA19</text>
<text x="133.6" y="161.1" transform="rotate(-90 133.6 161.1)">17</text>
<text x="133.7" y="157.4" transform="rotate(-90 133.7 157.4)">DATA20</text>
<text x="135" y="161.1" transform="rotate(-90 135 161.1)">16</text>
<text x="135" y="157.4" transform="rotate(-90 135 157.4)">DATA21</text>
<text x="136.4" y="161.1" transform="rotate(-90 136.4 161.1)">15</text>
<text x="136.4" y="157.4" transform="rotate(-90 136.4 157.4)">DATA22</text>
<text x="137.8" y="161.1" transform="rotate(-90 137.8 161.1)">14</text>
<text x="137.8" y="157.4" transform="rotate(-90 137.8 157.4)">DATA23</text>
<text x="139.1" y="161.1" transform="rotate(-90 139.1 161.1)">11</text>
<text x="139.2" y="157.4" transform="rotate(-90 139.2 157.4)">DATA24</text>
<text x="140.5" y="161.1" transform="rotate(-90 140.5 161.1)">10</text>
<text x="140.5" y="157.4" transform="rotate(-90 140.5 157.4)">DATA25</text>
<text x="141.9" y="161.1" transform="rotate(-90 141.9 161.1)">9</text>
<text x="141.9" y="157.4" transform="rotate(-90 141.9 157.4)">DATA26</text>
<text x="143.3" y="161.1" transform="rotate(-90 143.3 161.1)">8</text>
<text x="143.3" y="157.4" transform="rotate(-90 143.3 157.4)">DATA27</text>
<text x="144.6" y="161.1" transform="rotate(-90 144.6 161.1)">7</text>
<text x="144.7" y="157.4" transform="rotate(-90 144.7 157.4)">DATA28</text>
<text x="146" y="161.1" transform="rotate(-90 146 161.1)">6</text>
<text x="146.1" y="157.4" transform="rotate(-90 146.1 157.4)">DATA29</text>
<text x="147.4" y="161.1" transform="rotate(-90 147.4 161.1)">5</text>
<text x="147.4" y="157.4" transform="rotate(-90 147.4 157.4)">DATA30</text>
<text x="148.7" y="161.1" transform="rotate(-90 148.7 161.1)">4</text>
<text x="148.8" y="157.4" transform="rotate(-90 148.8 157.4)">DATA31</text>
<text x="151.5" y="161.1" transform="rotate(-90 151.5 161.1)">12</text>
<text x="152.9" y="161.1" transform="rotate(-90 152.9 161.1)">34</text>
<text x="157" y="159.3" transform="rotate(-90 157 159.3)">DGND</text>
<text x="159.4" y="161.5" transform="rotate(-90 159.4 161.5)">VDD</text>
<text x="56.1" y="166.5" transform="rotate(-90 56.1 166.5)">VCC</text>
<text x="57.4" y="166.5" transform="rotate(-90 57.4 166.5)">VCC</text>
<text x="61.6" y="166.3" transform="rotate(-90 61.6 166.3)">VSS</text>
<text x="62.9" y="166.3" transform="rotate(-90 62.9 166.3)">VSS</text>
<text x="79.4" y="166.2" transform="rotate(-90 79.4 166.2)">I/O1</text>
<text x="80.8" y="166.2" transform="rotate(-90 80.8 166.2)">I/O2</text>
<text x="82.1" y="166.2" transform="rotate(-90 82.1 166.2)">I/O3</text>
<text x="83.5" y="166.2" transform="rotate(-90 83.5 166.2)">I/O4</text>
<text x="84.9" y="166.2" transform="rotate(-90 84.9 166.2)">I/O5</text>
<text x="86.3" y="166.2" transform="rotate(-90 86.3 166.2)">I/O6</text>
<text x="87.6" y="166.2" transform="rotate(-90 87.6 166.2)">I/O7</text>
<text x="89" y="166.2" transform="rotate(-90 89 166.2)">I/O8</text>
<text x="120.6" y="165.8" transform="rotate(-90 120.6 165.8)">NC</text>
<text x="122" y="165.8" transform="rotate(-90 122 165.8)">NC</text>
<text x="123.3" y="165.8" transform="rotate(-90 123.3 165.8)">NC</text>
<text x="124.7" y="165.8" transform="rotate(-90 124.7 165.8)">NC</text>
<text x="128.8" y="166.2" transform="rotate(-90 128.8 166.2)">I/O0</text>
<text x="130.2" y="166.2" transform="rotate(-90 130.2 166.2)">I/O1</text>
<text x="131.6" y="166.2" transform="rotate(-90 131.6 166.2)">I/O2</text>
<text x="132.9" y="166.2" transform="rotate(-90 132.9 166.2)">I/O3</text>
<text x="134.3" y="166.2" transform="rotate(-90 134.3 166.2)">I/O4</text>
<text x="135.7" y="166.2" transform="rotate(-90 135.7 166.2)">I/O5</text>
<text x="137.1" y="166.2" transform="rotate(-90 137.1 166.2)">I/O6</text>
<text x="138.4" y="166.2" transform="rotate(-90 138.4 166.2)">I/O7</text>
<text x="139.8" y="166.2" transform="rotate(-90 139.8 166.2)">I/O8</text>
<text x="141.2" y="166.2" transform="rotate(-90 141.2 166.2)">I/O9</text>
<text x="142.6" y="166.9" transform="rotate(-90 142.6 166.9)">I/O10</text>
<text x="143.9" y="166.9" transform="rotate(-90 143.9 166.9)">I/O11</text>
<text x="145.3" y="166.9" transform="rotate(-90 145.3 166.9)">I/O12</text>
<text x="146.7" y="166.9" transform="rotate(-90 146.7 166.9)">I/O13</text>
<text x="148" y="166.9" transform="rotate(-90 148 166.9)">I/O14</text>
<text x="149.4" y="166.9" transform="rotate(-90 149.4 166.9)">I/O15</text>
<text x="152.2" y="166.3" transform="rotate(-90 152.2 166.3)">VSS</text>
<text x="153.5" y="166.3" transform="rotate(-90 153.5 166.3)">VSS</text>
<text x="162.1" y="167.6" transform="rotate(-90 162.1 167.6)">D1</text>
<text x="159.4" y="172.8" transform="rotate(-90 159.4 172.8)">VDR</text>
<text x="166.2" y="170.2" transform="rotate(-90 166.2 170.2)">SC1</text>
<text x="167.5" y="170.2" transform="rotate(-90 167.5 170.2)">0.22F</text>
<text x="171.8" y="173.4" transform="rotate(-90 171.8 173.4)">DGND</text>
<text x="54.1" y="177.4" transform="rotate(-90 54.1 177.4)">IC7</text>
<text x="56.1" y="176.5" transform="rotate(-90 56.1 176.5)">CS</text>
<text x="58.8" y="176.5" transform="rotate(-90 58.8 176.5)">WE</text>
<text x="61.6" y="176.5" transform="rotate(-90 61.6 176.5)">OE</text>
<text x="67.1" y="176.5" transform="rotate(-90 67.1 176.5)">A0</text>
<text x="68.4" y="176.5" transform="rotate(-90 68.4 176.5)">A1</text>
<text x="69.8" y="176.5" transform="rotate(-90 69.8 176.5)">A2</text>
<text x="71.2" y="176.5" transform="rotate(-90 71.2 176.5)">A3</text>
<text x="72.5" y="176.5" transform="rotate(-90 72.5 176.5)">A4</text>
<text x="73.9" y="176.5" transform="rotate(-90 73.9 176.5)">A5</text>
<text x="75.3" y="176.5" transform="rotate(-90 75.3 176.5)">A6</text>
<text x="76.7" y="176.5" transform="rotate(-90 76.7 176.5)">A7</text>
<text x="78" y="176.5" transform="rotate(-90 78 176.5)">A8</text>
<text x="79.4" y="176.5" transform="rotate(-90 79.4 176.5)">A9</text>
<text x="80.8" y="176.5" transform="rotate(-90 80.8 176.5)">A10</text>
<text x="82.1" y="176.5" transform="rotate(-90 82.1 176.5)">A11</text>
<text x="83.5" y="176.5" transform="rotate(-90 83.5 176.5)">A12</text>
<text x="84.9" y="176.5" transform="rotate(-90 84.9 176.5)">A13</text>
<text x="86.3" y="176.5" transform="rotate(-90 86.3 176.5)">A14</text>
<text x="87.6" y="176.5" transform="rotate(-90 87.6 176.5)">A15</text>
<text x="89" y="176.5" transform="rotate(-90 89 176.5)">A16</text>
<text x="117.2" y="177.4" transform="rotate(-90 117.2 177.4)">IC11</text>
<text x="120.6" y="176.5" transform="rotate(-90 120.6 176.5)">CE</text>
<text x="122" y="176.5" transform="rotate(-90 122 176.5)">VPP</text>
<text x="123.3" y="176.5" transform="rotate(-90 123.3 176.5)">VCC</text>
<text x="124.7" y="176.5" transform="rotate(-90 124.7 176.5)">PGM</text>
<text x="126.1" y="176.5" transform="rotate(-90 126.1 176.5)">OE</text>
<text x="128.8" y="176.5" transform="rotate(-90 128.8 176.5)">A0</text>
<text x="130.2" y="176.5" transform="rotate(-90 130.2 176.5)">A1</text>
<text x="131.6" y="176.5" transform="rotate(-90 131.6 176.5)">A2</text>
<text x="132.9" y="176.5" transform="rotate(-90 132.9 176.5)">A3</text>
<text x="134.3" y="176.5" transform="rotate(-90 134.3 176.5)">A4</text>
<text x="135.7" y="176.5" transform="rotate(-90 135.7 176.5)">A5</text>
<text x="137.1" y="176.5" transform="rotate(-90 137.1 176.5)">A6</text>
<text x="138.4" y="176.5" transform="rotate(-90 138.4 176.5)">A7</text>
<text x="139.8" y="176.5" transform="rotate(-90 139.8 176.5)">A8</text>
<text x="141.2" y="176.5" transform="rotate(-90 141.2 176.5)">A9</text>
<text x="142.6" y="176.5" transform="rotate(-90 142.6 176.5)">A10</text>
<text x="143.9" y="176.5" transform="rotate(-90 143.9 176.5)">A11</text>
<text x="145.3" y="176.5" transform="rotate(-90 145.3 176.5)">A12</text>
<text x="146.7" y="176.5" transform="rotate(-90 146.7 176.5)">A13</text>
<text x="148" y="176.5" transform="rotate(-90 148 176.5)">A14</text>
<text x="149.4" y="176.5" transform="rotate(-90 149.4 176.5)">A15</text>
<text x="150.8" y="176.5" transform="rotate(-90 150.8 176.5)">A16</text>
<text x="55.4" y="180.1" transform="rotate(-90 55.4 180.1)">5</text>
<text x="55.4" y="184.4" transform="rotate(-90 55.4 184.4)">NRAM</text>
<text x="58.1" y="180.8" transform="rotate(-90 58.1 180.8)">12</text>
<text x="58.2" y="184.4" transform="rotate(-90 58.2 184.4)">NW1</text>
<text x="60.9" y="180.8" transform="rotate(-90 60.9 180.8)">28</text>
<text x="60.9" y="184.4" transform="rotate(-90 60.9 184.4)">NRD</text>
<text x="66.4" y="180.1" transform="rotate(-90 66.4 180.1)">4</text>
<text x="66.4" y="185.9" transform="rotate(-90 66.4 185.9)">A2</text>
<text x="67.7" y="180.1" transform="rotate(-90 67.7 180.1)">3</text>
<text x="67.8" y="185.9" transform="rotate(-90 67.8 185.9)">A3</text>
<text x="69.1" y="180.1" transform="rotate(-90 69.1 180.1)">2</text>
<text x="69.2" y="185.9" transform="rotate(-90 69.2 185.9)">A4</text>
<text x="70.5" y="180.1" transform="rotate(-90 70.5 180.1)">1</text>
<text x="70.5" y="185.9" transform="rotate(-90 70.5 185.9)">A5</text>
<text x="71.8" y="180.8" transform="rotate(-90 71.8 180.8)">32</text>
<text x="71.9" y="185.9" transform="rotate(-90 71.9 185.9)">A6</text>
<text x="73.2" y="180.8" transform="rotate(-90 73.2 180.8)">31</text>
<text x="73.3" y="185.9" transform="rotate(-90 73.3 185.9)">A7</text>
<text x="74.6" y="180.8" transform="rotate(-90 74.6 180.8)">30</text>
<text x="74.6" y="185.9" transform="rotate(-90 74.6 185.9)">A8</text>
<text x="76" y="180.8" transform="rotate(-90 76 180.8)">29</text>
<text x="76" y="185.9" transform="rotate(-90 76 185.9)">A9</text>
<text x="77.3" y="180.8" transform="rotate(-90 77.3 180.8)">21</text>
<text x="77.4" y="185.9" transform="rotate(-90 77.4 185.9)">A10</text>
<text x="78.7" y="180.8" transform="rotate(-90 78.7 180.8)">20</text>
<text x="78.8" y="185.9" transform="rotate(-90 78.8 185.9)">A11</text>
<text x="80.1" y="180.8" transform="rotate(-90 80.1 180.8)">19</text>
<text x="80.1" y="185.9" transform="rotate(-90 80.1 185.9)">A12</text>
<text x="81.5" y="180.8" transform="rotate(-90 81.5 180.8)">18</text>
<text x="81.5" y="185.9" transform="rotate(-90 81.5 185.9)">A13</text>
<text x="82.8" y="180.8" transform="rotate(-90 82.8 180.8)">17</text>
<text x="82.9" y="185.9" transform="rotate(-90 82.9 185.9)">A14</text>
<text x="84.2" y="180.8" transform="rotate(-90 84.2 180.8)">16</text>
<text x="84.2" y="185.9" transform="rotate(-90 84.2 185.9)">A15</text>
<text x="85.6" y="180.8" transform="rotate(-90 85.6 180.8)">15</text>
<text x="85.6" y="185.9" transform="rotate(-90 85.6 185.9)">A16</text>
<text x="87" y="180.8" transform="rotate(-90 87 180.8)">14</text>
<text x="87" y="185.9" transform="rotate(-90 87 185.9)">A17</text>
<text x="88.3" y="180.8" transform="rotate(-90 88.3 180.8)">13</text>
<text x="88.4" y="185.9" transform="rotate(-90 88.4 185.9)">A18</text>
<text x="119.9" y="180.1" transform="rotate(-90 119.9 180.1)">3</text>
<text x="120" y="185.9" transform="rotate(-90 120 185.9)">NROM</text>
<text x="121.3" y="180.1" transform="rotate(-90 121.3 180.1)">2</text>
<text x="122.6" y="180.8" transform="rotate(-90 122.6 180.8)">44</text>
<text x="124" y="180.8" transform="rotate(-90 124 180.8)">43</text>
<text x="125.4" y="180.8" transform="rotate(-90 125.4 180.8)">22</text>
<text x="125.4" y="185.9" transform="rotate(-90 125.4 185.9)">NRD</text>
<text x="128.1" y="180.8" transform="rotate(-90 128.1 180.8)">24</text>
<text x="129.5" y="180.8" transform="rotate(-90 129.5 180.8)">25</text>
<text x="130.9" y="180.8" transform="rotate(-90 130.9 180.8)">26</text>
<text x="132.3" y="180.8" transform="rotate(-90 132.3 180.8)">27</text>
<text x="133.6" y="180.8" transform="rotate(-90 133.6 180.8)">28</text>
<text x="135" y="180.8" transform="rotate(-90 135 180.8)">29</text>
<text x="136.4" y="180.8" transform="rotate(-90 136.4 180.8)">30</text>
<text x="137.8" y="180.8" transform="rotate(-90 137.8 180.8)">31</text>
<text x="139.1" y="180.8" transform="rotate(-90 139.1 180.8)">32</text>
<text x="140.5" y="180.8" transform="rotate(-90 140.5 180.8)">35</text>
<text x="141.9" y="180.8" transform="rotate(-90 141.9 180.8)">36</text>
<text x="143.3" y="180.8" transform="rotate(-90 143.3 180.8)">37</text>
<text x="144.6" y="180.8" transform="rotate(-90 144.6 180.8)">38</text>
<text x="146" y="180.8" transform="rotate(-90 146 180.8)">39</text>
<text x="147.4" y="180.8" transform="rotate(-90 147.4 180.8)">40</text>
<text x="148.7" y="180.8" transform="rotate(-90 148.7 180.8)">41</text>
<text x="150.1" y="180.8" transform="rotate(-90 150.1 180.8)">42</text>
<text x="123.3" y="189.9" transform="rotate(-90 123.3 189.9)">VDD</text>
<text x="128.2" y="187.2" transform="rotate(-90 128.2 187.2)">A2</text>
<text x="129.6" y="187.2" transform="rotate(-90 129.6 187.2)">A3</text>
<text x="130.9" y="187.2" transform="rotate(-90 130.9 187.2)">A4</text>
<text x="132.3" y="187.2" transform="rotate(-90 132.3 187.2)">A5</text>
<text x="133.7" y="187.2" transform="rotate(-90 133.7 187.2)">A6</text>
<text x="135" y="187.2" transform="rotate(-90 135 187.2)">A7</text>
<text x="136.4" y="187.2" transform="rotate(-90 136.4 187.2)">A8</text>
<text x="137.8" y="187.2" transform="rotate(-90 137.8 187.2)">A9</text>
<text x="139.2" y="187.2" transform="rotate(-90 139.2 187.2)">A10</text>
<text x="140.5" y="187.2" transform="rotate(-90 140.5 187.2)">A11</text>
<text x="141.9" y="187.2" transform="rotate(-90 141.9 187.2)">A12</text>
<text x="143.3" y="187.2" transform="rotate(-90 143.3 187.2)">A13</text>
<text x="144.7" y="187.2" transform="rotate(-90 144.7 187.2)">A14</text>
<text x="146.1" y="187.2" transform="rotate(-90 146.1 187.2)">A15</text>
<text x="147.4" y="187.2" transform="rotate(-90 147.4 187.2)">A16</text>
<text x="148.8" y="187.2" transform="rotate(-90 148.8 187.2)">A17</text>
<text x="150.2" y="187.2" transform="rotate(-90 150.2 187.2)">A18</text>
<text x="78.8" y="201.5" transform="rotate(-90 78.8 201.5)">DATA0</text>
<text x="80.1" y="201.5" transform="rotate(-90 80.1 201.5)">DATA1</text>
<text x="81.5" y="201.5" transform="rotate(-90 81.5 201.5)">DATA2</text>
<text x="82.9" y="201.5" transform="rotate(-90 82.9 201.5)">DATA3</text>
<text x="84.2" y="201.5" transform="rotate(-90 84.2 201.5)">DATA4</text>
<text x="85.6" y="201.5" transform="rotate(-90 85.6 201.5)">DATA5</text>
<text x="87" y="201.5" transform="rotate(-90 87 201.5)">DATA6</text>
<text x="88.4" y="201.5" transform="rotate(-90 88.4 201.5)">DATA7</text>
<text x="157" y="201" transform="rotate(-90 157 201)">VDD</text>
<text x="162.3" y="203.9" transform="rotate(-90 162.3 203.9)">C40</text>
<text x="52.6" y="205.3" transform="rotate(-90 52.6 205.3)">VDR</text>
<text x="55.4" y="207.8" transform="rotate(-90 55.4 207.8)">24</text>
<text x="56.7" y="207.8" transform="rotate(-90 56.7 207.8)">8</text>
<text x="60.9" y="207.8" transform="rotate(-90 60.9 207.8)">9</text>
<text x="62.2" y="207.8" transform="rotate(-90 62.2 207.8)">25</text>
<text x="66.4" y="205.9" transform="rotate(-90 66.4 205.9)">DGND</text>
<text x="78.7" y="207.8" transform="rotate(-90 78.7 207.8)">6</text>
<text x="80.1" y="207.8" transform="rotate(-90 80.1 207.8)">7</text>
<text x="81.5" y="207.8" transform="rotate(-90 81.5 207.8)">10</text>
<text x="82.8" y="207.8" transform="rotate(-90 82.8 207.8)">11</text>
<text x="84.2" y="207.8" transform="rotate(-90 84.2 207.8)">22</text>
<text x="85.6" y="207.8" transform="rotate(-90 85.6 207.8)">23</text>
<text x="87" y="207.8" transform="rotate(-90 87 207.8)">26</text>
<text x="88.3" y="207.8" transform="rotate(-90 88.3 207.8)">27</text>
<text x="119.9" y="207.8" transform="rotate(-90 119.9 207.8)">1</text>
<text x="121.3" y="207.8" transform="rotate(-90 121.3 207.8)">13</text>
<text x="122.6" y="207.8" transform="rotate(-90 122.6 207.8)">23</text>
<text x="124" y="207.8" transform="rotate(-90 124 207.8)">33</text>
<text x="128.1" y="207.8" transform="rotate(-90 128.1 207.8)">21</text>
<text x="128.2" y="204.1" transform="rotate(-90 128.2 204.1)">DATA0</text>
<text x="129.5" y="207.8" transform="rotate(-90 129.5 207.8)">20</text>
<text x="129.6" y="204.1" transform="rotate(-90 129.6 204.1)">DATA1</text>
<text x="130.9" y="207.8" transform="rotate(-90 130.9 207.8)">19</text>
<text x="130.9" y="204.1" transform="rotate(-90 130.9 204.1)">DATA2</text>
<text x="132.3" y="207.8" transform="rotate(-90 132.3 207.8)">18</text>
<text x="132.3" y="204.1" transform="rotate(-90 132.3 204.1)">DATA3</text>
<text x="133.6" y="207.8" transform="rotate(-90 133.6 207.8)">17</text>
<text x="133.7" y="204.1" transform="rotate(-90 133.7 204.1)">DATA4</text>
<text x="135" y="207.8" transform="rotate(-90 135 207.8)">16</text>
<text x="135" y="204.1" transform="rotate(-90 135 204.1)">DATA5</text>
<text x="136.4" y="207.8" transform="rotate(-90 136.4 207.8)">15</text>
<text x="136.4" y="204.1" transform="rotate(-90 136.4 204.1)">DATA6</text>
<text x="137.8" y="207.8" transform="rotate(-90 137.8 207.8)">14</text>
<text x="137.8" y="204.1" transform="rotate(-90 137.8 204.1)">DATA7</text>
<text x="139.1" y="207.8" transform="rotate(-90 139.1 207.8)">11</text>
<text x="139.2" y="204.1" transform="rotate(-90 139.2 204.1)">DATA8</text>
<text x="140.5" y="207.8" transform="rotate(-90 140.5 207.8)">10</text>
<text x="140.5" y="204.1" transform="rotate(-90 140.5 204.1)">DATA9</text>
<text x="141.9" y="207.8" transform="rotate(-90 141.9 207.8)">9</text>
<text x="141.9" y="204.1" transform="rotate(-90 141.9 204.1)">DATA10</text>
<text x="143.3" y="207.8" transform="rotate(-90 143.3 207.8)">8</text>
<text x="143.3" y="204.1" transform="rotate(-90 143.3 204.1)">DATA11</text>
<text x="144.6" y="207.8" transform="rotate(-90 144.6 207.8)">7</text>
<text x="144.7" y="204.1" transform="rotate(-90 144.7 204.1)">DATA12</text>
<text x="146" y="207.8" transform="rotate(-90 146 207.8)">6</text>
<text x="146.1" y="204.1" transform="rotate(-90 146.1 204.1)">DATA13</text>
<text x="147.4" y="207.8" transform="rotate(-90 147.4 207.8)">5</text>
<text x="147.4" y="204.1" transform="rotate(-90 147.4 204.1)">DATA14</text>
<text x="148.7" y="207.8" transform="rotate(-90 148.7 207.8)">4</text>
<text x="148.8" y="204.1" transform="rotate(-90 148.8 204.1)">DATA15</text>
<text x="151.5" y="207.8" transform="rotate(-90 151.5 207.8)">12</text>
<text x="152.9" y="207.8" transform="rotate(-90 152.9 207.8)">34</text>
<text x="157" y="206" transform="rotate(-90 157 206)">DGND</text>
<text x="158.8" y="207.6" transform="rotate(-90 158.8 207.6)">100n</text>
<text x="162.3" y="209.7" transform="rotate(-90 162.3 209.7)">C39</text>
<text x="56.1" y="213.2" transform="rotate(-90 56.1 213.2)">VCC</text>
<text x="57.4" y="213.2" transform="rotate(-90 57.4 213.2)">VCC</text>
<text x="61.6" y="213.1" transform="rotate(-90 61.6 213.1)">VSS</text>
<text x="62.9" y="213.1" transform="rotate(-90 62.9 213.1)">VSS</text>
<text x="79.4" y="212.9" transform="rotate(-90 79.4 212.9)">I/O1</text>
<text x="80.8" y="212.9" transform="rotate(-90 80.8 212.9)">I/O2</text>
<text x="82.1" y="212.9" transform="rotate(-90 82.1 212.9)">I/O3</text>
<text x="83.5" y="212.9" transform="rotate(-90 83.5 212.9)">I/O4</text>
<text x="84.9" y="212.9" transform="rotate(-90 84.9 212.9)">I/O5</text>
<text x="86.3" y="212.9" transform="rotate(-90 86.3 212.9)">I/O6</text>
<text x="87.6" y="212.9" transform="rotate(-90 87.6 212.9)">I/O7</text>
<text x="89" y="212.9" transform="rotate(-90 89 212.9)">I/O8</text>
<text x="100.8" y="215.5" transform="rotate(-90 100.8 215.5)">DATA[0..31]</text>
<text x="120.6" y="212.5" transform="rotate(-90 120.6 212.5)">NC</text>
<text x="122" y="212.5" transform="rotate(-90 122 212.5)">NC</text>
<text x="123.3" y="212.5" transform="rotate(-90 123.3 212.5)">NC</text>
<text x="124.7" y="212.5" transform="rotate(-90 124.7 212.5)">NC</text>
<text x="128.8" y="212.9" transform="rotate(-90 128.8 212.9)">I/O0</text>
<text x="130.2" y="212.9" transform="rotate(-90 130.2 212.9)">I/O1</text>
<text x="131.6" y="212.9" transform="rotate(-90 131.6 212.9)">I/O2</text>
<text x="132.9" y="212.9" transform="rotate(-90 132.9 212.9)">I/O3</text>
<text x="134.3" y="212.9" transform="rotate(-90 134.3 212.9)">I/O4</text>
<text x="135.7" y="212.9" transform="rotate(-90 135.7 212.9)">I/O5</text>
<text x="137.1" y="212.9" transform="rotate(-90 137.1 212.9)">I/O6</text>
<text x="138.4" y="212.9" transform="rotate(-90 138.4 212.9)">I/O7</text>
<text x="139.8" y="212.9" transform="rotate(-90 139.8 212.9)">I/O8</text>
<text x="141.2" y="212.9" transform="rotate(-90 141.2 212.9)">I/O9</text>
<text x="142.6" y="213.7" transform="rotate(-90 142.6 213.7)">I/O10</text>
<text x="143.9" y="213.7" transform="rotate(-90 143.9 213.7)">I/O11</text>
<text x="145.3" y="213.7" transform="rotate(-90 145.3 213.7)">I/O12</text>
<text x="146.7" y="213.7" transform="rotate(-90 146.7 213.7)">I/O13</text>
<text x="148" y="213.7" transform="rotate(-90 148 213.7)">I/O14</text>
<text x="149.4" y="213.7" transform="rotate(-90 149.4 213.7)">I/O15</text>
<text x="152.2" y="213.1" transform="rotate(-90 152.2 213.1)">VSS</text>
<text x="153.5" y="213.1" transform="rotate(-90 153.5 213.1)">VSS</text>
<text x="158.7" y="213.2" transform="rotate(-90 158.7 213.2)">100n</text>
<text x="162.3" y="214.9" transform="rotate(-90 162.3 214.9)">C38</text>
<text x="41.7" y="218.3" transform="rotate(-90 41.7 218.3)">A[0..22]</text>
<text x="158.7" y="219.2" transform="rotate(-90 158.7 219.2)">100n</text>
<text x="162" y="221.2" transform="rotate(-90 162 221.2)">C37</text>
<text x="54.1" y="224.1" transform="rotate(-90 54.1 224.1)">IC6</text>
<text x="55.4" y="226.8" transform="rotate(-90 55.4 226.8)">5</text>
<text x="56.1" y="223.3" transform="rotate(-90 56.1 223.3)">CS</text>
<text x="58.1" y="227.5" transform="rotate(-90 58.1 227.5)">12</text>
<text x="58.8" y="223.3" transform="rotate(-90 58.8 223.3)">WE</text>
<text x="60.9" y="227.5" transform="rotate(-90 60.9 227.5)">28</text>
<text x="61.6" y="223.3" transform="rotate(-90 61.6 223.3)">OE</text>
<text x="66.4" y="226.8" transform="rotate(-90 66.4 226.8)">4</text>
<text x="67.1" y="223.3" transform="rotate(-90 67.1 223.3)">A0</text>
<text x="67.7" y="226.8" transform="rotate(-90 67.7 226.8)">3</text>
<text x="68.4" y="223.3" transform="rotate(-90 68.4 223.3)">A1</text>
<text x="69.1" y="226.8" transform="rotate(-90 69.1 226.8)">2</text>
<text x="69.8" y="223.3" transform="rotate(-90 69.8 223.3)">A2</text>
<text x="70.5" y="226.8" transform="rotate(-90 70.5 226.8)">1</text>
<text x="71.2" y="223.3" transform="rotate(-90 71.2 223.3)">A3</text>
<text x="71.8" y="227.5" transform="rotate(-90 71.8 227.5)">32</text>
<text x="72.5" y="223.3" transform="rotate(-90 72.5 223.3)">A4</text>
<text x="73.2" y="227.5" transform="rotate(-90 73.2 227.5)">31</text>
<text x="73.9" y="223.3" transform="rotate(-90 73.9 223.3)">A5</text>
<text x="74.6" y="227.5" transform="rotate(-90 74.6 227.5)">30</text>
<text x="75.3" y="223.3" transform="rotate(-90 75.3 223.3)">A6</text>
<text x="76" y="227.5" transform="rotate(-90 76 227.5)">29</text>
<text x="76.7" y="223.3" transform="rotate(-90 76.7 223.3)">A7</text>
<text x="77.3" y="227.5" transform="rotate(-90 77.3 227.5)">21</text>
<text x="78" y="223.3" transform="rotate(-90 78 223.3)">A8</text>
<text x="78.7" y="227.5" transform="rotate(-90 78.7 227.5)">20</text>
<text x="79.4" y="223.3" transform="rotate(-90 79.4 223.3)">A9</text>
<text x="80.1" y="227.5" transform="rotate(-90 80.1 227.5)">19</text>
<text x="80.8" y="223.3" transform="rotate(-90 80.8 223.3)">A10</text>
<text x="81.5" y="227.5" transform="rotate(-90 81.5 227.5)">18</text>
<text x="82.1" y="223.3" transform="rotate(-90 82.1 223.3)">A11</text>
<text x="82.8" y="227.5" transform="rotate(-90 82.8 227.5)">17</text>
<text x="83.5" y="223.3" transform="rotate(-90 83.5 223.3)">A12</text>
<text x="84.2" y="227.5" transform="rotate(-90 84.2 227.5)">16</text>
<text x="84.9" y="223.3" transform="rotate(-90 84.9 223.3)">A13</text>
<text x="85.6" y="227.5" transform="rotate(-90 85.6 227.5)">15</text>
<text x="86.3" y="223.3" transform="rotate(-90 86.3 223.3)">A14</text>
<text x="87" y="227.5" transform="rotate(-90 87 227.5)">14</text>
<text x="87.6" y="223.3" transform="rotate(-90 87.6 223.3)">A15</text>
<text x="88.3" y="227.5" transform="rotate(-90 88.3 227.5)">13</text>
<text x="89" y="223.3" transform="rotate(-90 89 223.3)">A16</text>
<text x="117.2" y="224.1" transform="rotate(-90 117.2 224.1)">IC10</text>
<text x="119.9" y="226.8" transform="rotate(-90 119.9 226.8)">3</text>
<text x="120.6" y="223.3" transform="rotate(-90 120.6 223.3)">CE</text>
<text x="121.3" y="226.8" transform="rotate(-90 121.3 226.8)">2</text>
<text x="122" y="223.3" transform="rotate(-90 122 223.3)">VPP</text>
<text x="122.6" y="227.5" transform="rotate(-90 122.6 227.5)">44</text>
<text x="123.3" y="223.3" transform="rotate(-90 123.3 223.3)">VCC</text>
<text x="124" y="227.5" transform="rotate(-90 124 227.5)">43</text>
<text x="124.7" y="223.3" transform="rotate(-90 124.7 223.3)">PGM</text>
<text x="125.4" y="227.5" transform="rotate(-90 125.4 227.5)">22</text>
<text x="126.1" y="223.3" transform="rotate(-90 126.1 223.3)">OE</text>
<text x="128.1" y="227.5" transform="rotate(-90 128.1 227.5)">24</text>
<text x="128.8" y="223.3" transform="rotate(-90 128.8 223.3)">A0</text>
<text x="129.5" y="227.5" transform="rotate(-90 129.5 227.5)">25</text>
<text x="130.2" y="223.3" transform="rotate(-90 130.2 223.3)">A1</text>
<text x="130.9" y="227.5" transform="rotate(-90 130.9 227.5)">26</text>
<text x="131.6" y="223.3" transform="rotate(-90 131.6 223.3)">A2</text>
<text x="132.3" y="227.5" transform="rotate(-90 132.3 227.5)">27</text>
<text x="132.9" y="223.3" transform="rotate(-90 132.9 223.3)">A3</text>
<text x="133.6" y="227.5" transform="rotate(-90 133.6 227.5)">28</text>
<text x="134.3" y="223.3" transform="rotate(-90 134.3 223.3)">A4</text>
<text x="135" y="227.5" transform="rotate(-90 135 227.5)">29</text>
<text x="135.7" y="223.3" transform="rotate(-90 135.7 223.3)">A5</text>
<text x="136.4" y="227.5" transform="rotate(-90 136.4 227.5)">30</text>
<text x="137.1" y="223.3" transform="rotate(-90 137.1 223.3)">A6</text>
<text x="137.8" y="227.5" transform="rotate(-90 137.8 227.5)">31</text>
<text x="138.4" y="223.3" transform="rotate(-90 138.4 223.3)">A7</text>
<text x="139.1" y="227.5" transform="rotate(-90 139.1 227.5)">32</text>
<text x="139.8" y="223.3" transform="rotate(-90 139.8 223.3)">A8</text>
<text x="140.5" y="227.5" transform="rotate(-90 140.5 227.5)">35</text>
<text x="141.2" y="223.3" transform="rotate(-90 141.2 223.3)">A9</text>
<text x="141.9" y="227.5" transform="rotate(-90 141.9 227.5)">36</text>
<text x="142.6" y="223.3" transform="rotate(-90 142.6 223.3)">A10</text>
<text x="143.3" y="227.5" transform="rotate(-90 143.3 227.5)">37</text>
<text x="143.9" y="223.3" transform="rotate(-90 143.9 223.3)">A11</text>
<text x="144.6" y="227.5" transform="rotate(-90 144.6 227.5)">38</text>
<text x="145.3" y="223.3" transform="rotate(-90 145.3 223.3)">A12</text>
<text x="146" y="227.5" transform="rotate(-90 146 227.5)">39</text>
<text x="146.7" y="223.3" transform="rotate(-90 146.7 223.3)">A13</text>
<text x="147.4" y="227.5" transform="rotate(-90 147.4 227.5)">40</text>
<text x="148" y="223.3" transform="rotate(-90 148 223.3)">A14</text>
<text x="148.7" y="227.5" transform="rotate(-90 148.7 227.5)">41</text>
<text x="149.4" y="223.3" transform="rotate(-90 149.4 223.3)">A15</text>
<text x="150.1" y="227.5" transform="rotate(-90 150.1 227.5)">42</text>
<text x="150.8" y="223.3" transform="rotate(-90 150.8 223.3)">A16</text>
<text x="158.7" y="224.5" transform="rotate(-90 158.7 224.5)">100n</text>
<text x="161.8" y="226.5" transform="rotate(-90 161.8 226.5)">C36</text>
<text x="55.4" y="231.2" transform="rotate(-90 55.4 231.2)">NRAM</text>
<text x="58.2" y="231.2" transform="rotate(-90 58.2 231.2)">NW0</text>
<text x="60.9" y="231.2" transform="rotate(-90 60.9 231.2)">NRD</text>
<text x="66.4" y="232.6" transform="rotate(-90 66.4 232.6)">A2</text>
<text x="67.8" y="232.6" transform="rotate(-90 67.8 232.6)">A3</text>
<text x="69.2" y="232.6" transform="rotate(-90 69.2 232.6)">A4</text>
<text x="70.5" y="232.6" transform="rotate(-90 70.5 232.6)">A5</text>
<text x="71.9" y="232.6" transform="rotate(-90 71.9 232.6)">A6</text>
<text x="73.3" y="232.6" transform="rotate(-90 73.3 232.6)">A7</text>
<text x="74.6" y="232.6" transform="rotate(-90 74.6 232.6)">A8</text>
<text x="76" y="232.6" transform="rotate(-90 76 232.6)">A9</text>
<text x="77.4" y="232.6" transform="rotate(-90 77.4 232.6)">A10</text>
<text x="78.8" y="232.6" transform="rotate(-90 78.8 232.6)">A11</text>
<text x="80.1" y="232.6" transform="rotate(-90 80.1 232.6)">A12</text>
<text x="81.5" y="232.6" transform="rotate(-90 81.5 232.6)">A13</text>
<text x="82.9" y="232.6" transform="rotate(-90 82.9 232.6)">A14</text>
<text x="84.2" y="232.6" transform="rotate(-90 84.2 232.6)">A15</text>
<text x="85.6" y="232.6" transform="rotate(-90 85.6 232.6)">A16</text>
<text x="87" y="232.6" transform="rotate(-90 87 232.6)">A17</text>
<text x="88.4" y="232.6" transform="rotate(-90 88.4 232.6)">A18</text>
<text x="101.4" y="233.9" transform="rotate(-90 101.4 233.9)">DATA[0..31]</text>
<text x="120" y="232.6" transform="rotate(-90 120 232.6)">NROM</text>
<text x="125.4" y="232.5" transform="rotate(-90 125.4 232.5)">NRD</text>
<text x="129.6" y="233.9" transform="rotate(-90 129.6 233.9)">A3</text>
<text x="130.9" y="233.9" transform="rotate(-90 130.9 233.9)">A4</text>
<text x="132.3" y="233.9" transform="rotate(-90 132.3 233.9)">A5</text>
<text x="133.7" y="233.9" transform="rotate(-90 133.7 233.9)">A6</text>
<text x="135" y="233.9" transform="rotate(-90 135 233.9)">A7</text>
<text x="136.4" y="233.9" transform="rotate(-90 136.4 233.9)">A8</text>
<text x="137.8" y="233.9" transform="rotate(-90 137.8 233.9)">A9</text>
<text x="139.2" y="233.9" transform="rotate(-90 139.2 233.9)">A10</text>
<text x="140.5" y="233.9" transform="rotate(-90 140.5 233.9)">A11</text>
<text x="141.9" y="233.9" transform="rotate(-90 141.9 233.9)">A12</text>
<text x="143.3" y="233.9" transform="rotate(-90 143.3 233.9)">A13</text>
<text x="144.7" y="233.9" transform="rotate(-90 144.7 233.9)">A14</text>
<text x="146.1" y="233.9" transform="rotate(-90 146.1 233.9)">A15</text>
<text x="147.4" y="233.9" transform="rotate(-90 147.4 233.9)">A16</text>
<text x="148.8" y="233.9" transform="rotate(-90 148.8 233.9)">A17</text>
<text x="150.2" y="233.9" transform="rotate(-90 150.2 233.9)">A18</text>
<text x="158.7" y="230.1" transform="rotate(-90 158.7 230.1)">100n</text>
<text x="162" y="232.3" transform="rotate(-90 162 232.3)">C35</text>
<text x="123.3" y="236.6" transform="rotate(-90 123.3 236.6)">VDD</text>
<text x="128.2" y="234" transform="rotate(-90 128.2 234)">A2</text>
<text x="155.6" y="237.9" transform="rotate(-90 155.6 237.9)">VDR</text>
<text x="158.5" y="235.3" transform="rotate(-90 158.5 235.3)">100n</text>
<text x="42.3" y="241" transform="rotate(-90 42.3 241)">A[0..22]</text>
<text x="169.3" y="241.3" transform="rotate(-90 169.3 241.3)">DGND</text>
</g>
</g></defs>
<path d="M16.8 19.4h178.2" fill="none" stroke="#000" stroke-width=".35"/>
<path d="M32.5 66.2h145.1v209.6h-145.1z" fill="#fff"/>
<path d="M35.1 38.1h142.5v217.2h-142.5z" fill-rule="evenodd" fill="#fff"/>
<path d="M155.7 80.8h5.8v5.9h-5.8z" fill-rule="evenodd" fill="#fff" stroke="#fff" stroke-width=".13"/>
<g fill="#fff" stroke="#000" stroke-width=".13">
<path d="M41.9 231.1l.7 .7v10.6h-1.4v-10.6z" fill-rule="evenodd"/>
<path d="M58.4 42h1.4v4.9l-.7 .8-.7-.8z" fill-rule="evenodd"/>
<path d="M41.9 42h1.4v4.9l-.7 .8-.7-.8z" fill-rule="evenodd"/>
<path d="M44.7 42h1.3v4.9l-.7 .8-.6-.8z" fill-rule="evenodd"/>
<path d="M47.4 42h1.4v4.9l-.7 .8-.7-.8z" fill-rule="evenodd"/>
<path d="M50.2 42h1.3v6.4l-.7 .7-.6-.7z" fill-rule="evenodd"/>
<path d="M52.9 42h1.4v6.4l-.7 .7-.7-.7z" fill-rule="evenodd"/>
<path d="M55.6 42h1.4v4.9l-.7 .8-.7-.8z" fill-rule="evenodd"/>
<path d="M101 218.3l.6 .7v15.6l-.6 .7-.7-.7v-15.6z" fill-rule="evenodd"/>
</g>
<g fill="none" stroke="#000" stroke-width=".13">
<path d="M42.6 47.7v8.5M45.3 47.7v8.5M48.1 47.7v8.5M50.8 49.1v7.1M52.9 59.7h2.7v1.6M52.9 59v1.4M53.6 49.1v7.1M56.3 47.7v8.5M59.1 47.7v8.5M63.9 59.7h1.4M65.3 59v1.4M80.4 51.2l-1.4 1.4v8.7"/>
<path d="M81.7 51.2l-1.3 1.4v8.7M83.1 51.2l-1.4 1.4v8.7M84.5 51.2l-1.4 1.4v8.7M85.9 51.2l-1.4 1.4v8.7M87.2 51.2l-1.3 1.4v8.7M88.6 51.2l-1.4 1.4v8.7M90 51.2l-1.4 1.4v8.7M55.6 83.9v5.6M58.4 83.9v5.6M61.1 83.9v5.6M66.6 83.9v8.4l-1.3 1.4M68 83.9v8.4l-1.4 1.4"/>
<path d="M69.4 83.9v8.4l-1.4 1.4M70.7 83.9v8.4l-1.3 1.4M72.1 83.9v8.4l-1.4 1.4M73.5 83.9v8.4l-1.4 1.4M74.9 83.9v8.4l-1.4 1.4M76.2 83.9v8.4l-1.3 1.4M77.6 83.9v8.4l-1.4 1.4M79 83.9v8.4l-1.4 1.4M80.4 83.9v8.4l-1.4 1.4M81.7 83.9v8.4l-1.3 1.4M83.1 83.9v8.4l-1.4 1.4M84.5 83.9v8.4l-1.4 1.4"/>
<path d="M85.9 83.9v8.4l-1.4 1.4M87.2 83.9v8.4l-1.3 1.4M88.6 83.9v8.4l-1.4 1.4M52.9 107.9h2.7v2.9M52.9 107.1v1.4M63.9 107.9h1.4M65.3 107.1v1.4M80.4 100.8l-1.4 1.4v8.6M81.7 100.8l-1.3 1.4v8.6M83.1 100.8l-1.4 1.4v8.6M84.5 100.8l-1.4 1.4v8.6M85.9 100.8l-1.4 1.4v8.6"/>
<path d="M87.2 100.8l-1.3 1.4v8.6M88.6 100.8l-1.4 1.4v8.6M90 100.8l-1.4 1.4v8.6M55.6 133.5v5.5M58.4 133.5v5.5M61.1 133.5v5.5M66.6 133.5v8.4l-1.3 1.4M68 133.5v8.4l-1.4 1.4M69.4 133.5v8.4l-1.4 1.4M70.7 133.5v8.4l-1.3 1.4M72.1 133.5v8.4l-1.4 1.4M73.5 133.5v8.4l-1.4 1.4"/>
<path d="M74.9 133.5v8.4l-1.4 1.4M76.2 133.5v8.4l-1.3 1.4M77.6 133.5v8.4l-1.4 1.4M79 133.5v8.4l-1.4 1.4M80.4 133.5v8.4l-1.4 1.4M81.7 133.5v8.4l-1.3 1.4M83.1 133.5v8.4l-1.4 1.4M84.5 133.5v8.4l-1.4 1.4M85.9 133.5v8.4l-1.4 1.4M87.2 133.5v8.4l-1.3 1.4M88.6 133.5v8.4l-1.4 1.4M52.9 157.4h2.7v1.6"/>
<path d="M52.9 156.7v1.4M63.9 157.4h1.4M65.3 156.7v1.4M80.4 148.9l-1.4 1.4v8.7M81.7 148.9l-1.3 1.4v8.7M83.1 148.9l-1.4 1.4v8.7M84.5 148.9l-1.4 1.4v8.7M85.9 148.9l-1.4 1.4v8.7M87.2 148.9l-1.3 1.4v8.7M88.6 148.9l-1.4 1.4v8.7M90 148.9l-1.4 1.4v8.7M128.4 150.3v8.7"/>
<path d="M129.8 150.3v8.7M131.2 150.3v8.7M132.5 150.3v8.7M133.9 150.3v8.7M135.3 150.3v8.7M136.7 150.3v8.7M138 150.3v8.7M139.4 150.3v8.7M140.8 150.3v8.7M142.2 150.3v8.7M143.5 150.3v8.7M144.9 150.3v8.7"/>
<path d="M146.3 150.3v8.7M147.6 150.3v8.7M149 150.3v8.7M154.5 157.6h1.4M155.9 156.8v1.5M160.5 171.7h.6M160.5 160.4h3.3v4.2M162.5 164.6h2.7l-1.4 1.5zM163.8 166.1v2.8M164.9 165.4h.3v.7h-2.7v.7h.2M55.6 181.7v5.5M58.4 181.7v5.5"/>
<path d="M61.1 181.7v5.5M66.6 181.7v8.3l-1.3 1.4M68 181.7v8.3l-1.4 1.4M69.4 181.7v8.3l-1.4 1.4M70.7 181.7v8.3l-1.3 1.4M72.1 181.7v8.3l-1.4 1.4M73.5 181.7v8.3l-1.4 1.4M74.9 181.7v8.3l-1.4 1.4M76.2 181.7v8.3l-1.3 1.4M77.6 181.7v8.3l-1.4 1.4M79 181.7v8.3l-1.4 1.4M80.4 195.7l-1.4 1.4v8.6"/>
<path d="M80.4 181.7v8.3l-1.4 1.4M81.7 181.7v8.3l-1.3 1.4M81.7 195.7l-1.3 1.4-.1 8.6M83.1 181.7v8.3l-1.4 1.4M83.1 195.7l-1.4 1.4v8.6M84.5 181.7v8.3l-1.4 1.4M84.5 195.7l-1.4 1.4v8.6M85.9 181.7v8.3l-1.4 1.4M85.9 195.7l-1.4 1.4v8.6M87.2 195.7l-1.3 1.4v8.6M87.2 181.7v8.3l-1.3 1.4M88.6 195.7l-1.4 1.4v8.6"/>
<path d="M88.6 181.7v8.3l-1.4 1.4M90 195.7l-1.4 1.4v8.6M120.2 181.7v5.6M122.9 185.8v.5M125.7 181.7v5.6M128.4 197.2v8.5M128.4 181.7v8.3l-1.4 1.4M129.8 197.2v8.5M129.8 181.7v8.3l-1.4 1.4M131.1 197.2v8.5M131.2 181.7v8.3l-1.4 1.4M132.5 181.7v8.3l-1.3 1.4"/>
<path d="M132.5 197.2v8.5M133.9 181.7v8.3l-1.4 1.4M133.9 197.2v8.5M135.3 197.2v8.5M135.3 181.7v8.3l-1.4 1.4M136.7 197.2v8.5M136.7 181.7v8.3l-1.4 1.4M138 197.2v8.5M138 181.7v8.3l-1.3 1.4M139.4 197.2v8.5M139.4 181.7v8.3l-1.4 1.4M140.8 181.7v8.3l-1.4 1.4"/>
<path d="M140.8 197.2v8.5M142.2 197.2v8.5M142.2 181.7v8.3l-1.4 1.4M143.5 197.2v8.5M143.5 181.7v8.3l-1.3 1.4M144.9 197.2v8.5M144.9 181.7v8.3l-1.4 1.4M146.3 197.2v8.5M146.3 181.7v8.3l-1.4 1.4M147.6 181.7v8.3l-1.3 1.4M147.6 197.2v8.5M149 197.1v8.6"/>
<path d="M149 181.7v8.3l-1.4 1.4M150.4 181.7v8.3l-1.4 1.4M52.9 204.1h2.7v1.6M52.9 203.5v1.4M63.9 204.1h1.4M65.3 203.5v1.4M154.5 204.3h1.4M155.9 203.6v1.4M160 216.9h3M160 211.2h3M160 205.6h3M163 204.3v2.5"/>
<path d="M163 210v2.5M163 215.6v2.6M163.7 216.9h3.2M163.7 211.2h3.2M163.7 205.6h3.2M163.7 204.3v2.5M163.7 210v2.5M163.7 215.6v2.6M55.6 228.3v5.6M58.4 228.3v5.6M61.1 228.3v5.6M66.6 228.3v8.4l-1.3 1.4"/>
<path d="M68 228.3v8.4l-1.4 1.4M69.4 228.3v8.4l-1.4 1.4M70.7 228.3v8.4l-1.3 1.4M72.1 228.3v8.4l-1.4 1.4M73.5 228.3v8.4l-1.4 1.4M74.9 228.3v8.4l-1.4 1.4M76.2 228.3v8.4l-1.3 1.4M77.6 228.3v8.4l-1.4 1.4M79 228.3v8.4l-1.4 1.4M80.3 228.3v8.4l-1.3 1.4M81.7 228.3v8.4l-1.4 1.4M83.1 228.3v8.4l-1.4 1.4"/>
<path d="M84.5 228.3v8.4l-1.4 1.4M85.9 228.3v8.4l-1.4 1.4M87.2 228.3v8.4l-1.3 1.4M88.6 228.3v8.4l-1.4 1.4M120.2 228.3v5.7M122.9 232.5v.5M125.7 228.3v5.6M128.4 228.3v8.4l-1.4 1.4M129.8 228.3v8.4l-1.4 1.4M131.1 228.3v8.4l-1.3 1.4M132.5 228.3v8.4l-1.4 1.4M133.9 228.3v8.4l-1.4 1.4"/>
<path d="M135.3 228.3v8.4l-1.4 1.4M136.7 228.3v8.4l-1.4 1.4M138 228.3v8.4l-1.3 1.4M139.4 228.3v8.4l-1.4 1.4M140.8 228.3v8.4l-1.4 1.4M142.2 228.3v8.4l-1.4 1.4M143.5 228.3v8.4l-1.3 1.4M144.9 228.3v8.4l-1.4 1.4M146.3 228.3v8.4l-1.4 1.4M147.6 228.3v8.4l-1.3 1.4M149 228.3v8.4l-1.4 1.4M150.4 228.3v8.4l-1.4 1.4"/>
<path d="M155.9 236v1.5M155.9 236.7h1.3M160 233.9h3M160 228.2h3M160 222.5h3M163 221.3v2.5M163 227v2.5M163 232.6v2.6M163.7 233.9h3.2M163.7 228.2h3.2M163.7 222.5h3.2M163.7 221.3v2.5"/>
<path d="M163.7 227v2.5M163.7 232.6v2.6M166.9 239.6h1.3M168.2 238.8v1.4"/>
<circle cx="160.1" cy="171.7" r=".39"/>
<circle cx="160.1" cy="160.4" r=".39"/>
<circle cx="122.9" cy="186.8" r=".39"/>
<circle cx="122.9" cy="233.5" r=".39"/>
</g>
<g fill="#000" stroke="#000" stroke-width=".13">
<circle cx="160" cy="216.9" r=".39"/>
<circle cx="160" cy="205.6" r=".39"/>
<circle cx="160" cy="211.3" r=".39"/>
<circle cx="166.8" cy="216.9" r=".39"/>
<circle cx="166.8" cy="211.3" r=".39"/>
<circle cx="166.8" cy="205.6" r=".39"/>
<circle cx="160" cy="233.9" r=".39"/>
<circle cx="160" cy="228.3" r=".39"/>
<circle cx="160" cy="222.6" r=".39"/>
<circle cx="166.8" cy="228.3" r=".39"/>
<circle cx="166.8" cy="233.9" r=".39"/>
<circle cx="166.8" cy="222.6" r=".39"/>
</g>
<path d="M80.4 51.2h20.6v49.6M87.2 93.7h-45.3v137.4M80.4 100.8h20.6v48.1M41.9 143.3h45.3M80.4 148.9h20.6v42.5M41.9 191.4h45.3M80.4 195.7h20.6v-4.3v26.9M149 191.4h-37.1v46.7M41.9 226.8h9.6v11.3h97.5" fill="none" stroke="#000" stroke-width=".42"/>
<path d="M54.3 210h38.4v14.1h-38.4z" fill-rule="evenodd" fill="#fff" stroke="#000" stroke-width=".13"/>
<g fill="none" stroke="#000" stroke-width=".13">
<path d="M55.6 205.7v4.3M57 205.7v4.3M61.1 205.7v4.3M62.5 205.7v4.3M79 205.7v4.3M80.3 205.7v4.3M81.7 205.7v4.3M83.1 205.7v4.3M84.5 205.7v4.3M85.9 205.7v4.3M87.2 205.7v4.3M88.6 205.7v4.3"/>
<path d="M54.9 221.6v1.7M55.6 225v3.3M57.7 221.3v2M58.4 225v3.3M60.5 221.6v1.7M61.1 225v3.3M66.6 224.1v4.2M68 224.1v4.2M69.4 224.1v4.2M70.7 224.1v4.2M72.1 224.1v4.2M73.5 224.1v4.2"/>
<path d="M74.9 224.1v4.2M76.2 224.1v4.2M77.6 224.1v4.2M79 224.1v4.2M80.3 224.1v4.2M81.7 224.1v4.2M83.1 224.1v4.2M84.5 224.1v4.2M85.9 224.1v4.2M87.2 224.1v4.2M88.6 224.1v4.2"/>
<circle cx="55.6" cy="224.6" r=".39"/>
<circle cx="58.4" cy="224.6" r=".39"/>
<circle cx="61.1" cy="224.6" r=".4"/>
</g>
<path d="M54.3 163.2h38.4v14.2h-38.4z" fill-rule="evenodd" fill="#fff" stroke="#000" stroke-width=".13"/>
<g fill="none" stroke="#000" stroke-width=".13">
<path d="M55.6 159v4.2M57 159v4.2M61.1 159v4.2M62.5 159v4.2M79 159v4.2M80.4 159v4.2M81.7 159v4.2M83.1 159v4.2M84.5 159v4.2M85.9 159v4.2M87.2 159v4.2M88.6 159v4.2"/>
<path d="M55 174.8v1.7M55.6 178.2v3.5M57.7 174.5v2M58.4 178.2v3.5M60.5 174.8v1.7M61.1 178.2v3.5M66.6 177.4v4.3M68 177.4v4.3M69.4 177.4v4.3M70.7 177.4v4.3M72.1 177.4v4.3M73.5 177.4v4.3"/>
<path d="M74.9 177.4v4.3M76.2 177.4v4.3M77.6 177.4v4.3M79 177.4v4.3M80.4 177.4v4.3M81.7 177.4v4.3M83.1 177.4v4.3M84.5 177.4v4.3M85.9 177.4v4.3M87.2 177.4v4.3M88.6 177.4v4.3"/>
<circle cx="55.6" cy="177.8" r=".39"/>
<circle cx="58.4" cy="177.8" r=".39"/>
<circle cx="61.1" cy="177.9" r=".4"/>
</g>
<path d="M54.3 115.1h38.4v14.1h-38.4z" fill-rule="evenodd" fill="#fff" stroke="#000" stroke-width=".13"/>
<g fill="none" stroke="#000" stroke-width=".13">
<path d="M55.6 110.8v4.3M57 110.8v4.3M61.1 110.8v4.3M62.5 110.8v4.3M79 110.8v4.3M80.4 110.8v4.3M81.7 110.8v4.3M83.1 110.8v4.3M84.5 110.8v4.3M85.9 110.8v4.3M87.2 110.8v4.3M88.6 110.8v4.3"/>
<path d="M55 126.7v1.7M55.6 130.1v3.4M57.7 126.4v2M58.4 130.1v3.4M60.5 126.7v1.7M61.1 130.1v3.4M66.6 129.2v4.3M68 129.2v4.3M69.4 129.2v4.3M70.7 129.2v4.3M72.1 129.2v4.3M73.5 129.2v4.3"/>
<path d="M74.9 129.2v4.3M76.2 129.2v4.3M77.6 129.2v4.3M79 129.2v4.3M80.4 129.2v4.3M81.7 129.2v4.3M83.1 129.2v4.3M84.5 129.2v4.3M85.9 129.2v4.3M87.2 129.2v4.3M88.6 129.2v4.3"/>
<circle cx="55.6" cy="129.7" r=".39"/>
<circle cx="58.4" cy="129.7" r=".39"/>
<circle cx="61.1" cy="129.7" r=".4"/>
</g>
<path d="M54.3 65.5h38.4v14.2h-38.4z" fill-rule="evenodd" fill="#fff" stroke="#000" stroke-width=".13"/>
<g fill="none" stroke="#000" stroke-width=".13">
<path d="M55.6 59.7h1.4v5.8M62.5 59.7v5.8M63.9 59.7h-2.8v5.8M55 77.1v1.7M55.6 61.3v4.2M57.7 76.8v2M60.5 77.1v1.7M66.6 79.7v4.2M68 79.7v4.2M69.4 79.7v4.2M70.7 79.7v4.2M72.1 79.7v4.2"/>
<path d="M73.5 79.7v4.2M74.9 79.7v4.2M76.2 79.7v4.2M77.6 79.7v4.2M79 79.7v4.2M79 61.3v4.2M80.4 79.7v4.2M80.4 61.3v4.2M81.7 61.3v4.2M81.7 79.7v4.2M83.1 61.3v4.2M83.1 79.7v4.2"/>
<path d="M84.5 61.3v4.2M84.5 79.7v4.2M85.9 79.7v4.2M85.9 61.3v4.2M87.2 79.7v4.2M87.2 61.3v4.2M88.6 61.3v4.2M88.6 79.7v4.2M55.6 80.5v3.4M58.4 80.5v3.4M61.1 80.5v3.4M55.6 107.9h1.4v2.9"/>
<path d="M62.5 107.9v2.9M63.9 107.9h-2.8v2.9M55.6 157.4h1.4v1.6M62.5 157.4v1.6M63.9 157.4h-2.8v1.6M55.6 204.1h1.4v1.6M62.5 204.1v1.6M63.9 204.1h-2.8v1.6"/>
<circle cx="55.6" cy="80.1" r=".39"/>
<circle cx="58.4" cy="80.1" r=".39"/>
<circle cx="61.1" cy="80.2" r=".4"/>
</g>
<path d="M117.4 210h38.5v14.1h-38.5z" fill-rule="evenodd" fill="#fff" stroke="#000" stroke-width=".13"/>
<g fill="none" stroke="#000" stroke-width=".13">
<path d="M120.2 205.7v4.3M121.5 205.7v4.3M122.9 205.7v4.3M124.3 205.7v4.3M128.4 205.7v4.3M129.8 205.7v4.3M131.1 205.7v4.3M132.5 205.7v4.3M133.9 205.7v4.3M135.3 205.7v4.3M136.7 205.7v4.3M138 205.7v4.3"/>
<path d="M139.4 205.7v4.3M140.8 205.7v4.3M142.2 205.7v4.3M143.5 205.7v4.3M144.9 205.7v4.3M146.3 205.7v4.3M147.6 205.7v4.3M149 205.7v4.3M151.8 205.7v4.3M153.1 205.7v4.3M119.5 221.6v1.7M120.2 225v3.3"/>
<path d="M121.5 224.1v4.2M122.9 224.1v4.2M123.6 220.7v2.6M124.3 224.1v4.2M125 221.6v1.7M125.7 225v3.3M128.4 224.1v4.2M129.8 224.1v4.2M131.1 224.1v4.2M132.5 224.1v4.2M133.9 224.1v4.2M135.3 224.1v4.2"/>
<path d="M136.7 224.1v4.2M138 224.1v4.2M139.4 224.1v4.2M140.8 224.1v4.2M142.2 224.1v4.2M143.5 224.1v4.2M144.9 224.1v4.2M146.3 224.1v4.2M147.6 224.1v4.2M149 224.1v4.2M150.4 224.1v4.2"/>
<circle cx="120.1" cy="224.6" r=".4"/>
<circle cx="125.6" cy="224.6" r=".39"/>
</g>
<path d="M117.4 163.2h38.5v14.2h-38.5z" fill-rule="evenodd" fill="#fff" stroke="#000" stroke-width=".13"/>
<g fill="none" stroke="#000" stroke-width=".13">
<path d="M119.6 158.4l1.1 1.2M120.2 159v4.2M120.7 158.4l-1.1 1.2M121 158.4l1.1 1.2M121.5 159v4.2M122.1 158.4l-1.1 1.2M122.4 158.4l1.1 1.2M122.9 159v4.2M123.5 158.4l-1.1 1.2M123.7 158.4l1.1 1.2M124.3 159v4.2M124.8 158.4l-1.1 1.2"/>
<path d="M127 148.9l1.4 1.4M128.4 159v4.2M128.4 148.9l1.4 1.4M129.8 159v4.2M129.8 148.9l1.4 1.4M131.2 159v4.2M131.2 148.9l1.3 1.4M132.5 159v4.2M132.5 148.9l1.4 1.4M133.9 159v4.2M133.9 148.9l1.4 1.4M135.3 159v4.2"/>
<path d="M135.3 148.9l1.4 1.4M136.7 159v4.2M136.7 148.9l1.3 1.4M138 159v4.2M138 148.9l1.4 1.4M139.4 159v4.2M139.4 148.9l1.4 1.4M140.8 159v4.2M140.8 148.9l1.4 1.4M142.2 159v4.2M142.2 148.9l1.3 1.4M143.5 159v4.2"/>
<path d="M143.5 148.9l1.4 1.4M144.9 159v4.2M144.9 148.9l1.4 1.4M146.3 159v4.2M146.3 148.9l1.3 1.4M147.6 159v4.2M147.6 148.9l1.4 1.4M149 159v4.2M153.1 157.6v5.6M154.5 157.6h-2.7v5.6M119.5 174.8v1.7M120.2 178.2v3.5"/>
<path d="M121.5 177.4v6.2h1.4M122.9 177.4v8.4M123.6 174v2.5M124.3 177.4v5.5h-1.4M125 174.8v1.7M125.7 178.2v3.5M128.4 177.4v4.3M129.8 177.4v4.3M131.2 177.4v4.3M132.5 177.4v4.3M133.9 177.4v4.3M135.3 177.4v4.3"/>
<path d="M136.7 177.4v4.3M138 177.4v4.3M139.4 177.4v4.3M140.8 177.4v4.3M142.2 177.4v4.3M143.5 177.4v4.3M144.9 177.4v4.3M146.3 177.4v4.3M147.6 177.4v4.3M149 177.4v4.3M150.4 177.4v4.3M163.8 168.9v2.8h-2.7"/>
<path d="M163.8 171.7h1.4M165.2 170.3h.4v2.8h-.4zM166 170.3h.2v2.8h-.2zM166.2 171.7h4.5M170.7 171v1.4M127 195.8l1.4 1.4M128.4 195.8l1.4 1.4M129.8 195.8l1.3 1.4M131.1 195.8l1.4 1.4M132.5 195.8l1.4 1.4M133.9 195.8l1.4 1.4M135.3 195.8l1.4 1.4"/>
<path d="M136.7 195.8l1.3 1.4M138 195.8l1.4 1.4M139.4 195.8l1.4 1.4M140.8 195.8l1.4 1.4M142.2 195.8l1.3 1.4M143.5 195.8l1.4 1.4M144.9 195.8l1.4 1.4M146.3 195.8l1.3 1.4M147.6 195.7l1.4 1.4M157.2 199.9h2.8v11.3M157.2 199.2v1.4M119.6 205.1l1.1 1.2"/>
<path d="M120.7 205.1l-1.1 1.2M121 205.1l1.1 1.2M122.1 205.1l-1.1 1.2M122.4 205.1l1.1 1.2M123.5 205.1l-1.1 1.2M123.7 205.1l1.1 1.2M124.8 205.1l-1.1 1.2M153.1 204.3v1.4M154.5 204.3h-2.7v1.4M160 216.9v19.8h-2.8M166.9 205.6v34M121.5 228.3v2.9h1.4"/>
<path d="M122.9 228.3v4.2M124.3 228.3v1.4h-1.4"/>
<circle cx="120.1" cy="177.9" r=".4"/>
<circle cx="125.6" cy="177.8" r=".39"/>
</g>
<path d="M101 148.9h46.6M101 195.7h46.6" fill="none" stroke="#000" stroke-width=".42"/>
<g fill="none" stroke="#000" stroke-width=".3">
<path d="M55.6 158.3h-.8v.2M122.9 184.4h-.8v.3"/>
<circle cx="54.8" cy="159.1" r=".54"/>
<circle cx="122" cy="185.3" r=".54"/>
</g>
<path d="M70.3 242.2v6.7M138.5 240.6v10.9" fill="none" stroke="#695d7c" stroke-width=".13"/>
<g fill="#000" stroke="#000" stroke-width=".13">
<circle cx="55.7" cy="59.7" r=".25"/>
<circle cx="62.5" cy="59.7" r=".25"/>
<circle cx="55.7" cy="107.9" r=".25"/>
<circle cx="62.5" cy="107.9" r=".25"/>
<circle cx="55.7" cy="157.4" r=".25"/>
<circle cx="62.5" cy="157.4" r=".25"/>
<circle cx="153.1" cy="157.6" r=".27"/>
<circle cx="163.9" cy="171.7" r=".25"/>
<circle cx="122.9" cy="183.7" r=".25"/>
<circle cx="55.7" cy="204.2" r=".25"/>
<circle cx="62.5" cy="204.2" r=".25"/>
<circle cx="153.1" cy="204.3" r=".25"/>
<circle cx="122.9" cy="231.2" r=".25"/>
</g>
<g fill="#a06e56" stroke="#a06e56" stroke-width=".13">
<circle cx="122.9" cy="229.6" r=".25"/>
<circle cx="122.9" cy="182.9" r=".25"/>
</g>
<path d="M20.4 28.5h165.2v237.5h-165.2z" fill="none" stroke="#000" stroke-width=".71" stroke-linecap="butt"/>
<use href="#words"/>
</svg>
